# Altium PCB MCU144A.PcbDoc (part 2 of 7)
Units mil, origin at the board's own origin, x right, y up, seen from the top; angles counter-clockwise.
Board outline 2755.9 x 2276.49 mil, 10 copper layers (Top Layer, L02_GND1, L03_SIG1, L04_GND2, L05_SIG2, L06_PWR, L07_GND3, L08_SIG3, L09_GND4, Bottom Layer), stack 60.4 mil thick; 253 components, 312 nets, 1289 pads, 832 vias.

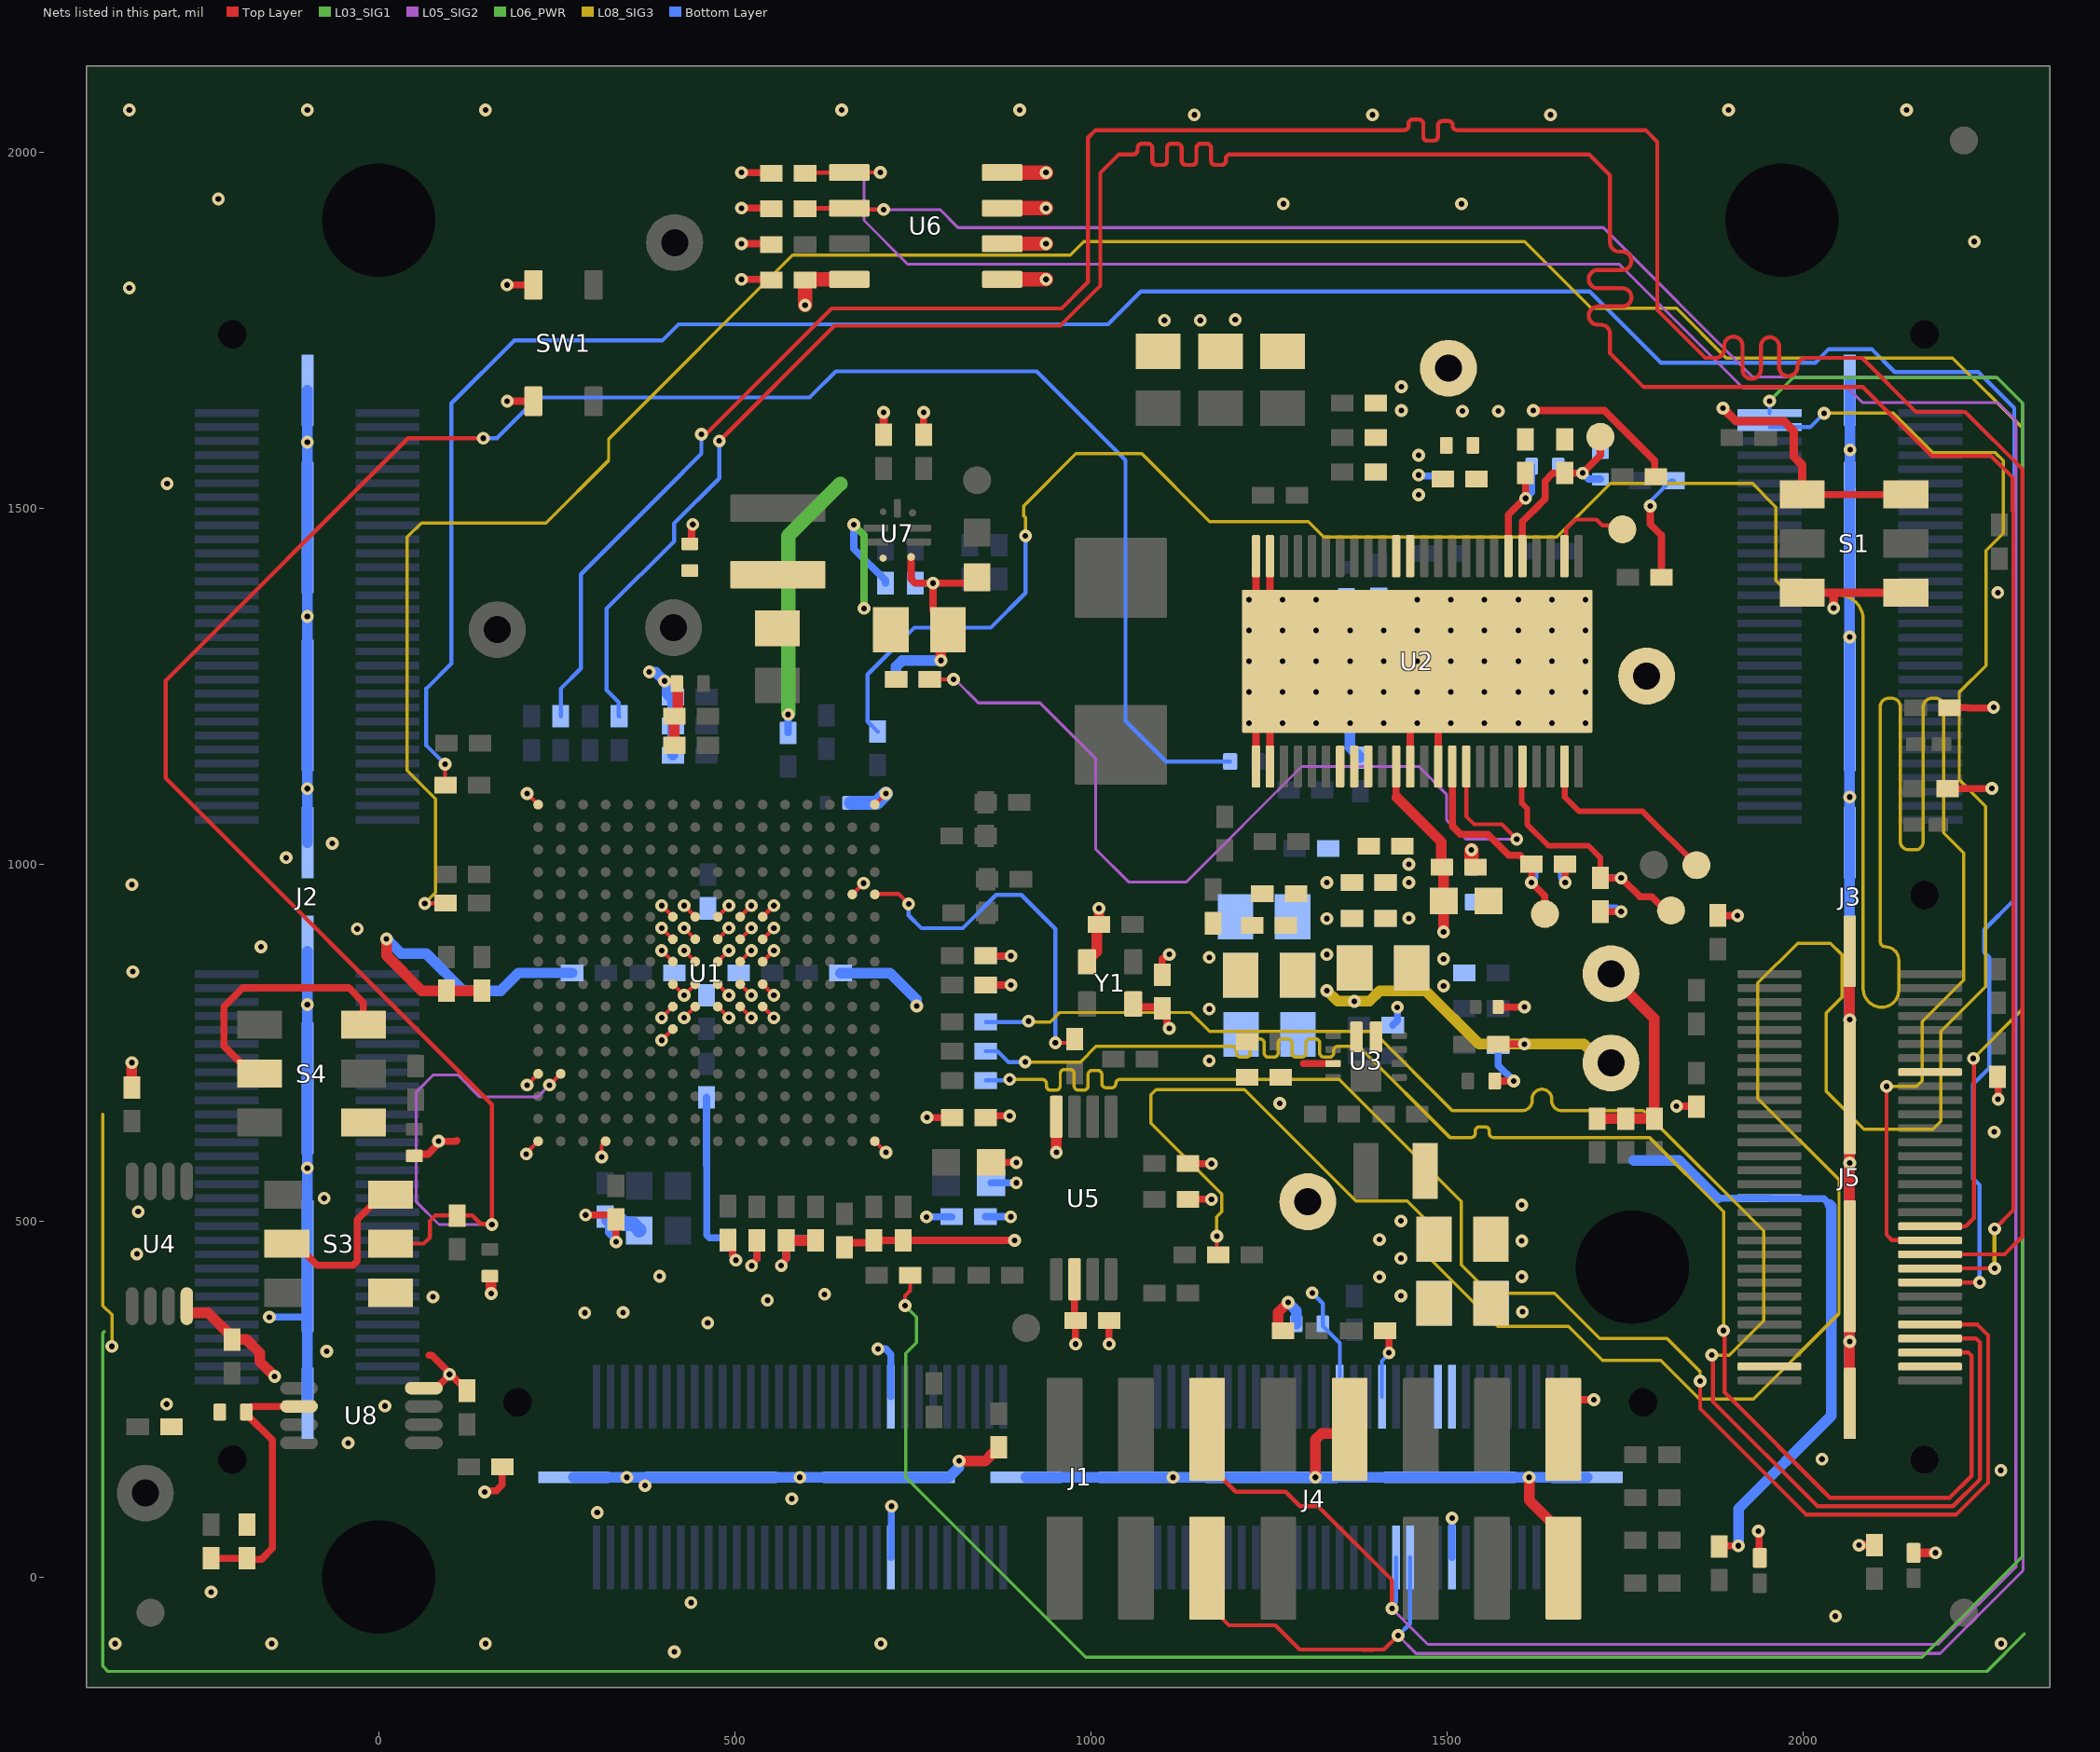
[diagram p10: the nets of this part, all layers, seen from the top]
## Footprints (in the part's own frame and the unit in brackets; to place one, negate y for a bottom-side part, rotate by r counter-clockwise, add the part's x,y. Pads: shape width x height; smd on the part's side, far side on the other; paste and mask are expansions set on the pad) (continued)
ZEX0256A-MFG [mm]
  round 0.35 smd paste+0 mask+0.05: A1(-6,6) A2(-5.2,6) A3(-4.4,6) A4(-3.6,6) A5(-2.8,6) A6(-2,6) A7(-1.2,6) A8(-0.4,6) A9(0.4,6) A10(1.2,6) A11(2,6) A12(2.8,6) A13(3.6,6) A14(4.4,6) A15(5.2,6) A16(6,6) B1(-6,5.2) B2(-5.2,5.2) B3(-4.4,5.2) B4(-3.6,5.2) B5(-2.8,5.2) B6(-2,5.2) B7(-1.2,5.2) B8(-0.4,5.2) B9(0.4,5.2) B10(1.2,5.2) B11(2,5.2) B12(2.8,5.2) B13(3.6,5.2) B14(4.4,5.2) B15(5.2,5.2) B16(6,5.2) C1(-6,4.4) C2(-5.2,4.4) C3(-4.4,4.4) C4(-3.6,4.4) C5(-2.8,4.4) C6(-2,4.4) C7(-1.2,4.4) C8(-0.4,4.4) C9(0.4,4.4) C10(1.2,4.4) C11(2,4.4) C12(2.8,4.4) C13(3.6,4.4) C14(4.4,4.4) C15(5.2,4.4) C16(6,4.4) D1(-6,3.6) D2(-5.2,3.6) D3(-4.4,3.6) D4(-3.6,3.6) D5(-2.8,3.6) D6(-2,3.6) D7(-1.2,3.6) D8(-0.4,3.6) D9(0.4,3.6) D10(1.2,3.6) D11(2,3.6) D12(2.8,3.6) D13(3.6,3.6) D14(4.4,3.6) D15(5.2,3.6) D16(6,3.6) E1(-6,2.8) E2(-5.2,2.8) E3(-4.4,2.8) E4(-3.6,2.8) E5(-2.8,2.8) E6(-2,2.8) E7(-1.2,2.8) E8(-0.4,2.8) E9(0.4,2.8) E10(1.2,2.8) E11(2,2.8) E12(2.8,2.8) E13(3.6,2.8) E14(4.4,2.8) E15(5.2,2.8) E16(6,2.8) F1(-6,2) F2(-5.2,2) F3(-4.4,2) F4(-3.6,2) F5(-2.8,2) F6(-2,2) F7(-1.2,2) F8(-0.4,2) F9(0.4,2) F10(1.2,2) F11(2,2) F12(2.8,2) F13(3.6,2) F14(4.4,2) F15(5.2,2) F16(6,2) G1(-6,1.2) G2(-5.2,1.2) G3(-4.4,1.2) G4(-3.6,1.2) G5(-2.8,1.2) G6(-2,1.2) G7(-1.2,1.2) G8(-0.4,1.2) G9(0.4,1.2) G10(1.2,1.2) G11(2,1.2) G12(2.8,1.2) G13(3.6,1.2) G14(4.4,1.2) G15(5.2,1.2) G16(6,1.2) H1(-6,0.4) H2(-5.2,0.4) H3(-4.4,0.4) H4(-3.6,0.4) H5(-2.8,0.4) H6(-2,0.4) H7(-1.2,0.4) H8(-0.4,0.4) H9(0.4,0.4) H10(1.2,0.4) H11(2,0.4) H12(2.8,0.4) H13(3.6,0.4) H14(4.4,0.4) H15(5.2,0.4) H16(6,0.4) J1(-6,-0.4) J2(-5.2,-0.4) J3(-4.4,-0.4) J4(-3.6,-0.4) J5(-2.8,-0.4) J6(-2,-0.4) J7(-1.2,-0.4) J8(-0.4,-0.4) J9(0.4,-0.4) J10(1.2,-0.4) J11(2,-0.4) J12(2.8,-0.4) J13(3.6,-0.4) J14(4.4,-0.4) J15(5.2,-0.4) J16(6,-0.4) K1(-6,-1.2) K2(-5.2,-1.2) K3(-4.4,-1.2) K4(-3.6,-1.2) K5(-2.8,-1.2) K6(-2,-1.2) K7(-1.2,-1.2) K8(-0.4,-1.2) K9(0.4,-1.2) K10(1.2,-1.2) K11(2,-1.2) K12(2.8,-1.2) K13(3.6,-1.2) K14(4.4,-1.2) K15(5.2,-1.2) K16(6,-1.2) L1(-6,-2) L2(-5.2,-2) L3(-4.4,-2) L4(-3.6,-2) L5(-2.8,-2) L6(-2,-2) L7(-1.2,-2) L8(-0.4,-2) L9(0.4,-2) L10(1.2,-2) L11(2,-2) L12(2.8,-2) L13(3.6,-2) L14(4.4,-2) L15(5.2,-2) L16(6,-2) M1(-6,-2.8) M2(-5.2,-2.8) M3(-4.4,-2.8) M4(-3.6,-2.8) M5(-2.8,-2.8) M6(-2,-2.8) M7(-1.2,-2.8) M8(-0.4,-2.8) M9(0.4,-2.8) M10(1.2,-2.8) M11(2,-2.8) M12(2.8,-2.8) M13(3.6,-2.8) M14(4.4,-2.8) M15(5.2,-2.8) M16(6,-2.8) N1(-6,-3.6) N2(-5.2,-3.6) N3(-4.4,-3.6) N4(-3.6,-3.6) N5(-2.8,-3.6) N6(-2,-3.6) N7(-1.2,-3.6) N8(-0.4,-3.6) N9(0.4,-3.6) N10(1.2,-3.6) N11(2,-3.6) N12(2.8,-3.6) N13(3.6,-3.6) N14(4.4,-3.6) N15(5.2,-3.6) N16(6,-3.6) P1(-6,-4.4) P2(-5.2,-4.4) P3(-4.4,-4.4) P4(-3.6,-4.4) P5(-2.8,-4.4) P6(-2,-4.4) P7(-1.2,-4.4) P8(-0.4,-4.4) P9(0.4,-4.4) P10(1.2,-4.4) P11(2,-4.4) P12(2.8,-4.4) P13(3.6,-4.4) P14(4.4,-4.4) P15(5.2,-4.4) P16(6,-4.4) R1(-6,-5.2) R2(-5.2,-5.2) R3(-4.4,-5.2) R4(-3.6,-5.2) R5(-2.8,-5.2) R6(-2,-5.2) R7(-1.2,-5.2) R8(-0.4,-5.2) R9(0.4,-5.2) R10(1.2,-5.2) R11(2,-5.2) R12(2.8,-5.2) R13(3.6,-5.2) R14(4.4,-5.2) R15(5.2,-5.2) R16(6,-5.2) T1(-6,-6) T2(-5.2,-6) T3(-4.4,-6) T4(-3.6,-6) T5(-2.8,-6) T6(-2,-6) T7(-1.2,-6) T8(-0.4,-6) T9(0.4,-6) T10(1.2,-6) T11(2,-6) T12(2.8,-6) T13(3.6,-6) T14(4.4,-6) T15(5.2,-6) T16(6,-6)
  silkscreen extent -7.17,-6.55 6.55,6.55, body extent -7.05,-7.05 7.05,7.05, height 0.25

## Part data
C1 C2 C46 C49 C52 C53 C61 C63 C65 C70 C72 C86: library part CMP-0120207-1, "10 µF ±20% 10V Ceramic Capacitor X5R 0402 (1005 Metric)", Manufacturer=Murata, Operating Temperature Range="-55°C to +85°C", TempCo=15%, Temperature Characteristic=X5R, Tolerance_%=20%, ValueDisplayed=10uF
C3 C4 C5 C13 C14 C31 C32 C41 C84 C92: library part CMP-0081010-1, "CAP, CERM, 2.2 µF, 25 V,+/- 20%, X5R, 0402", Cap_Case=0402, Manufacturer=MuRata, Supplier Part Number 1=490-10457-1-ND, TempCo=X5R, Tolerance_%=20%, Value2=25V, ValueDisplayed=2.2µF
C6 C7 C8 C9 C10 C11 C12 C15 C16 C17 C18 C19 C20 C21 C22 C23 C24 C25 C26 C27 C35 C36 C37 C38 C39 C40 C45 C58 C59 C60 C62 C64 C67 C69 C71 C73 C74 C75 C76 C77 C81 C83 C85 C88 C91 C93: library part CMP-0006659-2, "CAP, CERM, 0.1 uF, 25 V, +/- 10%, X7R, 0402", Cap_Case=0402, Manufacturer=MuRata, Supplier Part Number 1=490-10698-1-ND, TempCo=X7R, Tolerance_%=10%, Value1=Unknown, Value2=25V, ValueDisplayed=0.1uF
C28 C29 C30 C48 C54 C55 C56 C68 C89 C90: library part CMP-0008305-2, "CAP, CERM, 22 uF, 25 V, +/- 20%, X5R, 0805", Cap_Case=0805, Manufacturer=MuRata, Supplier Part Number 1=490-10749-1-ND, TempCo=X5R, Tolerance_%=20%, Value1=Unknown, Value2=25V, ValueDisplayed=22uF
C33 C34 C51 C57: library part CMP-0006412-2, "CAP, CERM, 1000 pF, 50 V, +/- 5%, C0G/NP0, 0402", Cap_Case=0402, Manufacturer=MuRata, Supplier Part Number 1=490-3244-1-ND, TempCo=C0G/NP0, Tolerance_%=5%, Value1=Unknown, Value2=50V, ValueDisplayed=1000pF
C42 C80 C82: library part CMP-0120206-1, "4.7 µF ±20% 25V Ceramic Capacitor X5S 0402 (1005 Metric)", Manufacturer=Murata, Operating Temperature Range="-55°C to +85°C", TempCo=22%, Temperature Characteristic=X5S, Tolerance_%=20%, ValueDisplayed=4.7uF
C43 C44 C50: library part CMP-0078699-1, "CAP, CERM, 47 µF, 10 V,+/- 20%, X5R, 0805", Cap_Case=0805, Manufacturer=MuRata, Supplier Part Number 1=490-9961-1-ND, TempCo=X5R, Tolerance_%=20%, Value2=10V, ValueDisplayed=47µF
C47: library part CMP-0120205-1, "Multi-Layer Ceramic Capacitor 47pF C0G  ±5% 0402 Paper T/R", Manufacturer=Murata, Operating Temperature Range="-55°C to +125°C", TempCo=30ppm/°C, Temperature Characteristic=C0G, Tolerance_%=5%, ValueDisplayed=47pF
C66: library part CMP-0007336-5, "CAP, CERM, 10 uF, 16 V, +/- 20%, X5R, 0603", Cap_Case=0603, Manufacturer=MuRata, Supplier Part Number 1=GRM188R61C106MAALD-ND, TempCo=X5R, Tolerance_%=20%, Value1=Unknown, Value2=16V, ValueDisplayed=10uF
C78 C79 C87: library part CMP-0086061-1, "CAP, CERM, 1 µF, 25 V,+/- 10%, X5R, 0402", Cap_Case=0402, Manufacturer=MuRata, TempCo=X5R, Tolerance_%=10%, Value2=25V, ValueDisplayed=1µF
C96: library part CMP-0006823-4, "CAP, CERM, 330 pF, 50 V, +/- 5%, C0G/NP0, 0603", Cap_Case=0603, Manufacturer="Wurth Elektronik", Supplier Part Number 1=710-885012006060, TempCo=C0G/NP0, Tolerance_%=5%, Value1=Unknown, Value2=50V, ValueDisplayed=330pF
C97: library part CMP-0123381-1, "Ceramic Capacitor for Automotive 200pF ±1% 50VDC C0G 0402 Paper T/R", Manufacturer=Murata, Operating Temperature Range="-55°C to +125°C", TempCo=30ppm/°C, Temperature Characteristic=C0G, Tolerance_%=0.01%, ValueDisplayed=200pF
C98: library part CMP-0080703-2, "CAP, CERM, 390 pF, 50 V,+/- 10%, X7R, AEC-Q200 Grade 1, 0402", Cap_Case=0402, Manufacturer=MuRata, Supplier Part Number 1=81-GCM155R71H391KA7D, TempCo=X7R, Tolerance_%=10%, Value2=50V, ValueDisplayed=390pF
FID1 FID2 FID3 FID4 FID5 FID6: library part CMP-0077181-1, "Fiducial mark.  There is nothing to buy or mount.", Manufacturer=N/A
J1 J2 J3: library part CMP-0055973-1, "Connector,  0.5mm, 60x2, SMT", Manufacturer=Samtec, Supplier Part Number 1=SAM8181-ND
J4: library part CMP-0121706-1, "Conn Unshrouded HDR 16 POS 2.54mm Solder ST SMT", Manufacturer=Samtec, Operating Temperature Range="-55°C to +125°C"
J5: library part CMP-0088387-1, "CONN RCPT HI-SPD .5MM 60POS DL", Current_A=25A, Digikey Part Number=SAM8180-ND, Manufacturer=Samtec, Mouser Part Number=200-QSH03001LDA, Operating Temperature Range="-55°C to +125°C", Voltage_V=175V
L1: library part CMP-0003363-1, "Ferrite Bead, 220 ohm @ 100 MHz, 2 A, 0805", Manufacturer=MuRata, Supplier Part Number 1=490-1054-1-ND, Value1="0.045 ohm", Value2=2A, ValueDisplayed="220 ohm"
L2 L3 L6: library part CMP-0003173-2, "Ferrite Bead, 60 ohm @ 100 MHz, 3 A, 0603", Manufacturer="Wurth Elektronik", PartNumber=742792602, Supplier Part Number 1=732-4660-1-ND, Value1="0.04 ohm", Value2=3A, ValueDisplayed="60 ohm"
L4: library part CMP-0096709-1, "Inductor Power Shielded Wirewound 2.2uH 20% 100KHz Metal 12A 0.00814Ohm DCR Automotive T/R", Digikey Part Number=445-181515-1-ND, Manufacturer=TDK, Mouser Part Number=810-SPM7054VT-2R2M-D, Operating Temperature Range="-55°C to +155°C", Test Frequency=100kHz, Tolerance_%=20%
L5: library part CMP-0082609-1, "Inductor, Shielded, Metal Composite, 1.5 µH, 2.6 A, 0.06 ohm, SMD", Manufacturer=MuRata, PartNumber=DFE252012P-1R5M{}P2, Value1="0.06 ohm", Value2=2.6A, ValueDisplayed=1.5µH
L7: library part CMP-0090842-1, "Power Inductor, shielded, composite, 1uH 20% tol, DCR 7.2mOhms, SRF 65MHz, Isat 4.8A, Irms 13A, AEC-Q200", Manufacturer=Coilcraft, Operating Temperature Range="to +165°C", Self Resonant Frequency=65MHz, Test Frequency=1MHz, Tolerance_%=20%
LED1 LED2: library part CMP-0067681-2, "LED, Red, SMD", Color=Red, Manufacturer=Kingbright, Power_TotalModule=75mW, Value1=0.075W, Value2=1.95V
LED3 LED4: library part CMP-0067682-2, "LED, Green, SMD", Color=Green, Manufacturer=Kingbright, Power_TotalModule=75mW, Value1=0.075W, Value2=2.1V
Logo1: library part CMP-0074844-1
Logo2: library part CMP-0074838-1, "Texas Instrument Corporate Signature"
Logo3: library part CMP-0074847-1, "FCC_disclaimer"
Logo4: library part CMP-0074769-3, Manufacturer="Texas Instruments"
MH1 MH2 MH3 MH4: library part CMP-0078424-2, "PCB Mounting Hole, No Pad", Manufacturer=Any, PartNumber=N/A
R1 R4 R10 R16 R49 R50: library part CMP-0026631-1, "RES, 4.70 k, 1%, 0.063 W, 0402", Manufacturer="TE Connectivity", Power_W=63mW, Supplier Part Number 1=A121542CT-ND, TempCo="100 ppm/C", Tolerance_%=1%, Value2=0.063W, Value_Code=4k70, ValueDisplayed=4.70k
R2 R3 R6 R11 R21 R23 R24 R30 R33 R39 R40 R44: library part CMP-0077731-1, "RES, 10.0 k, 1%, 0.063 W, AEC-Q200 Grade 0, 0402", Manufacturer="Yageo America", Power_W=63mW, Supplier Part Number 1=YAG3436CT-ND, TempCo="100 ppm/C", Tolerance_%=1%, Value2=0.063W, Value_Code=10k0, ValueDisplayed=10.0k
R5: library part CMP-0092615-1, "12 kOhms ±1% 0.063W, 1/16W Chip Resistor 0402 (1005 Metric) Moisture Resistant Thick Film", Digikey Part Number=311-12.0KLRCT-ND, Manufacturer=Yageo, Mouser Part Number=603-RC0402FR-0712KL, Operating Temperature Range="-55°C to +155°C", Power_W=63mW, TempCo=100ppm/°C, Tolerance_%=1%
R7 R15 R22 R25 R26 R27 R28 R29 R31 R32 R35 R36 R37 R45 R52 R54 R55 R60 R61 R62 R63 R64 R65 R66 R67 R68 R69 R71 R74 R79 R81 R82 R83 R84 R86 R87 R88 R89 R90 R91 R92 R93 R94 R95 R96 R97: library part CMP-0026822-3, "RES, 0, 5%, 0.063 W, AEC-Q200 Grade 0, 0402", Manufacturer=Vishay-Dale, Power_W=63mW, Supplier Part Number 1=541-0.0JCT-ND, TempCo="200 ppm/C", Tolerance_%=5%, Value2=0.063W, Value_Code=0000, ValueDisplayed=0
R8 R19: library part CMP-0026733-1, "RES, 3.00 k, 1%, 0.0625 W, 0402", Manufacturer="Yageo America", Power_W=62.5mW, Supplier Part Number 1=311-3KLRCT-ND, TempCo="100 ppm/C", Tolerance_%=1%, Value2=0.0625W, Value_Code=3k00, ValueDisplayed=3.00k
R9: library part CMP-0026920-5, "RES, 3.9 k, 5%, 0.063 W, AEC-Q200 Grade 0, 0402", Manufacturer=Vishay-Dale, Power_W=63mW, Supplier Part Number 1=541-3.9KJCT-ND, TempCo="200 ppm/C", Tolerance_%=5%, Value2=0.063W, Value_Code=3k90, ValueDisplayed=3.9k
R12: library part CMP-0026280-2, "RES, 301 k, 1%, 0.063 W, AEC-Q200 Grade 0, 0402", Manufacturer=Vishay-Dale, Power_W=63mW, Supplier Part Number 1=541-301KLCT-ND, TempCo="100 ppm/C", Tolerance_%=1%, Value2=0.063W, Value_Code=301k
R13: library part CMP-0026187-2, "RES, 23.7 k, 1%, 0.063 W, AEC-Q200 Grade 0, 0402", Manufacturer=Vishay-Dale, Power_W=63mW, Supplier Part Number 1=541-23.7KLCT-ND, TempCo="100 ppm/C", Tolerance_%=1%, Value2=0.063W, Value_Code=23k7, ValueDisplayed=23.7k
R14: library part CMP-0026102-2, "RES, 1.05 M, 1%, 0.063 W, AEC-Q200 Grade 0, 0402", Manufacturer=Vishay-Dale, Power_W=63mW, Supplier Part Number 1=541-1.05MLCT-ND, TempCo="100 ppm/C", Tolerance_%=1%, Value2=0.063W, Value_Code=1M05, ValueDisplayed=1.05M
R17: library part CMP-0026046-3, "RES, 174 k, 1%, 0.063 W, AEC-Q200 Grade 0, 0402", Manufacturer=Vishay-Dale, Power_W=63mW, Supplier Part Number 1=541-174KLCT-ND, TempCo="100 ppm/C", Tolerance_%=1%, Value2=0.063W, Value_Code=174k
R18: library part CMP-0025973-3, "RES, 118 k, 1%, 0.063 W, AEC-Q200 Grade 0, 0402", Manufacturer=Vishay-Dale, Power_W=63mW, Supplier Part Number 1=541-118KLCT-ND, TempCo="100 ppm/C", Tolerance_%=1%, Value2=0.063W, Value_Code=118k
R20 R47 R48: library part CMP-0026854-5, "RES, 1.2 k, 5%, 0.063 W, AEC-Q200 Grade 0, 0402", Manufacturer=Vishay-Dale, Power_W=63mW, Supplier Part Number 1=541-1.2KJCT-ND, TempCo="200 ppm/C", Tolerance_%=5%, Value2=0.063W, Value_Code=1k20, ValueDisplayed=1.2k
R34 R38 R80: library part CMP-0026544-2, "RES, 75.0, 1%, 0.063 W, AEC-Q200 Grade 0, 0402", Manufacturer=Vishay-Dale, Power_W=63mW, Supplier Part Number 1=541-75.0LCT-ND, TempCo="100 ppm/C", Tolerance_%=1%, Value2=0.063W, Value_Code=75R0, ValueDisplayed=75.0
R41: library part CMP-0026231-2, "RES, 2.20 k, 1%, 0.063 W, AEC-Q200 Grade 0, 0402", Manufacturer=Vishay-Dale, Power_W=63mW, Supplier Part Number 1=541-2.20KLCT-ND, TempCo="100 ppm/C", Tolerance_%=1%, Value2=0.063W, Value_Code=2k20, ValueDisplayed=2.20k
R42 R43: library part CMP-0026237-2, "RES, 2.49 k, 1%, 0.063 W, AEC-Q200 Grade 0, 0402", Manufacturer=Vishay-Dale, Power_W=63mW, Supplier Part Number 1=541-2.49KLCT-ND, TempCo="100 ppm/C", Tolerance_%=1%, Value2=0.063W, Value_Code=2k49, ValueDisplayed=2.49k
R46: library part CMP-0026918-5, "RES, 3.3 k, 5%, 0.063 W, AEC-Q200 Grade 0, 0402", Manufacturer=Vishay-Dale, Power_W=63mW, Supplier Part Number 1=541-3.3KJCT-ND, TempCo="200 ppm/C", Tolerance_%=5%, Value2=0.063W, Value_Code=3k30, ValueDisplayed=3.3k
R53: library part CMP-0026657-1, "RES, 1.00 k, 1%, 0.1 W, 0402", Manufacturer=Panasonic, Power_W=100mW, Supplier Part Number 1=P1.00KLCT-ND, TempCo="100 ppm/C", Tolerance_%=1%, Value2=0.1W, Value_Code=1k00, ValueDisplayed=1.00k
R56 R58: library part CMP-0078660-1, "RES, 0.1, 1%, 0.25 W, 0402", Manufacturer=Panasonic, Power_W=250mW, Supplier Part Number 1=P17368CT-ND, TempCo="300 ppm/C", Tolerance_%=1%, Value2=0.25W, Value_Code=R100, ValueDisplayed=0.1
R59 R85: library part CMP-0025951-3, "RES, 100, 1%, 0.063 W, AEC-Q200 Grade 0, 0402", Manufacturer=Vishay-Dale, Power_W=63mW, Supplier Part Number 1=541-100LCT-ND, TempCo="100 ppm/C", Tolerance_%=1%, Value2=0.063W, Value_Code=100R, ValueDisplayed=100
R70: library part CMP-0025874-4, "RES, 0, 5%, 0.1 W, AEC-Q200 Grade 0, 0603", Manufacturer=Panasonic, Power_W=100mW, Supplier Part Number 1=P0.0GCT-ND, TempCo="600 ppm/C", Tolerance_%=5%, Value2=0.1W, Value_Code=0000, ValueDisplayed=0
R72: library part CMP-0026040-3, "RES, 16.2 k, 1%, 0.063 W, AEC-Q200 Grade 0, 0402", Manufacturer=Vishay-Dale, Power_W=63mW, Supplier Part Number 1=541-16.2KLCT-ND, TempCo="100 ppm/C", Tolerance_%=1%, Value2=0.063W, Value_Code=16k2, ValueDisplayed=16.2k
R73: library part CMP-0026034-3, "RES, 162 k, 1%, 0.063 W, AEC-Q200 Grade 0, 0402", Manufacturer=Vishay-Dale, Power_W=63mW, Supplier Part Number 1=541-162KLCT-ND, TempCo="100 ppm/C", Tolerance_%=1%, Value2=0.063W, Value_Code=162k
R76: library part CMP-0026021-3, "RES, 150 k, 1%, 0.063 W, AEC-Q200 Grade 0, 0402", Manufacturer=Vishay-Dale, Power_W=63mW, Supplier Part Number 1=541-150KLCT-ND, TempCo="100 ppm/C", Tolerance_%=1%, Value2=0.063W, Value_Code=150k
R77: library part CMP-0026027-3, "RES, 15.0 k, 1%, 0.063 W, AEC-Q200 Grade 0, 0402", Manufacturer=Vishay-Dale, Power_W=63mW, Supplier Part Number 1=541-15.0KLCT-ND, TempCo="100 ppm/C", Tolerance_%=1%, Value2=0.063W, Value_Code=15k0, ValueDisplayed=15.0k
S1 S3 S4: library part CMP-0002233-1, "Switch, Dual SPDT,  2 Pos, 0.1A, 6VDC, SMD", CurrentRating_mA=100A, Manufacturer="Copal Electronics", Supplier Part Number 1=CASD20JCT-ND
SW1: library part CMP-0087265-1, "SWITCH TACTILE SPST-NO 0.05A 16V", CurrentRating_mA=50mA, Manufacturer="C&K Components"
TP1 TP2 TP3 TP5 TP8 TP14 TP15 TP16 TP17: "TEST POINT.  No entry in BOM.", Manufacturer=N/A
TP4 TP6 TP7 TP9 TP10 TP11 TP12 TP13: library part CMP-0003825-1, "1mm Test Point, SMT", Manufacturer=Any
U1: library part CMP-0121934-2, "Real-Time Microcontroller", Frequency_Fixed=200MHz, Manufacturer="Texas Instruments", Max Supply Voltage=3.63V, Min Supply Voltage=1.14V, Operating Temperature Range="-40°C to +105°C"
U2: library part CMP-0095884-2, "Power Management IC For Safety-Relevant Applications HTSSOP48 5 Outputs 4 LDO and 1 Synchronous Buck-Boost Regulator", Manufacturer="Texas Instruments", Max Supply Voltage=28V, Min Supply Voltage=2.3V, Operating Temperature Range="-40°C to +150°C"
U3: library part CMP-0074067-1, "12.6-V, 7-A Fully-Integrated Synchronous Boost Converters in 2.0-mm x 2.5-mm VQFN Package, RNR0011A (VQFN-HR-11)", Alternate Manufacturer="Texas Instruments", Alternate PartNumber=TPS61089RNRT
U4: library part CMP-0040680-2, "Precision, Zero-Crossover, 20MHz, 0.9pA Ib, RRIO, CMOS Operational Amplifier, DGK0008A (VSSOP-8)", Manufacturer="Texas Instruments", Total Supply Voltage(Max)(+5V is 5, +/-5V is 10)=5.5, Total Supply Voltage(Min)(+5V is 5, +/-5V is 10)=1.8
U5: library part CMP-0094559-1, "Clock Clock Buffer IC 1:3 250 MHz 8-TSSOP", Digikey Part Number=296-LMK1C1103PWRCT-ND, Manufacturer="Texas Instruments", Max Supply Voltage=3.465V, Min Supply Voltage=1.71V, Mouser Part Number=595-LMK1C1103PWR, Nominal Supply Current=8-33mA, Operating Temperature Range="-40°C to +125°C"
U6: library part CMP-0082059-1, "16 Kb I2C EEPROM Serial, SOIC-8", Manufacturer="ON Semiconductor", Supplier Part Number 1=CAT24C16WI-GT3CT-ND
U7: library part CMP-0121948-1, "3-V to 18-V, 2-A, Automotive Low IQ Buck Converter with +165°C TJ", Digikey Part Number=296-TPS62902QRYTRQ1CT-ND, Manufacturer="Texas Instruments", Max Supply Voltage=18V, Min Supply Voltage=3V, Mouser Part Number=595-TPS62902QRYTRQ1, Nominal Supply Current=8mA, Operating Temperature Range="-40°C to +165°C", Output Voltage=0.4-5.5V, Switching Frequency=1/2.5MHz
U8: library part CMP-0032596-2, "Low Noise, Very Low Drift, Precision Series Voltage Reference, DGK0008A (VSSOP-8)", Manufacturer="Texas Instruments", Rating=Catalog, Temp Coeff(Max)(ppm/ degree C)=3
Y1: library part CMP-0096024-2, "High-Performance BAW Oscillator", Frequency Stability=25ppm, Frequency_Fixed=25MHz, Load Capacitance=30pF, Manufacturer="Texas Instruments", Max Supply Current=50mA, Max Supply Voltage=3.465V, Min Supply Voltage=2.375V, Operating Temperature Range="-40°C to +105°C"
ZZ1: library part CMP-0003616-3
ZZ2: library part CMP-0077236-1
ZZ3: library part CMP-0077237-1
ZZ4: library part CMP-0077238-1

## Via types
v1: diameter 18, hole 8, Top Layer to Bottom Layer, tented both sides, 776 vias
v2: diameter 19.68, hole 7.87, Top Layer to Bottom Layer, tented top, 54 vias
v3: diameter 18/18/18/18/18/18/18/18/18/18 (per signal layer), hole 8, Top Layer to Bottom Layer, tented both sides, 2 vias

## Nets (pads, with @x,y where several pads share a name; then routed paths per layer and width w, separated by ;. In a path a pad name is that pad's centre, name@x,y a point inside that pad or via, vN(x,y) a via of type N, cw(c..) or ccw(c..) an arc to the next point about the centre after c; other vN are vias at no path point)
3V3_LDO4: C69.1 C70.2 U2.30 | length 176
  Top Layer w10: U2.30@1585.89,1433.38 1585.89,1491.62 1608.82,1514.55 v1(1610,1514.55) C69.1@1610,1550
  Bottom Layer w10: v1(1610,1514.55) 1618.47,1523.02 C70.2@1618.47,1559.71
3V3_OUT: C4.1 C5.1 C62.1 C63.2 C74.1 C75.1 C77.1 J1.28 J4.1 L2.1 L3.1 R1.2 R4.2 R10.2 R16.2 R20.2 R30.2 R39.2 R40.2 R41.2 R46.2 R47.2 R48.2 R49.2 R50.2 R59.1 R85.1 S1.3 S1.6 TP16.1 U2.37 U2.38 U5.6 U6.8 Y1.4 | length 2064.1
  Top Layer w10: v1(509.25,1922) R49.2@551.38,1922 ; v1(509.25,1972) R50.2@551.38,1972 ; R39.2@654.16,462.63 660.97,469.44 691.97,469.44 R40.2@695.16,472.63 R41.2@736.16,472.63 v1(892.85,472.63) ; C4.1@851.98,647.5 885.64,647.5 v1(885.88,647.25) ; L3.1@859.66,582.23 v1@894.91,582.23 ; U5.6@976.97,418.02 976.97,363.37 978.15,362.19 C74.1@978.15,360.19 978.15,327.26 v1(978.31,327.1) ; Y1.4@1067.48,800.47 C75.1@1099.77,800.47 ; C75.1@1099.77,798.57 1106.58,791.76 1106.58,775.59 1109.77,772.4 v1(1109.77,770.23) v1@1110,770 ; R30.2@1136.26,580.38 v1(1169.18,580.38) ; R1.2@1412.62,346 1418.27,340.35 v1(1418.27,314.81) ; J4.1@1663,207.44 1663,229 1683,249 v1(1706,249) ; v1(1785.18,1503.69) 1785,1503.51 1785,1478.58 1800.69,1462.88 R16.2@1800.69,1403.68 ; R59.1@1880.05,929.04 1880.31,928.78 v1(1907.66,928.78) ; S1.6@1998.33,1520 S1.3@2144,1520 ; R20.2@2097,47.75 R20.2@2099.84,44.91 ; R47.2@2202.46,1106.99 2228.94,1106.99 2229.15,1106.78 v1@2264.59,1106.78 ; R48.2@2204.87,1220.57 2231.35,1220.57 2231.56,1220.36 v1@2267,1220.36 ; R85.1@2272.72,702.22 2273.36,702.86 v1(2273.36,670.94)
  Top Layer w12: v1(1887.16,1641.05) 1905.28,1622.94 1972.56,1622.94 1986.43,1609.07 1986.43,1573.3 1998.33,1561.39 S1.6@1998.33,1520 ; v1(2078.19,44.6) 2078.34,44.75 2099.69,44.75 R20.2@2099.84,44.91
  Top Layer w20: v1(598.62,1785.69) C77.1@598.62,1821 598.62,1822 U6.8@660.72,1822
  L06_PWR w20: v1@575,1213 575,1461.7 648.22,1534.92
  Bottom Layer w5.66: J1.28@1408.33,253.19 1408.33,303.2 1418.27,313.14 v1(1418.27,314.81) ; v1(1785.18,1503.69) 1787.54,1506.05 1787.54,1512.86 1814.05,1539.37 R10.2@1817.99,1539.37
  Bottom Layer w10: R46.2@574.63,1185.33 574.82,1185.52 574.82,1212.82 v1@575,1213 ; C5.1@851.78,505.98 v1@887.04,505.98 ; L2.1@859.66,553.68 v1@894.91,553.68 ; v1(1460,1547.3) 1461.53,1545.77 1489.8,1545.77 R4.2@1493.76,1541.81
  other v1: 887.23,505.79 895.1,553.49 895.11,582.03 2264.59,1107.42 575,1211 2267,1221 1460,1519.59 1460,1575
5V0_IN: C43.1 C44.1 C45.1 C50.1 J1.18 J1.20 J3.27 L5.1 R19.2 TP5.1 U3.9 | length 904.2
  Top Layer w10: 1298.07,721.02 U3.9@1339.96,721.02 ; R19.2@1881.81,42.75 1882.88,43.82 v1(1908.75,43.82)
  Bottom Layer w10: 1878.98,531.67 J3.27@1952.59,531.67 1953,531.27 2028.73,531.27 2037,523
  Bottom Layer w15: 1762,585 1825.65,585 1878.98,531.67 ; v1(1908.75,43.82) 1908.75,95.75 2039.29,226.29 2039.29,520.71 2037,523
  other v1: 1435,395 1405,421.25 1435,447.5 1405,473.75 1435,500 1265,665
5V0_LDO2: C52.2 C64.1 C65.2 L6.1 U2.11 | length 258.1
  Top Layer w10: U2.11@1428.41,1138.1 1428.41,1096.54 1429.26,1095.7
  Top Layer w15: 1429.26,1094.74 1491.94,1032.06 C64.1@1491.94,997.56 ; C64.1@1492.5,997 1495.07,994.43 L6.1@1495.07,940.69 ; v1(1495,905.81) L6.1@1495,940.62
5V0_OUT_CAN: C53.2 J1.34 L6.2 R3.2 R23.2 R24.2 TP17.1 | length 470.3
  Top Layer w15: R24.2@1710.74,643.7 R23.2@1750.74,643.7 R3.2@1790.75,643.7 1790.75,784.25 1730,845 TP17.1@1730,847
  Bottom Layer w5.66: v1(1310.56,398.97) 1325.37,384.15 C53.2@1325.37,355.4 1325.37,352.45 1349.27,328.55 J1.34@1349.27,253.19
+1V25: C1.2 C68.1 L1.1 L7.2 R72.2 R73.2 U7.3 | length 223.8
  L06_PWR w10: v1(666.97,1477.44) 681.38,1463.03 v1(681.38,1360)
  Bottom Layer w10: v1(666.97,1477.44) 666.97,1443.96 711.5,1399.42 R73.2@711.5,1395.49
+12V0: C28.1 C29.1 C30.1 C31.1 C32.1 C33.1 C34.1 C35.1 C36.1 C37.1 C48.1 C89.1 C90.1 R6.2 R14.2 TP8.1 U2.7 U2.8 U2.9 U3.6 | length 524.2
  Top Layer w10: R14.2@1571.54,748.33 v1(1608.4,748.33)
  L08_SIG3 w15: v1(1331.11,823.5) 1346.26,808.35 v1(1369.81,808.35) 1390.67,808.35 1405.31,823 1469.87,823 1544.54,748.33 v1(1608.4,748.33) 1691.71,748.33 1717.04,723 1709,723 TP8.1@1737,695
  other v1: 1331.11,874 1331.11,924.5 1331.11,975
ADC_3V0_VREF: C79.1 C86.2 R53.2 U8.6 | length 378
  Top Layer w10: R53.2@-235,26.38 C79.1@-185,26.38 -183.62,25 -164.5,25 -149.12,40.38 -149.12,192.16 -185.62,228.66 C86.2@-185.62,231.61 -185.62,234.56 -181.76,238.42 -178.81,238.42 -177.61,239.61 U8.6@-111.81,239.61
CFG_VOUT1: C71.1 C72.2 TP6.1 U2.20 | length 384.9
  Top Layer w8: U2.20@1605.58,1138.1 1604.62,1137.15 1604.62,1086.66 1612.11,1079.17 1612.11,1056.89 1642.19,1026.81 1698.19,1026.81 1715,1010 C71.1@1715,981.5
  Top Layer w10: C71.1@1715,981.5 v1(1744.25,981.5) 1770.75,955 1787.08,955 1806.29,935.79 TP6.1@1814.24,935.79
  Bottom Layer w10: C72.2@1715,976.7 1718.86,980.56 1724.97,980.56 1725.91,981.5 v1(1744.25,981.5)
CFG_VOUT2: C61.2 C73.1 TP9.1 U2.29 | length 286.6
  Top Layer w10: U2.29@1605.58,1433.38 1605.58,1481.84 1635,1511.27 ; 1620.29,1496.56 1637.51,1513.78 1637.51,1538.91 1648.29,1549.69 1664.69,1549.69 C73.1@1665,1550 v1(1690,1550) 1715,1575 TP9.1@1715,1601
  Bottom Layer w10: v1(1690,1550) 1698.29,1541.71 1714.59,1541.71 C61.2@1715,1541.3
CFG_VOUT3: C49.2 C67.1 TP12.1 U2.15 | length 319.4
  Top Layer w10: U2.15@1507.52,1135 1507.52,1054.3 1518.83,1042.99 1557.01,1042.99 1586.57,1013.43 1602.01,1013.43 1614.44,1001 C67.1@1618.38,1001 v1(1618.38,975) 1637,956.37 TP12.1@1637,930.95
  Bottom Layer w10: v1(1618.38,975) 1618.38,977.16 1623.3,982.08 C49.2@1623.3,1001
COMP1_OUT: TP10.1 U2.23 | length 264.4
  Top Layer w8: U2.23@1665,1135 1665,1095.15 1685,1075.15 1774.41,1075.15 TP10.1@1850,999.56
COMP2_OUT: TP4.1 U2.26 | length 135.4
  Top Layer w5.66: U2.26@1664.63,1433.38 U2.26@1666.82,1435.57 ; U2.26@1665,1430.28 1666.82,1432.1 U2.26@1666.82,1435.57 ; TP4.1@1746,1471 1740.45,1476.55 1717.82,1476.55 1709.61,1484.77 1680.19,1484.77 1666.82,1471.4 U2.26@1666.82,1435.57
DLT_GPIO6: J5.44 R91.1 | length 4409.2
  Top Layer w5.66: v1(478.15,1595.1) 639.96,1756.91 956.88,1756.91 1013,1813.03 1013,1971.34 1039.19,1997.53 1056.29,1997.53 1059.12,1997.53 ccw(c1059.12,2003.72) 1065.32,2003.72 1065.32,2006.33 cw(c1071.52,2006.33) 1071.52,2012.53 1079.78,2012.53 cw(c1079.78,2006.33) 1085.98,2006.33 1085.98,1988.72 ccw(c1092.18,1988.72) 1092.18,1982.53 1100.44,1982.53 ccw(c1100.44,1988.72) 1106.64,1988.72 1106.64,2006.33 cw(c1112.84,2006.33) 1112.84,2012.53 1121.1,2012.53 cw(c1121.1,2006.33) 1127.3,2006.33 1127.3,1988.72 ccw(c1133.5,1988.72) 1133.5,1982.53 1141.76,1982.53 ccw(c1141.76,1988.72) 1147.96,1988.72 1147.96,2006.33 cw(c1154.16,2006.33) 1154.16,2012.53 1162.42,2012.53 cw(c1162.42,2006.33) 1168.62,2006.33 1168.62,1988.72 ccw(c1174.82,1988.72) 1174.82,1982.53 1183.08,1982.53 ccw(c1183.08,1988.72) 1189.28,1988.72 1189.28,1991.33 cw(c1195.48,1991.33) 1195.48,1997.53 1219.68,1997.53 1699.13,1997.53 1728.67,1967.99 1728.67,1876.53 1728.67,1873.7 ccw(c1741.5,1873.7) 1741.5,1860.87 1745.84,1860.87 cw(c1745.84,1848.04) 1745.84,1835.21 1711.5,1835.21 ccw(c1711.5,1822.38) 1711.5,1809.55 1745.84,1809.55 cw(c1745.84,1796.72) 1745.84,1783.89 1711.5,1783.89 ccw(c1711.5,1771.06) 1711.5,1758.23 1715.84,1758.23 cw(c1715.84,1745.4) 1728.67,1745.4 1728.67,1717.99 1735,1711.65 1751.65,1695 1775.91,1670.74 2083.64,1670.74 2180.39,1574 2263.42,1574 2293.94,1543.48 2293.94,1496.93 2294.64,1496.24 2294.64,515.07 v3(2268.39,488.83) ; J5.44@2177.8,433.35 v1(2268.39,433.35)
  L08_SIG3 w5.66: v1(2268.39,433.35) v3(2268.39,488.83)
  Bottom Layer w5.66: R91.1@337.63,1208.44 336.91,1209.16 336.91,1228.19 319.88,1245.22 319.88,1359.64 367.1,1406.85 367.72,1406.85 414.93,1454.07 414.93,1479.35 478.15,1542.57 v1(478.15,1595.1)
DLT_GPIO7: J5.46 R96.1 | length 4234.7
  Top Layer w5.66: v1(93.32,1141.27) 93.32,1112.4 R96.1@93.84,1111.89 ; J5.46@2177.8,413.66 v3(2247.44,413.66)
  Bottom Layer w5.66: v1(93.32,1141.27) 66.92,1167.67 66.92,1247.46 102.13,1282.68 102.13,1647.87 190.38,1736.13 398.16,1736.13 420.96,1758.93 1023.93,1758.93 1070,1805 1700,1805 1800,1705 2016.59,1705 2035.64,1724.05 2095.95,1724.05 2128.28,1691.72 2245.79,1691.72 2296.02,1641.49 2296.02,951.02 2253.83,908.83 2253.83,877.17 2260.91,870.1 2260.91,714.9 2237.99,691.99 2237.99,559.59 2247.44,550.15 v3@2247.44,414.41
DLT_GPIO8: J5.42 R83.1 | length 4420.8
  Top Layer w5.66: v1@452.76,1598.12 635.81,1781.17 958.68,1781.17 995.79,1818.28 995.79,2020.93 1006.44,2031.58 1436.71,2031.58 1439.54,2031.58 ccw(c1439.54,2037.78) 1445.73,2037.78 1445.73,2040.38 cw(c1451.93,2040.38) 1451.93,2046.58 1460.2,2046.58 cw(c1460.2,2040.38) 1466.39,2040.38 1466.39,2022.78 ccw(c1472.59,2022.78) 1472.59,2016.58 1480.86,2016.58 ccw(c1480.86,2022.78) 1487.05,2022.78 1487.05,2038.08 cw(c1493.25,2038.08) 1493.25,2044.28 1501.52,2044.28 cw(c1501.52,2038.08) 1507.71,2038.08 1507.71,2037.78 ccw(c1513.91,2037.78) 1513.91,2031.58 1564.83,2031.58 1778.42,2031.58 1795,2015 1795,1779 1862.31,1711.69 1873.31,1711.69 1876.14,1711.69 ccw(c1876.14,1724.52) 1888.97,1724.52 1888.97,1728.86 cw(c1901.8,1728.86) 1914.63,1728.86 1914.63,1695.23 ccw(c1927.46,1695.23) 1940.29,1695.23 1940.29,1727.92 cw(c1953.12,1727.92) 1965.95,1727.92 1965.95,1698.85 ccw(c1978.78,1698.85) 1991.61,1698.85 cw(c2004.44,1698.86) 2004.44,1711.69 2041.33,1711.69 2082.31,1711.69 2158,1636 2227,1636 2307.62,1555.38 2307.62,478.2 2282.44,453.03 J5.42@2177.8,453.03
  Bottom Layer w5.66: R83.1@255.63,1208.44 255.63,1247.37 283.94,1275.68 283.94,1407.86 427.97,1551.9 427.97,1552.29 453.05,1577.36 v1(453.05,1604.37)
DLT_GPIO16: J5.38 R84.1 | length 4336
  Top Layer w5.66: v1(64.81,945.82) 93.33,945.82 R84.1@93.75,946.24 ; J5.38@2177.8,492.4 2227.74,492.4 2239.31,503.97 2239.31,727.54 v1(2238.66,728.18) v1@2238.44,728.4
  L08_SIG3 w4.5: v1(64.81,945.82) 80,961.01 80,1092.5 40,1132.5 40,1460 60,1480 235,1480 322.9,1567.9 322.9,1597.9 581.22,1856.22 971.08,1856.22 989.86,1875 1608.49,1875 1702.1,1781.39 1822,1781.39 1891.7,1711.69 2209.22,1711.69 2307.12,1613.79 2307.12,796.64 v1(2238.66,728.18)
DLT_GPIO49: J5.54 R90.1 | length 2262.3
  Top Layer w5.66: v1(1871.48,311.61) 1872.89,310.2 1872.89,246.42 2019.76,99.55 2210.09,99.55 2247.8,137.26 2247.8,329.45 2242.18,335.07 2177.94,335.07 J5.54@2177.8,334.92
  L08_SIG3 w4.5: v1(912.24,780.48) 913.33,779.39 942.79,779.39 955.97,792.58 1139.79,792.58 1166.37,766 1396,766 1507,655 1548.24,655 1605.49,655 ccw(c1605.49,668.75) 1619.24,668.75 1619.24,671.25 cw(c1632.99,671.25) 1646.74,671.25 1646.74,668.75 ccw(c1660.49,668.75) 1660.49,655 1680,655 1775.22,655 1944.28,485.94 1944.28,360.01 1895.88,311.61 v1(1871.48,311.61)
  Bottom Layer w5.66: R90.1@852.26,779.3 911.05,779.3 v1(912.24,780.48)
DLT_GPIO50: J5.56 R95.1 | length 2214.1
  Top Layer w5.66: v1(1887.9,346.16) 1889.31,344.75 1889.31,259.29 2037.39,111.21 2205.26,111.21 2236.14,142.09 2236.14,310.76 2231.73,315.18 2177.86,315.18 J5.56@2177.8,315.24
  L08_SIG3 w4.5: v1(907.52,723.11) 985.11,723.11 1007,745 1176.51,745 1198.26,745 cw(c1198.26,739.15) 1204.11,739.15 1204.11,735.85 ccw(c1209.96,735.85) 1209.96,730 1217.76,730 ccw(c1217.76,735.85) 1223.61,735.85 1223.61,749.65 cw(c1229.46,749.65) 1229.46,755.5 1237.26,755.5 cw(c1237.26,749.65) 1243.11,749.65 1243.11,735.85 ccw(c1248.96,735.85) 1248.96,730 1256.76,730 ccw(c1256.76,735.85) 1262.61,735.85 1262.61,749.65 cw(c1268.46,749.65) 1268.46,755.5 1276.26,755.5 cw(c1276.26,749.65) 1282.11,749.65 1282.11,735.85 ccw(c1287.96,735.85) 1287.96,730 1295.76,730 ccw(c1295.76,735.85) 1301.61,735.85 1301.61,749.65 cw(c1307.46,749.65) 1307.46,755.5 1315.26,755.5 cw(c1315.26,749.65) 1321.11,749.65 1321.11,735.85 ccw(c1326.96,735.85) 1326.96,730 1334.76,730 ccw(c1334.76,735.85) 1340.61,735.85 1340.61,739.15 cw(c1346.46,739.15) 1346.46,745 1376,745 1377.17,743.83 1503.77,617.23 1531.45,617.23 1533.7,617.23 ccw(c1533.7,623.08) 1539.55,623.08 1539.55,626.38 cw(c1545.4,626.38) 1545.4,632.23 1553.2,632.23 cw(c1553.2,626.38) 1559.05,626.38 1559.05,623.08 ccw(c1564.9,623.08) 1564.9,617.23 1598,617.23 1783.77,617.23 1887.9,513.1 v1(1887.9,346.16)
  Bottom Layer w5.66: R95.1@852.26,738.3 868.7,738.3 883.89,723.11 v1(907.52,723.11)
DLT_GPIO51: J5.52 R82.1 | length 2162.3
  Top Layer w5.66: v1(1855.06,275.1) 1855.06,236.45 2003.61,87.89 2138.16,87.89 2157.48,87.89 2209.92,87.89 2212.39,87.89 2214.92,87.89 2259.47,132.43 2259.47,134.97 2259.47,137.44 2259.47,339.36 2244.39,354.44 2177.97,354.44 J5.52@2177.8,354.61
  L08_SIG3 w4.5: v1(885.86,698.68) 909.73,698.68 931.48,698.68 cw(c931.48,692.83) 937.33,692.83 937.33,689.53 ccw(c943.18,689.53) 943.18,683.68 950.98,683.68 ccw(c950.98,689.53) 956.83,689.53 956.83,706.76 cw(c962.68,706.76) 962.68,712.61 970.48,712.61 cw(c970.48,706.76) 976.33,706.76 976.33,689.53 ccw(c982.18,689.53) 982.18,683.68 989.98,683.68 ccw(c989.98,689.53) 995.83,689.53 995.83,705.31 cw(c1001.68,705.31) 1001.68,711.16 1009.48,711.16 cw(c1009.48,705.31) 1015.33,705.31 1015.33,692.83 ccw(c1021.18,692.83) 1021.18,686.98 1028.98,686.98 ccw(c1028.98,692.83) 1034.83,692.83 cw(c1040.68,692.83) 1040.68,698.68 1076.51,698.68 1348.6,698.68 1520,527.28 1520,438.37 1559.78,398.59 1650.41,398.59 1714,335 1808.59,335 1855.06,288.54 v1(1855.06,275.1)
  Bottom Layer w5.66: R82.1@852.26,697.3 v1@885.86,697.3
DLT_GPIO76: J5.40 R92.1 | length 4316.3
  Top Layer w5.66: v1(2116.7,688.87) 2116.7,480.71 2124.33,473.08 2177.44,473.08 J5.40@2177.8,472.72
  L08_SIG3 w4.5: v1@908,1464 908,1487.6 905.75,1489.85 905.75,1504.15 978.85,1577.25 1071.3,1577.25 1166.55,1482 1305,1482 1327,1460 1653.72,1460 1729,1535.28 1928.56,1535.28 1961.63,1502.21 1961.63,1399.37 1982.18,1378.82 2049.18,1378.82 cw(c2049.18,1344) 2084,1344 2084,826 ccw(c2110,826) 2110,800 ccw(c2110,824) 2134,824 2134,866 ccw(c2115,866) 2115,885 cw(c2115,892) 2108,892 2108,1222 cw(c2120,1222) 2120,1234 2124,1234 cw(c2124,1222) 2136,1222 2136,1033 ccw(c2148,1033) 2148,1021 2157,1021 ccw(c2157,1032) 2168,1032 2168,1221 cw(c2181,1221) 2181,1234 2185,1234 cw(c2185,1222) 2197,1222 2197,1044.77 2225.01,1016.76 2225.01,838.01 2167,780 2167,696.86 2159.01,688.87 v1(2116.7,688.87)
  Bottom Layer w5.66: R92.1@700.54,1186.98 686.22,1201.3 686.22,1267.22 752,1333 859.22,1333 908,1381.78 v1(908,1462) v1@908,1464
ECAT_PHY0_CLK: J3.117 R31.1 R32.1 | length 3900.8
  Top Layer w5.66: R32.1@1176.57,452.5 v1@1176.57,477.5
  L08_SIG3 w4.5: v1(1176.57,478.5) 1176.57,505.97 1183.43,512.83 1183.43,537.78 1084,637.22 1084,677 1091.31,684.31 1215.69,684.31 1372,528 1444,528 1470,502 1470,453 1571,352 1670,352 1718,304 1800,304 1854,250 1930,250 2050,370 2050,557.95 1936,671.95 1936,834 1992,890 2038,890 2054,874 2054,814 2032,792 2032,682 2085,629 2182,629 2193,640 2193,766 2256,829 2256,1082.16 2218.8,1119.36 2218.8,1242.35 2256.39,1279.94 2256.39,1441.39 2280.69,1465.69 2280.69,1524.31 2280.57,1524.43 2280.57,1567.43 2269,1579 2181,1579 2126,1634 v1(2029,1634)
  Bottom Layer w5.66: J3.117@1952.59,1614.47 2009.47,1614.47 v1(2029,1634)
ECAT_PHY1_CLK: J3.119 R35.1 R97.1 | length 4050.3
  Top Layer w5.66: v1(739,381) 739,395 746.28,402.28 R35.1@746.28,423.69
  L03_SIG1 w4.5: v1(739,381) 755,365 755,329 740,314 740,140 992.45,-112.45 2166.55,-112.45 2307.62,28.62 2307.62,1648.38 2272,1684 1985.44,1684 v1(1952.59,1651.15)
  Bottom Layer w5.66: J3.119@1952.59,1634.15 v1(1952.59,1651.15)
EEPROM_I2CSCL: J1.23 J4.12 R49.1 U6.6 | length 4867
  Top Layer w5.66: U6.6@660.72,1922 662.65,1920.06 v1(709.03,1920.06) ; J4.12@1163,12.56 1163,-37.17 1193.55,-67.71 1258.76,-67.71 1292.81,-101.77 1381.04,-101.77 1381.17,-101.89 1395.94,-101.89 1396.06,-101.77 1411.29,-101.77 v1(1431.05,-82.01)
  Top Layer w6.66: R49.1@598.62,1922 U6.6@660.72,1922
  L05_SIG2 w4: v1(709.03,1920.06) 787.94,1920.06 813.35,1894.65 1719.17,1894.65 1928.82,1685 2270.44,1685 2308.5,1646.94 2308.5,9.3 2191.96,-107.25 1456.28,-107.25 v1(1431.05,-82.01)
  Bottom Layer w5.66: v1(1431.05,-82.01) 1447.7,-65.36 J1.23@1447.7,27.59
EEPROM_I2CSDA: J1.25 J4.11 R50.1 U6.5 | length 4966.6
  Top Layer w5.66: R50.1@598.62,1972 U6.5@660.72,1972 660.8,1972.08 v1(704.23,1972.08) ; J4.11@1163,207.44 1163,160 1203.2,119.8 1273.25,119.8 1293.51,99.54 1318.74,99.54 1422.48,-4.19 v1(1422.48,-44.24)
  L05_SIG2 w4: v1(704.23,1972.08) 686.38,1972.08 681.34,1967.04 681.34,1904.66 742.85,1843.15 1741.84,1843.15 1916,1669 2063,1669 2083,1649 2272.9,1649 2298.3,1623.59 2298.3,14.3 2189.43,-94.57 1472.81,-94.57 v1(1422.48,-44.24)
  Bottom Layer w5.66: v1(1422.48,-44.24) 1422.48,-40.9 1428.01,-35.37 J1.25@1428.01,27.59
EXT_VMON1: R72.1 R77.2 U2.16 | length 1336.4
  Top Layer w5.66: R72.1@773.75,1260.41 808.91,1260.41 v1@808.95,1260.45 ; U2.16@1526.84,1138.1 1526.84,1067.84 1537.86,1056.82 1576.84,1056.82 v1(1597.66,1036)
  L05_SIG2 w4: v1@808.91,1260.41 841.96,1227.36 928.37,1227.36 1006.42,1149.31 1006.42,1022.34 1053.24,975.52 1133.35,975.52 1295.83,1138 1460.25,1138 1498.97,1099.28 1498.97,1063.23 1526.2,1036 v1(1597.66,1036)
  Bottom Layer w5.66: R77.2@773.75,1260.41 v1@808.91,1260.41
  other v1: 806.91,1260.41
EXT_VMON2: R5.2 R56.2 S3.2 U1.N2 | length 3758.8
  Top Layer w5.66: S3.2@16.83,468 63.22,468 72.13,476.91 72.13,500.27 79.46,507.6 R56.2@109.99,507.6 131.43,507.6 143.17,495.85 158.14,495.85 v1(159,495) 159,663.46 -299.08,1121.53 -299.08,1258.56 41.36,1599 v1(147,1599) ; v1(239.79,690.73) U1.N2@255.53,706.48
  L05_SIG2 w4: v1(159,495) 84.73,495 52.95,526.78 52.95,681.2 76.58,704.83 111.22,704.83 142.05,674 223.05,674 v1(239.79,690.73)
  Bottom Layer w5.66: v1(147,1599) 166.06,1599 223.18,1656.11 604.99,1656.11 641.71,1692.83 923.88,1692.83 1048.47,1568.24 1048.47,1201.85 1105.31,1145 R5.2@1195.32,1145
EXT_VREFHIAB: S3.3 S3.5 | length 233.7
  Top Layer w10: S3.5@-128.83,468 -117.02,468 -86.55,437.53 -35.86,437.53 -30,443.39 -30,501.88 5.02,536.9 S3.3@16.83,536.9
EXT_VREFHICDE: S4.3 S4.5 | length 367.9
  Top Layer w10: S4.5@-167,706.9 -178.81,706.9 -217.39,745.47 -217.39,800.54 -190.61,827.32 -42.12,827.32 -21.33,806.53 S4.3@-21.33,775.8
F29H85x_25MHZ_CLK: R34.2 U1.E16 | length 510.3
  Top Layer w5.66: U1.E16@696.48,958.45 697.29,959.26 729.74,959.26 v1(744,945) ; v1(950,750) 974.94,750 R34.2@976.97,752.04
  Bottom Layer w5.66: v1(744,945) 744,929 762,911 820,911 866.93,957.93 902.07,957.93 950,910 v1(950,750)
GND: C1.1 C2.1 C3.2 C4.2 C5.2 C6.2 C7.2 C8.2 C9.2 C10.2 C11.2 C12.2 C13.2 C14.2 C15.2 C16.2 C17.2 C18.2 C19.2 C20.2 C21.2 C22.2 C23.2 C24.2 C25.2 C26.2 C27.2 C28.2 C29.2 C30.2 C31.2 C32.2 C33.2 C34.2 C35.2 C36.2 C37.2 C41.1 C42.2 C43.2 C44.2 C45.2 C46.1 C47.1 C48.2 C49.1 C50.2 C51.2 C52.1 C53.1 C54.2 C55.2 C56.2 C57.2 C58.2 C59.2 C60.2 C61.1 C62.2 C63.1 C64.2 C65.1 C66.2 C67.2 C68.2 C69.2 C70.1 C71.2 C72.1 C73.2 C74.2 C75.2 C76.2 C77.2 C78.2 C79.2 C80.1 C81.2 C82.1 C83.2 C84.2 C85.2 C86.1 C87.2 C88.2 C89.2 C90.2 C91.2 C92.1 C93.1 C96.2 C97.1 C98.1 J1.17 J1.77 J1.78 J1.121 J1.122 J1.123 J1.124 J1.125 J1.126 J1.127 J1.128 J2.121 J2.122 J2.123 J2.124 J2.125 J2.126 J2.127 J2.128 J3.121 J3.122 J3.123 J3.124 J3.125 J3.126 J3.127 J3.128 J4.2 J4.7 J5.16 J5.57 J5.58 J5.P1 J5.P2 J5.P3 J5.P4 LED1.2 LED2.2 R2.1 R8.1 R9.1 R11.1 R17.1 R18.1 R28.1 R33.1 R37.1 R44.1 R68.1 R69.2 R76.1 R77.1 R87.1 S1.1 S1.4 SW1.1 SW1.2 TP3.1 U1.A1 U1.A16 U1.E15 U1.F7 U1.F8 U1.F9 U1.F10 U1.F11 U1.G7 U1.G8 U1.G9 U1.G10 U1.G11 U1.H7 U1.H8 U1.H9 U1.H10 U1.H11 U1.J7 U1.J8 U1.J9 U1.J10 U1.J11 U1.K7 U1.K8 U1.K9 U1.K10 U1.K11 U1.L7 U1.N1 U1.T1 U1.T4 U1.T16 U2.1 U2.2 U2.12 U2.14 U2.47 U2.48 U2.49 U3.5 U4.4 U5.4 U6.1 U6.2 U6.3 U6.4 U7.4 U8.4 Y1.2 | length 14272
  Top Layer w5.66: v1(207.31,593.91) 207.31,595.27 U1.T1@224.04,611.99 ; v1(208.29,690.73) U1.N1@224.04,706.48 ; v1(208.29,1100.18) U1.A1@224.04,1084.43 ; v1(313.05,589.94) 313.05,606.51 U1.T4@318.53,611.99 ; v1(397.27,753.72) U1.L7@413.01,769.47 ; v1(397.27,785.22) U1.K7@413.01,800.97 ; v1(397.27,879.71) U1.H7@413.01,863.96 ; v1(397.27,911.2) U1.G7@413.01,895.46 ; v1(397.27,942.7) U1.F7@413.01,926.95 ; U1.J7@413.01,832.46 v1(428.76,816.72) U1.J8@444.51,832.46 ; v1(428.76,785.22) U1.K8@444.51,800.97 ; v1(428.76,879.71) U1.H8@444.51,863.96 ; v1(428.76,911.2) U1.G8@444.51,895.46 ; v1(428.76,942.7) U1.F8@444.51,926.95 ; U1.K9@476.01,800.97 v1(491.75,785.22) ; U1.J9@476.01,832.46 v1(491.75,816.72) ; U1.H9@476.01,863.96 v1(491.75,879.71) ; U1.G9@476.01,895.46 v1(491.75,911.2) ; U1.F9@476.01,926.95 v1(491.75,942.7) ; U1.K10@507.5,800.97 v1(523.25,785.22) ; U1.J10@507.5,832.46 v1(523.25,816.72) ; U1.H10@507.5,863.96 v1(523.25,879.71) ; U1.G10@507.5,895.46 v1(523.25,911.2) ; U1.F10@507.5,926.95 v1(523.25,942.7) ; U1.K11@539,800.97 v1(554.75,785.22) ; U1.J11@539,832.46 v1(554.75,816.72) ; U1.H11@539,863.96 v1(554.75,879.71) ; U1.G11@539,895.46 v1(554.75,911.2) ; U1.F11@539,926.95 v1(554.75,942.7) ; U1.E15@664.98,958.45 v1(680.73,974.2) ; U1.T16@696.48,611.99 v1(712.23,596.24) ; U1.A16@696.48,1084.43 v1(712.23,1100.18)
  Top Layer w10: C82.1@50,591.3 52.42,593.72 69.25,593.72 82.52,607 82.52,610.42 v1(84.06,611.95) 108.86,611.95 109.75,612.84 ; U8.4@63.39,265.2 80.57,265.2 99.44,284.07 v1(99.44,284.6) ; 70.57,311.35 74.51,311.35 99.44,286.41 v1(99.44,284.6) ; C85.2@124.28,261.71 124.28,265.65 117.47,272.46 113.53,272.46 101.39,284.6 v1(99.44,284.6) ; v1(148.98,119.5) 150.51,121.03 165.17,121.03 173.62,129.47 C84.2@173.62,155 ; v1(180.23,1814.12) 216.96,1814.12 SW1.2@217.17,1814.33 ; v1(180.44,1650.94) SW1.1@217.17,1650.94 ; v1(290.53,508.37) 326.88,508.37 C3.2@333,502.25 ; v1@333.19,470.53 C3.2@333.19,502.06 ; C1.1@432.79,1452.06 C1.1@434.05,1453.32 ; C1.1@436.76,1450.62 439.38,1453.24 439.38,1476.38 v1(440.91,1477.91) ; C92.1@490.16,473.61 496.97,466.8 496.97,452.68 v1@500.04,449.61 ; v1(509.25,1822) C77.2@551.38,1822 ; v1(509.25,1872) R69.2@551.38,1872 ; v1(523.54,436.97) 523.54,439.13 531.16,446.74 C24.2@531.16,472.61 ; v1@564.54,436.97 564.54,439.13 572.16,446.74 C25.2@572.16,472.61 ; U7.4@747.4,1432.11 747.4,1401.34 753.26,1395.49 v1(778.23,1395.49) ; R28.1@765,1603.62 v1(765,1635.21) ; v1@769.76,645.05 C4.2@805.01,645.05 ; C68.2@802,1333 778.23,1356.77 v1(778.23,1395.49) ; C66.2@840,1403.5 831.98,1395.49 v1(778.23,1395.49) ; C18.2@852.26,831.3 v1@887.51,831.3 ; C16.2@852.26,872.3 v1@887.51,872.3 ; v1@1025.4,327.26 C74.2@1025.4,360.19 C74.2@1025.4,362.19 ; C75.2@1099.77,845.81 1099.77,868.29 1101.75,868.29 1107.6,874.15 v1(1109.77,874.15) ; R33.1@1136.26,530.38 v1(1169.18,530.38) ; U2.49@1226.2,1367.26 1231.56,1372.62 U2.48@1231.56,1433.38 ; U2.1@1231.56,1138.1 U2.49@1231.56,1198.86 ; U2.2@1251.25,1138.1 U2.49@1251.25,1198.86 ; U2.49@1251.25,1372.62 U2.47@1251.25,1433.38 ; U2.12@1448.1,1138.1 U2.49@1448.1,1198.86 ; U2.14@1487.47,1138.1 U2.49@1487.47,1198.86 ; C46.1@1566.62,696.52 v1(1593.48,696.52) ; C47.1@1571.54,800.36 1598.4,800.36 ; v1(1620.79,1637.88) 1720.57,1637.88 1791.23,1567.21 1791.23,1546.69 R11.1@1792.93,1545 ; v1(1665.62,975) C67.2@1665.62,1001 ; C71.2@1715,934.25 v1(1744.25,934.25) ; v1(1821.91,661.1) 1849.02,661.1 R87.1@1849.55,660.56 ; v1(1936.77,64.55) 1937.81,63.51 1937.81,27.91 LED1.2@1938.84,26.88
  Top Layer w12: C98.1@708.91,1603.62 v1(708.91,1635.21) ; 2029.83,1382.2 2043.28,1382.2 ; v1@2041.38,1361.5 v1(2042.5,1360.38) 2042.5,1381.42 2043.28,1382.2 ; LED2.2@2154.84,34 v1(2185.52,34) ; S1.1@2155.81,1382.2 S1.1@2144,1382.2 2043.28,1382.2
  Top Layer w15: v1(-346.54,722.21) -346.41,722.08 C83.2@-346.41,687.26 ; v1(-297.57,242.69) v1@-296.76,242.69 ; U4.4@-269.23,380.4 -269.23,370.68 -239.12,370.68 -206,337.56 C87.2@-206,333.62 -185.62,333.62 -167,315 -167,302.69 v1(-146.01,281.7) ; v1(11,896) 11,872.66 60.37,823.29 C19.2@95.1,823.29 C21.2@144.93,823.29 ; C80.1@153.43,422.44 C80.1@156.09,422.44 156.24,422.44 157.6,421.08 157.6,398.62 v1(158.17,398.04) ; C9.2@415.01,1167.8 C6.2@415.01,1208.8 415.62,1208.8 419.94,1213.11 C2.1@419.94,1254.3 ; C25.2@572.16,472.61 C76.2@613.14,472.62 ; v1(789.25,1286.87) 789.25,1320.25 C68.2@799,1330 ; v1(815,163) 851.41,163 862.39,173.98 866.33,173.98 870.64,178.29 R44.1@870.64,182.23 ; v1(951.38,596.38) U5.4@951.38,646.36 ; Y1.2@994.52,859.53 Y1.2@994.52,863.73 994.52,864.45 1007.95,877.88 1007.95,908.99 1011.15,912.19 R37.1@1011.15,916.39 v1(1011.15,938.85) ; R2.1@1262.38,346 1262.38,371.33 v1(1276.6,385.55) ; v1(1315,140) 1315,193 1323.79,201.79 1357.35,201.79 J4.7@1363,207.44 ; v1(1615,140) 1615,108 1663,60 J4.2@1663,12.56 ; J5.P4@2065,243.78 v1(2065,330.61) J5.P3@2065,436.3 v1(2065,581.43) J5.P2@2065,686.3 v1(2065,782.56) J5.P1@2065,878.82
  Top Layer w18: v1(936.95,1972) v1@937,1971.95
  Top Layer w20: U6.1@875.28,1822 v1(936.95,1822) ; U6.2@875.28,1872 v1(936.95,1872) ; U6.3@875.28,1922 v1(936.95,1922) ; U6.4@875.28,1972 v1(936.95,1972) ; v1(1534.05,1020.95) 1534.05,998.81 1535.86,997 C64.2@1539.75,997
  L03_SIG1 w4.5: -385,345 -387.5,342.5 -387.5,-125 -380,-132.5 2257.5,-132.5 2310,-80
  L08_SIG3 w4.5: -387.24,649.9 -387.24,381 -374.36,368.12 v1(-374.36,323.85)
  Bottom Layer w5.66: v2(1221.72,1199.13) 1221.72,1196.56 1222.83,1195.44 v2@1222.83,1197.8
  Bottom Layer w10: v1@-152.32,365 -102.97,365 J2.127@-100,367.97 ; C14.2@318,506.17 322.46,501.71 322.46,483.71 v1@333.19,472.97 ; C81.2@460.26,673.47 460.26,578.23 460.53,577.96 460.53,480.43 464.44,476.52 486.25,476.52 C22.2@490.16,472.61 496.97,465.8 496.97,451.68 501.57,447.07 v1(501.57,444.91) ; v1(523.54,436.97) 523.54,439.13 531.16,446.74 C23.2@531.16,472.61 ; v1@564.54,436.97 564.54,439.13 572.16,446.74 C20.2@572.16,472.61 ; v1@565.03,437.26 v1(565.13,437.16) ; v1@699.03,320.3 v1(700.81,320.3) 711.69,320.3 719.23,312.75 J1.78@719.23,253.19 ; J1.77@719.23,27.59 719.54,27.9 719.54,99.11 v1(719.85,99.42) ; R76.1@753.23,1395.49 v1(778.23,1395.49) ; v1@769.1,505.79 C5.2@804.35,505.79 ; C17.2@852.26,831.3 v1@887.51,831.3 ; C26.2@852.26,872.3 v1@887.51,872.3 ; R68.1@1423.62,775 1430,781.38 v1(1430,800) ; J1.17@1506.75,27.59 v1(1506.84,82.74) ; R18.1@1571.5,746.42 1571.5,718.5 v1(1593.48,696.52) ; C49.1@1660.7,1001 1660.7,982.08 1665.62,977.16 v1(1665.62,975) ; C72.1@1715,939.3 1737.04,939.3 1742.09,934.25 v1(1744.25,934.25)
  Bottom Layer w15: J2.127@-100.96,351.28 J2.127@-100,352.24 ; J2.128@-100,243.78 J2.127@-100,352.24 ; J2.125@-100,878.82 v1(-100,803.86) J2.126@-100,686.3 v1(-100,574.3) J2.127@-100,436.3 -100,367.97 J2.127@-100,352.24 ; J2.124@-100,1031.18 v1(-100,1106.95) J2.123@-100,1223.7 v1(-100,1348.7) J2.122@-100,1473.7 v1(-100,1593.37) J2.121@-100,1666.22 ; v1(11,896) 31.6,875.4 66.62,875.4 118.72,823.29 C93.1@144.93,823.29 171.29,823.29 196.21,848.21 C13.2@271.51,848.21 ; J1.128@273.78,140 v1(348.37,140) J1.127@466.3,140 v1(591.3,140) J1.126@716.3,140 800.35,140 814.43,154.07 814.43,162.43 v1(815,163) ; v1(380.05,1270.88) 380.63,1270.31 389.08,1270.31 v1(401.27,1258.13) 401.27,1257.32 404.83,1253.75 404.83,1240.11 409.15,1235.8 C7.2@413.01,1235.8 C8.2@413.01,1194.8 C15.2@413.01,1153.8 ; C20.2@572.16,472.61 C27.2@613.12,472.62 ; C88.2@648.45,848.14 717.86,848.14 754.79,811.21 754.79,802.3 v1(755.36,801.72) ; R77.1@726.51,1260.41 726.51,1278.51 734.89,1286.89 v1(789.25,1286.87) ; J1.125@908.82,140 J1.124@1061.18,140 v1(1115,140) J1.123@1253.7,140 v1(1315,140) J1.122@1503.7,140 v1(1615,140) J1.121@1696.22,140 ; v1(1276.6,385.55) 1287.97,374.18 C53.1@1287.97,355.4 ; v2(1316.21,1372.35) 1316.68,1372.83 1349.53,1372.83 C42.2@1350,1373.3 ; v2(1363.45,1199.13) 1363.45,1165.21 R8.1@1377.92,1150.74 ; C41.1@1400,1367.76 1403.7,1371.46 1457.04,1371.46 v2(1457.94,1372.35) ; J3.121@2065,243.78 v1(2065,330.61) J3.122@2065,436.3 v1(2065,581.43) J3.123@2065,686.3 v1(2065,782.56) J3.124@2065,878.82 J3.125@2065,1031.18 v1(2065,1095.23) J3.126@2065,1223.7 v1(2065,1319.96) J3.127@2065,1473.7 v1(2065.48,1582.68) J3.128@2065.48,1678.94
  Bottom Layer w20: C14.2@322.46,501.71 339.81,501.71 345.52,496 357.07,496 365.77,487.3 C96.2@365.77,486.31 ; C97.1@663.48,1087.04 699.09,1087.04 v1(712.23,1100.18)
  other v1: 415,-105 -370,-93.51 -150,-93.51 150,-93.51 705,-93.51 2277.52,-93.51 2045,-55 438.49,-35.97 -235,-21 306.91,90.56 580,110 373.81,128.36 2277.3,149.86 2026.19,165.48 -42.67,188.31 8.92,240.11 -73,317 1025.56,327.1 461.93,356.95 -153.32,365 289.3,370.95 343.24,371.53 1605.59,372.4 545.73,388.65 76.09,393.34 626,397 394.37,422.47 1604.69,421.52 -339.37,453.54 333.39,470.53 1604.69,471.94 768.9,505.6 -337.61,513.04 1604.69,522.36 -76.47,531.83 2268.02,624.93 769.57,645.25 1166,725 1166,797.5 1608.4,800.36 1495,830 887.7,831.1 -345,850 1495,867.91 1166,870 887.7,872.1 -165,885 -30,910 1446.33,925 -346.47,972.15 1446.33,975 1446.33,1000.79 -130,1010 -65,1030 2272.93,1382.3 -297,1535 1521.26,1636.97 1571.68,1636.97 1435.68,1637.82 1435.59,1671.08 1103.01,1764.5 1153.43,1764.5 1202.54,1765.4 -350,1810 2240,1875 1270,1928 1520,1928 -225,1935 1145,2053 1395,2053 1645,2053 -350,2060 -100,2060 150,2060 650,2060 900,2060 1895,2060 2145,2060
  other v2: 1268.96,1199.13 1316.21,1199.13 1410.7,1199.13 1457.94,1199.13 1505.18,1199.13 1552.43,1199.13 1599.67,1199.13 1646.92,1199.13 1694.16,1199.13 1221.72,1242.43 1268.96,1242.43 1316.21,1242.43 1363.45,1242.43 1410.7,1242.43 1457.94,1242.43 1505.18,1242.43 1552.43,1242.43 1599.67,1242.43 1646.92,1242.43 1694.16,1242.43 1221.72,1285.74 1268.96,1285.74 1316.21,1285.74 1363.45,1285.74 1410.7,1285.74 1457.94,1285.74 1505.18,1285.74 1552.43,1285.74 1599.67,1285.74 1646.92,1285.74 1694.16,1285.74 1221.72,1329.05 1268.96,1329.05 1316.21,1329.05 1363.45,1329.05 1410.7,1329.05 1457.94,1329.05 1505.18,1329.05 1552.43,1329.05 1599.67,1329.05 1646.92,1329.05 1694.16,1329.05 1221.72,1372.35 1268.96,1372.35 1505.18,1372.35 1552.43,1372.35 1599.67,1372.35 1646.92,1372.35 1694.16,1372.35
INT_VREFHIAB: S3.1
INT_VREFHICDE: S4.1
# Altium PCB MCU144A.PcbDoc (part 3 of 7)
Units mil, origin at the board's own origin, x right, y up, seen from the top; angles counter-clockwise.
Board outline 2755.9 x 2276.49 mil, 10 copper layers (Top Layer, L02_GND1, L03_SIG1, L04_GND2, L05_SIG2, L06_PWR, L07_GND3, L08_SIG3, L09_GND4, Bottom Layer), stack 60.4 mil thick; 253 components, 312 nets, 1289 pads, 832 vias.

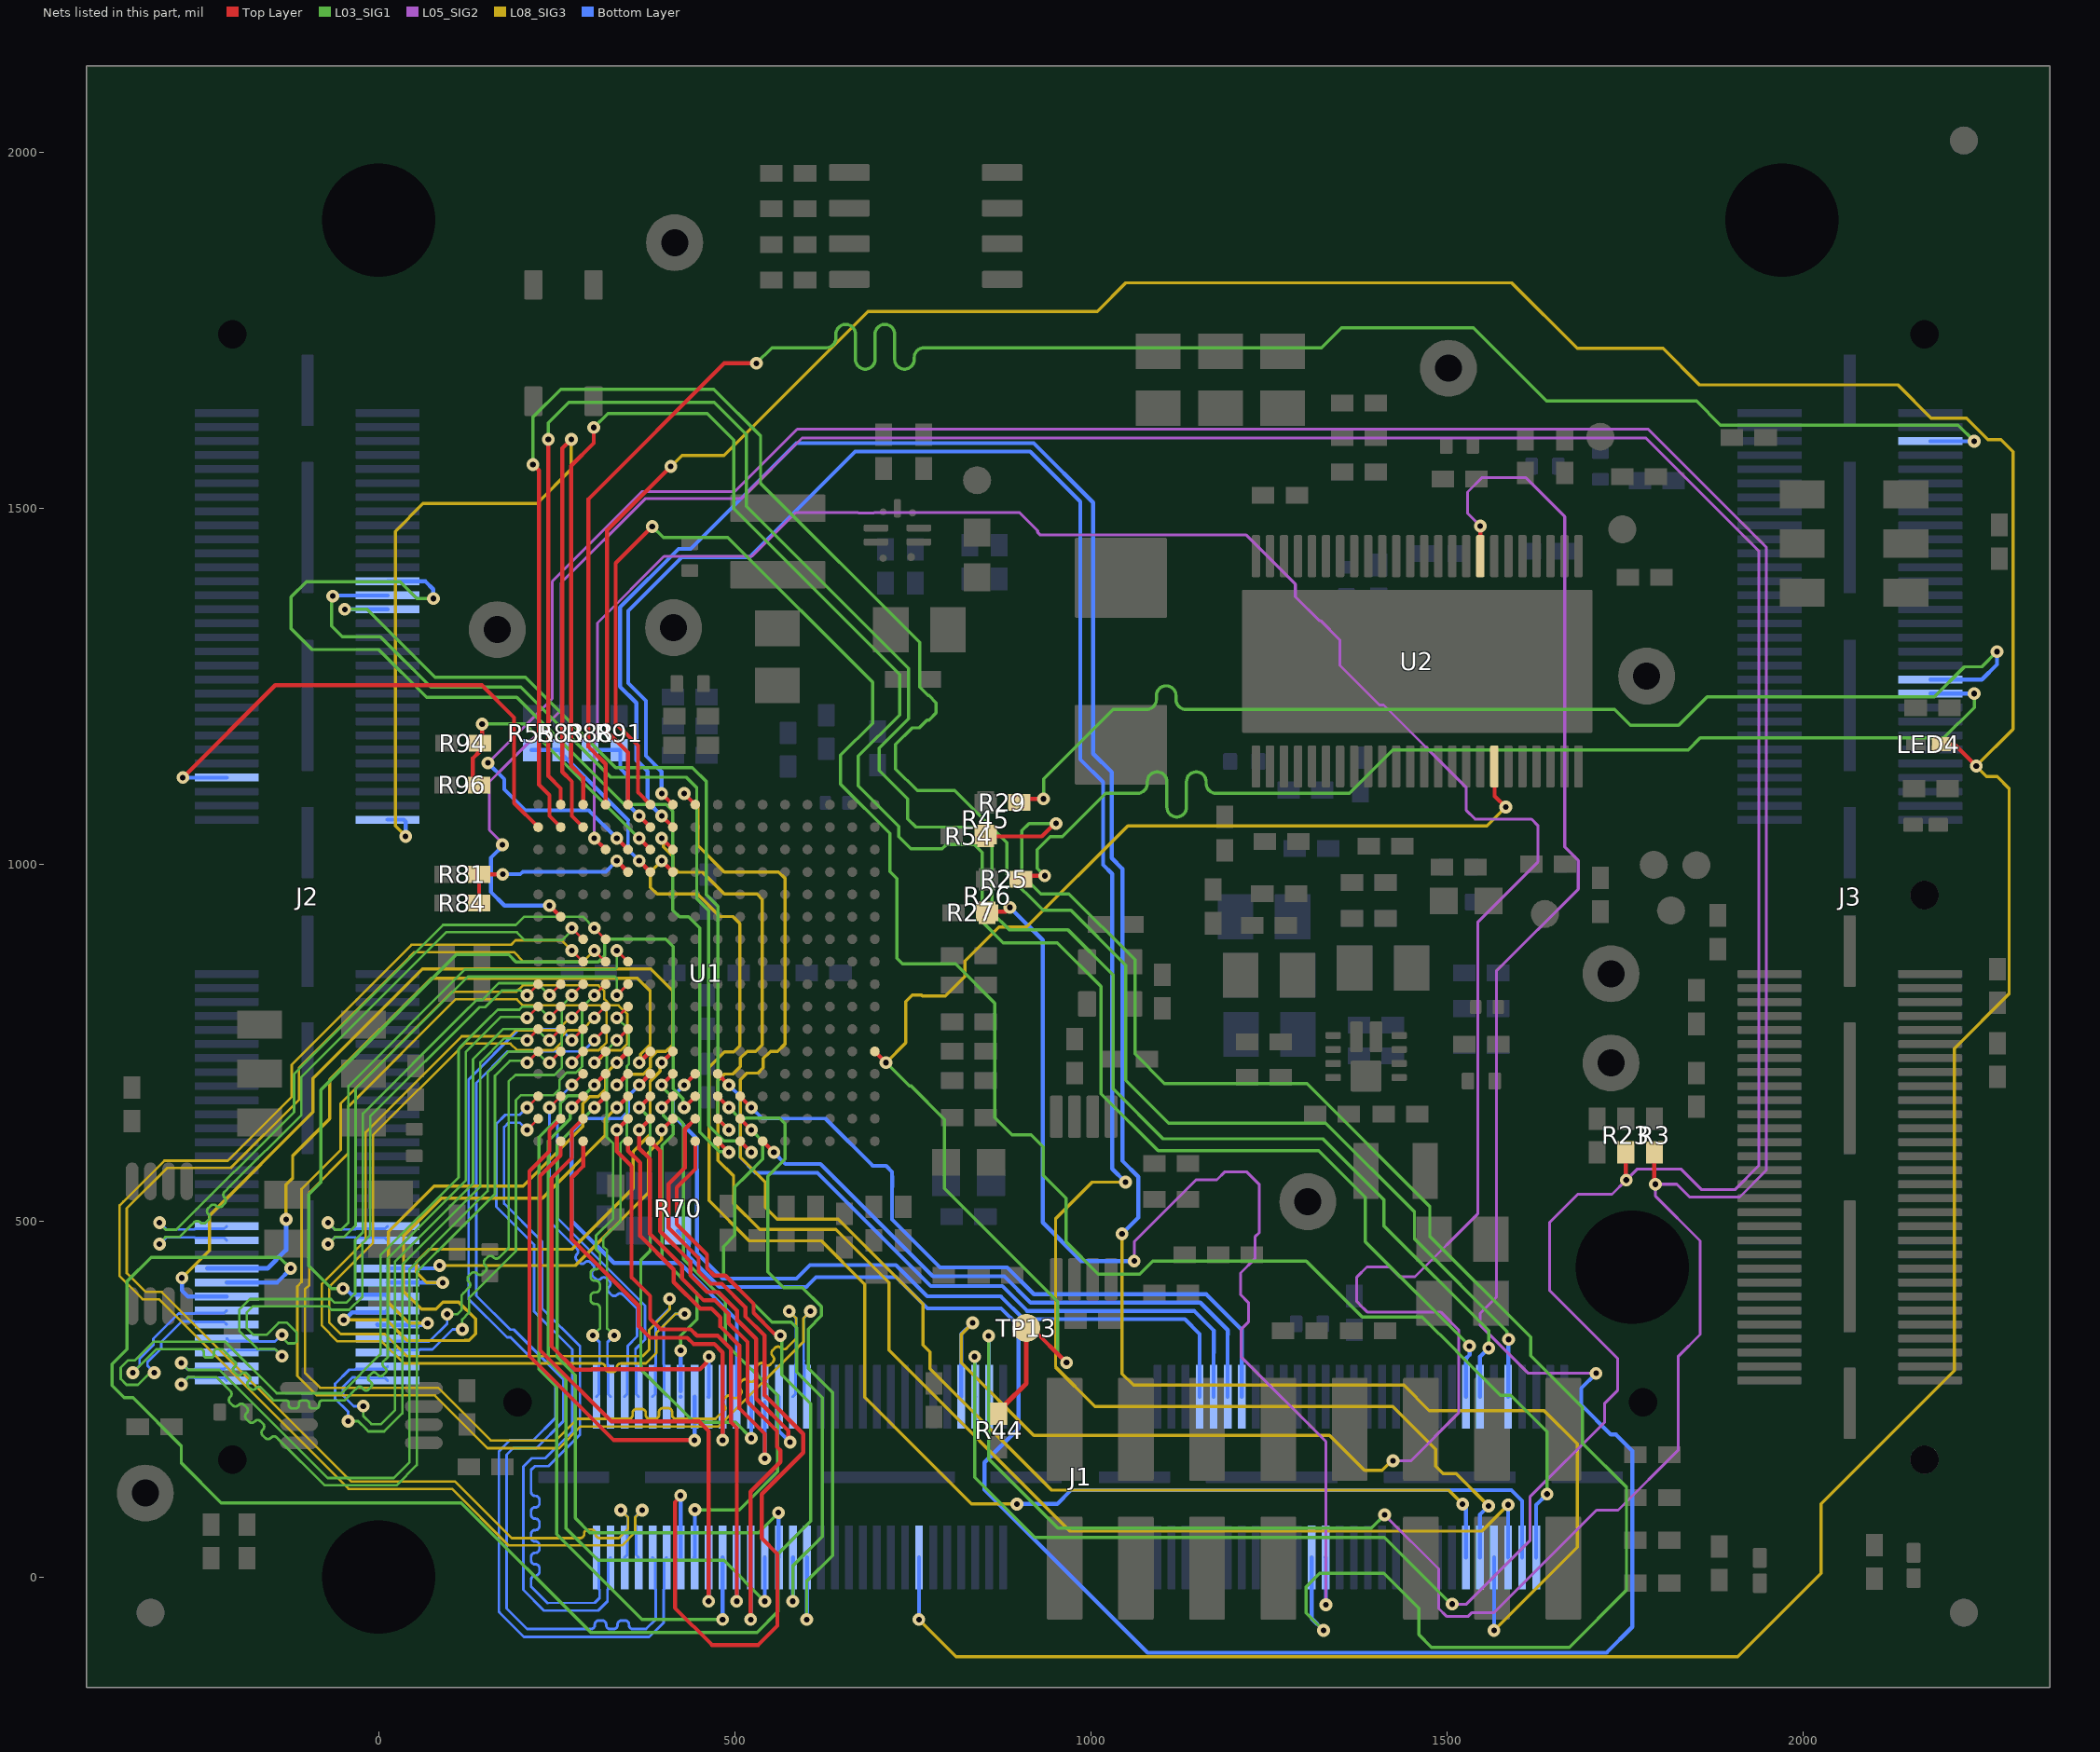
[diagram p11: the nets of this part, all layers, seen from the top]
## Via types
v1: diameter 18, hole 8, Top Layer to Bottom Layer, tented both sides, 776 vias
v2: diameter 19.68, hole 7.87, Top Layer to Bottom Layer, tented top, 54 vias
v3: diameter 18/18/18/18/18/18/18/18/18/18 (per signal layer), hole 8, Top Layer to Bottom Layer, tented both sides, 2 vias

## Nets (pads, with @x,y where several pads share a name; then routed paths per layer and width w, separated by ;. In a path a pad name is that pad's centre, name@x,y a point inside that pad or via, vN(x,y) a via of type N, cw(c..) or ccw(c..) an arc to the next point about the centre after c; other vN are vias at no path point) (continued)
MCU_ADCIN_A0A1_N: J1.117 U1.P1 | length 1011.9
  Top Layer w3.7: v1(208.29,659.24) U1.P1@224.04,674.98
  Bottom Layer w3.7: v1(208.29,659.24) 198.04,648.99 177.93,648.99 165.12,636.18 165.12,519.86 218.39,466.59 218.39,372.84 271.66,319.57 271.66,204.56 233.9,166.79 214.79,166.79 203.02,155.03 203.02,-18.02 232,-47 308.24,-47 321.19,-34.05 321.19,-17.75 322.03,-16.91 322.03,24.09 J1.117@325.53,27.59
MCU_ADCIN_A0A1_P: J1.119 U1.R1 | length 1013
  Top Layer w3.7: v1(208.29,627.74) U1.R1@224.04,643.49
  Bottom Layer w3.7: v1(208.29,627.74) 198.04,637.99 182.49,637.99 176.12,631.62 176.12,524.42 226.17,474.37 229.39,471.15 229.39,377.4 282.66,324.13 282.66,200 238.45,155.79 219.34,155.79 214.02,150.47 214.02,121.95 214.02,119.55 ccw(c219.62,119.55) 219.62,113.95 220.17,113.95 cw(c220.17,108.35) 225.77,108.35 225.77,103.55 cw(c220.17,103.55) 220.17,97.95 219.62,97.95 ccw(c219.62,92.35) 214.02,92.35 214.02,87.55 ccw(c219.62,87.55) 219.62,81.95 220.17,81.95 cw(c220.17,76.35) 225.77,76.35 225.77,71.55 cw(c220.17,71.55) 220.17,65.95 219.62,65.95 ccw(c219.62,60.35) 214.02,60.35 214.02,55.55 ccw(c219.62,55.55) 219.62,49.95 220.17,49.95 cw(c220.17,44.35) 225.77,44.35 225.77,39.55 cw(c220.17,39.55) 220.17,33.95 219.62,33.95 ccw(c219.62,28.35) 214.02,28.35 214.02,23.55 ccw(c219.62,23.55) 219.62,17.95 220.17,17.95 cw(c220.17,12.35) 225.77,12.35 225.77,7.55 cw(c220.17,7.55) 220.17,1.95 219.62,1.95 ccw(c219.62,-3.65) 214.02,-3.65 214.02,-13.46 237.14,-36.59 303.68,-36 310.19,-29.49 310.19,-17.75 309.35,-16.91 309.35,24.09 J1.119@305.85,27.59
MCU_ADCIN_A2A3_N: J2.118 U1.M2 | length 1186.4
  Top Layer w3.7: v1(239.79,722.23) U1.M2@255.53,737.98
  L03_SIG1 w3.5: v1(-277.07,300.69) -267.17,290.79 -223.39,290.79 -71.6,139 21,139 43.42,161.42 43.42,432.42 105.99,494.99 153,542 153,708.05 159.9,714.95 182.99,738.03 221.11,738.03 236.92,722.23 v1(239.79,722.23)
  Bottom Layer w3.7: v1(-277.07,300.69) -267.57,291.19 -258.53,291.19 -257.69,292.03 -216.69,292.03 J2.118@-213.19,295.53
MCU_ADCIN_A2A3_P: J2.120 U1.M1 | length 1191
  Top Layer w3.7: v1(208.29,722.23) U1.M1@224.04,737.98
  L03_SIG1 w3.5: v1(-277.07,270.69) -267.17,280.59 -227.61,280.59 -221.3,274.28 -215.58,268.55 -208.13,261.11 cw(c-212.14,257.1) -208.13,253.09 -208.6,252.62 ccw(c-204.59,248.61) -208.6,244.6 -205.16,241.17 ccw(c-201.15,245.18) -197.14,241.17 -196.68,241.63 cw(c-192.67,237.62) -188.66,241.63 -185.22,238.2 cw(c-189.23,234.19) -185.22,230.18 -185.69,229.71 ccw(c-181.68,225.7) -185.69,221.69 -182.25,218.26 ccw(c-178.24,222.27) -174.23,218.26 -173.77,218.72 cw(c-169.76,214.71) -165.75,218.72 -162.31,215.29 cw(c-166.32,211.28) -162.31,207.27 -162.78,206.8 ccw(c-158.77,202.79) -162.78,198.78 -159.34,195.35 ccw(c-155.33,199.35) -151.32,195.35 -150.86,195.81 cw(c-146.85,191.8) -142.84,195.81 -140.01,192.99 -75.82,128.8 25.22,128.8 53.62,157.19 53.62,428.19 110.21,484.79 163.2,537.77 163.2,703.82 184.24,724.87 205.65,724.87 v1(208.29,722.23)
  Bottom Layer w3.7: v1(-277.07,270.69) -267.57,280.19 -258.53,280.19 -257.69,279.35 -216.69,279.35 J2.120@-213.19,275.85
MCU_ADCIN_A4A5_N: J2.117 U1.L1 | length 873.2
  Top Layer w3.7: v1(208.29,753.72) U1.L1@224.04,769.47
  L03_SIG1 w3.5: v1(-42.78,218.79) -28.78,218.79 -17.5,207.5 -14.51,204.52 7.69,204.52 33.22,230.04 33.22,438.79 105.92,511.5 142.8,548.38 142.8,722.8 176.36,756.36 v1@205.65,756.36
  Bottom Layer w3.7: v1(-42.78,218.79) -42.78,232.22 -61,250.44 -61,271.41 -41.22,291.19 -32.93,291.19 -32.09,292.03 8.91,292.03 J2.117@12.41,295.53
MCU_ADCIN_A4A5_P: J2.119 U1.L2 | length 876.4
  Top Layer w3.7: v1(239.79,753.72) U1.L2@255.53,769.47
  L03_SIG1 w3.5: v1(-21.57,240) -21.57,226 -10.28,214.72 3.46,214.72 23.02,234.27 23.02,443.02 101.7,521.7 132.6,552.6 132.6,727.02 159.9,754.33 174.99,769.42 221.22,769.42 v1@236.92,753.72
  Bottom Layer w3.7: v1(-21.57,240) -35,240 -50,255 -50,266.86 -36.67,280.19 -32.93,280.19 -32.09,279.35 8.91,279.35 J2.119@12.41,275.85
MCU_ADCIN_A6A7_N: J1.118 U1.K5 | length 588.4
  Top Layer w3.7: v1(334.27,785.22) U1.K5@350.02,800.97
  L03_SIG1 w3.5: v1(330.69,339.18) 320.79,349.08 320.79,458.69 315.32,464.16 315.32,475.32 339.37,499.37 339.37,608.59 348.37,617.59 348.37,717.37 351.37,720.37 351.37,768.12 v1(334.27,785.22)
  Bottom Layer w3.7: J1.118@325.53,253.19 322.03,256.69 322.03,297.69 321.19,298.53 321.19,305.19 321.19,329.68 v1(330.69,339.18)
MCU_ADCIN_A6A7_P: J1.120 U1.L5 | length 587
  Top Layer w3.7: v1(334.27,753.72) U1.L5@350.02,769.47
  L03_SIG1 w3.5: v1(300.69,339.18) 310.59,349.08 310.59,375.45 310.59,377.88 ccw(c304.92,377.88) 304.92,383.55 303.26,383.55 cw(c303.26,389.22) 297.59,389.22 297.59,394.08 cw(c303.26,394.08) 303.26,399.75 304.92,399.75 ccw(c304.92,405.42) 310.59,405.42 310.59,410.28 ccw(c304.92,410.28) 304.92,415.95 303.26,415.95 cw(c303.26,421.62) 297.59,421.62 297.59,426.48 cw(c303.26,426.48) 303.26,432.15 304.92,432.15 ccw(c304.92,437.82) 310.59,437.82 310.59,446.2 310.59,454.46 305.12,459.93 305.12,479.54 329.17,503.6 329.17,608.59 320.17,617.59 320.17,739.62 v1(334.27,753.72)
  Bottom Layer w3.7: v1(300.69,339.18) 310.19,329.68 310.19,309.75 310.19,298.53 309.35,297.69 309.35,256.69 J1.120@305.85,253.19
MCU_ADCIN_A8A9_N: J1.113 U1.H3 | length 1938.1
  Top Layer w3.7: v1(271.28,879.71) U1.H3@287.03,863.96
  L08_SIG3 w3.5: v1(271.28,879.71) 256.89,894.1 192.3,894.1 185.82,887.63 46.2,887.63 -122,719.42 -122,674.43 -211.81,584.61 -300.81,584.61 -358.22,527.2 -363.67,521.76 -363.67,422.44 -331.22,390 -308.59,390 -42.36,123.77 103.23,123.77 182.55,44.45 341.58,44.45 360.16,63.03 360.16,83.96 v1(370.06,93.86)
  Bottom Layer w3.7: J1.113@364.9,27.59 361.4,31.09 361.4,72.09 360.56,72.93 360.56,84.36 v1(370.06,93.86)
MCU_ADCIN_A8A9_P: J1.115 U1.H4 | length 1936.6
  Top Layer w3.7: v1(302.78,879.71) U1.H4@318.53,863.96
  L08_SIG3 w3.5: v1(302.78,879.71) 287.08,864.01 203.46,864.01 190.04,877.43 50.43,877.43 34.96,861.96 -111.8,715.2 -111.8,670.2 -207.59,574.41 -296.59,574.41 -353.47,517.53 -353.47,426.67 -327,400.2 -304.36,400.2 -38.13,133.97 107.45,133.97 119.4,122.03 186.77,54.65 262.06,54.65 272.21,54.65 282.74,54.65 ccw(c282.74,60.32) 288.41,60.32 288.41,60.98 cw(c294.08,60.98) 294.08,66.65 298.94,66.65 cw(c298.94,60.98) 304.61,60.98 304.61,60.32 ccw(c310.28,60.32) 310.28,54.65 320.81,54.65 328.91,54.65 337.35,54.65 349.96,67.26 349.96,83.96 v1(340.06,93.86)
  Bottom Layer w3.7: v1(340.06,93.86) 349.56,84.36 349.56,72.93 348.72,72.09 348.72,31.09 J1.115@345.22,27.59
MCU_ADCIN_A10A11_N: J2.98 U1.G4 | length 957.8
  Top Layer w3.7: v1(302.78,911.2) U1.G4@318.53,895.46
  L03_SIG1 w3.5: v1(-307.61,497.54) -307.61,495.9 -299.35,487.64 -283.93,487.64 -118.66,652.9 -118.66,706.34 90.52,915.53 159.9,915.53 192.63,915.53 204.18,927.08 286.9,927.08 v1(302.78,911.2)
  Bottom Layer w3.7: v1(-307.61,497.54) -298.11,488.04 -265.19,488.04 -258.53,488.04 -257.69,488.88 -216.69,488.88 J2.98@-213.19,492.38
MCU_ADCIN_A10A11_P: J2.100 U1.G3 | length 960.5
  Top Layer w3.7: v1(271.28,911.2) U1.G3@287.03,895.46
  L03_SIG1 w3.5: v1(-307.61,467.54) -307.61,469.18 -299.35,477.44 -279.7,477.44 -271.97,485.17 -266.24,490.9 -258.8,498.35 cw(c-254.79,494.34) -250.78,498.35 -250.45,498.02 ccw(c-246.44,502.03) -242.43,498.02 -239,501.46 ccw(c-243.01,505.47) -239,509.48 -239.32,509.8 cw(c-235.31,513.81) -239.32,517.82 -235.89,521.26 cw(c-231.88,517.25) -227.87,521.26 -227.54,520.93 ccw(c-223.53,524.94) -219.52,520.93 -216.09,524.37 ccw(c-220.1,528.38) -216.09,532.39 -216.41,532.71 cw(c-212.4,536.72) -216.41,540.73 -208.07,549.07 -108.46,648.68 -108.46,702.12 94.74,905.33 159.9,905.33 193.9,905.33 204.94,894.29 257.51,894.29 274.42,911.2 v1(271.28,911.2)
  Bottom Layer w3.7: v1(-307.61,467.54) -298.11,477.04 -269.75,477.04 -258.53,477.04 -257.69,476.2 -216.69,476.2 J2.100@-213.19,472.7
MCU_ADCIN_A12A13_N: J2.110 U1.K1 | length 1321.3
  Top Layer w3.7: v1(208.29,785.22) U1.K1@224.04,800.97
  L03_SIG1 w3.5: v1(-345,287) -312,320 -278.92,320 -266.81,320 -259.71,320 -249.77,320 cw(c-249.77,315.74) -245.51,315.74 -245.51,312.26 ccw(c-241.25,312.26) -241.25,308 -235.57,308 ccw(c-235.57,312.26) -231.31,312.26 -231.31,315.74 cw(c-227.05,315.74) -227.05,320 -219.42,320 -213.57,314.15 -208.55,309.13 -201.52,302.1 cw(c-204.54,299.09) -201.52,296.07 -203.28,294.32 ccw(c-200.27,291.31) -203.28,288.3 -199.26,284.28 ccw(c-196.25,287.29) -193.24,284.28 -191.48,286.03 cw(c-188.47,283.02) -185.46,286.03 -181.44,282.02 cw(c-184.45,279.01) -181.44,275.99 -183.2,274.24 ccw(c-180.18,271.23) -183.2,268.21 -179.18,264.2 ccw(c-176.17,267.21) -173.16,264.2 -171.4,265.95 cw(c-168.39,262.94) -165.38,265.95 -165.13,265.7 -150.35,250.93 -147.36,247.94 -140.26,247.94 -130.32,247.94 cw(c-130.32,243.68) -126.06,243.68 -126.06,241.2 ccw(c-121.8,241.2) -121.8,236.94 -116.12,236.94 ccw(c-116.12,241.2) -111.86,241.2 -111.86,243.68 cw(c-107.6,243.68) -107.6,247.94 -101.92,247.94 cw(c-101.92,243.68) -97.66,243.68 -97.66,241.2 ccw(c-93.4,241.2) -93.4,236.94 -87.72,236.94 ccw(c-87.72,241.2) -83.46,241.2 -83.46,243.68 cw(c-79.2,243.68) -79.2,247.94 -69.26,247.94 -65,247.94 -48.61,247.94 -47.89,247.94 -41.67,254.16 -36.65,259.18 -29.62,266.21 cw(c-26.61,263.19) -23.6,266.21 -20.43,263.04 ccw(c-17.42,266.05) -14.4,263.04 -10.39,267.05 ccw(c-13.4,270.07) -10.39,273.08 -13.55,276.25 cw(c-10.54,279.26) -13.55,282.27 -9.54,286.29 cw(c-6.53,283.28) -3.51,286.29 -0.35,283.12 ccw(c2.67,286.13) 5.68,283.12 9.7,287.14 ccw(c6.68,290.15) 9.7,293.16 6.53,296.33 cw(c9.54,299.34) 6.53,302.35 10.04,305.87 12.82,308.64 12.82,447.24 122.4,556.82 122.4,737.4 171.36,786.36 198.5,786.36 199.65,785.22 v1(208.29,785.22)
  Bottom Layer w3.7: v1(-345,287) -335.5,296.5 -335.5,306.34 -316.2,325.63 -316.2,334.58 -280.86,369.93 -258.53,369.93 -257.69,370.77 -216.69,370.77 J2.110@-213.19,374.27
MCU_ADCIN_A12A13_P: J2.112 U1.K2 | length 1321.6
  Top Layer w3.7: v1(239.79,785.22) U1.K2@255.53,800.97
  L03_SIG1 w3.5: v1(-315,287) -320.82,287 -337.92,269.9 -353.9,269.9 -362.1,278.1 -362.1,294.08 -352.08,304.1 -342.32,304.1 -316.22,330.2 -215.2,330.2 -143.14,258.14 -52.11,258.14 2.62,312.87 2.62,451.47 112.2,561.05 112.2,741.62 115.09,744.51 151.16,780.58 167.14,796.56 197.57,796.56 201.98,800.97 224.04,800.97 v1(239.79,785.22)
  Bottom Layer w3.7: v1(-315,287) -324.5,296.5 -324.5,301.78 -305.2,321.08 -305.2,330.03 -276.3,358.93 -258.53,358.93 -257.69,358.09 -216.69,358.09 J2.112@-213.19,354.59
MCU_ADCIN_A14A15_N: J1.90 U1.M4 | length 2014.5
  Top Layer w3.7: v1(302.78,722.23) U1.M4@318.53,737.98
  L08_SIG3 w3.5: v1@298.55,722.23 v1(302.78,722.23) 304.94,722.23 311.53,728.81 ; 311.99,728.36 323.25,739.62 340.11,739.62 349.09,748.6 349.09,790.34 336.82,802.62 325.78,802.62 316.88,811.52 316.88,822.56 308.62,830.82 202.45,830.82 193.48,821.85 103.42,821.85 -53.29,665.13 -53.29,599.71 -108.2,544.8 -108.2,414.22 -114.2,408.22 -114.2,282.37 -86.83,255 79,255 153,181 253.42,181 283.83,211.4 477.4,211.4 596.38,330.38 596.38,363.33 v1(606.28,373.23)
  Bottom Layer w3.7: J1.90@597.62,252.13 597.47,252.28 597.47,297.81 596.78,298.51 596.78,303.51 cw(c596.9,303.51) 596.9,303.63 ccw(c596.9,303.76) 596.9,303.88 cw(c596.9,304.01) 596.78,304.01 596.78,363.73 v1(606.28,373.23)
MCU_ADCIN_A14A15_P: J1.92 U1.M3 | length 2050.7
  Top Layer w3.7: v1(271.28,722.23) U1.M3@287.03,737.98
  L08_SIG3 w3.5: v1(271.28,722.23) 288.68,739.62 308.83,739.62 320,750.79 320,793.97 311.35,802.62 202.38,802.62 193.95,811.05 107.89,811.05 -42.49,660.66 -42.49,595.23 -97.4,540.33 -97.4,409.75 -103.4,403.75 -103.4,286.85 -82.35,265.8 83.47,265.8 157.47,191.8 248.95,191.8 279.35,222.2 300.02,222.2 350.95,222.2 ccw(c350.95,227.75) 356.5,227.75 356.5,230.34 cw(c362.05,230.34) 362.05,235.89 369.45,235.89 cw(c369.45,230.34) 375,230.34 375,227.75 ccw(c380.55,227.75) 380.55,222.2 387.95,222.2 ccw(c387.95,227.75) 393.5,227.75 393.5,231.65 cw(c399.05,231.65) 399.05,237.2 406.45,237.2 cw(c406.45,231.65) 412,231.65 412,227.75 ccw(c417.55,227.75) 417.55,222.2 437.8,222.2 472.93,222.2 486.17,235.45 ccw(c480.79,237.24) 484.8,241.25 484.33,241.71 cw(c488.34,245.72) 484.33,249.73 487.77,253.17 cw(c491.78,249.16) 495.79,253.17 496.26,252.7 ccw(c500.27,256.71) 504.28,252.7 507.71,256.14 ccw(c503.7,260.15) 507.71,264.16 507.25,264.62 cw(c511.25,268.63) 507.25,272.64 510.68,276.08 cw(c514.69,272.07) 518.7,276.08 519.17,275.61 ccw(c523.18,279.62) 527.19,275.61 530.62,279.05 ccw(c526.61,283.06) 530.62,287.07 530.16,287.53 cw(c534.16,291.54) 530.16,295.55 533.59,298.99 cw(c537.6,294.98) 541.61,298.99 542.08,298.52 ccw(c546.09,302.53) 550.1,298.52 553.53,301.96 ccw(c549.52,305.97) 553.53,309.98 553.07,310.44 cw(c557.08,314.45) 553.07,318.46 556.5,321.9 cw(c560.51,317.89) 564.52,321.9 564.99,321.43 ccw(c569,325.44) 573.01,321.43 586.18,334.6 586.18,363.33 v1(576.28,373.23)
  Bottom Layer w3.7: v1(576.28,373.23) 585.78,363.73 585.78,298.53 584.94,297.69 J1.92@584.94,256.69 ; J1.92@581.44,253.19 J1.92@584.94,256.69 ; 585.78,298.51 585.09,297.81 585.09,256.84 J1.92@584.94,256.69
MCU_ADCIN_B0B1_N: J1.114 U1.N3 | length 526.7
  Top Layer w3.7: v1(271.28,690.73) U1.N3@287.03,706.48
  Bottom Layer w3.7: v1(271.28,690.73) 255.53,674.98 255.53,643.41 250.74,638.61 250.74,504.26 373.89,381.11 373.89,333.34 360.56,320.01 360.56,298.53 361.4,297.69 361.4,256.69 J1.114@364.9,253.19
MCU_ADCIN_B0B1_P: J1.116 U1.P2 | length 527.2
  Top Layer w3.7: v1(239.79,659.24) U1.P2@255.53,674.98
  Bottom Layer w3.7: 239.74,627.36 239.74,499.71 271.38,468.07 278.42,461.02 cw(c274.46,457.06) 278.42,453.1 278.16,452.84 ccw(c282.12,448.88) 278.16,444.92 281.55,441.53 ccw(c285.51,445.49) 289.47,441.53 289.73,441.79 cw(c293.69,437.83) 297.65,441.79 301.05,438.4 cw(c297.09,434.44) 301.05,430.48 300.79,430.22 ccw(c304.75,426.26) 300.79,422.3 304.18,418.9 ccw(c308.14,422.86) 312.1,418.9 312.36,419.16 cw(c316.32,415.2) 320.28,419.16 323.67,415.77 cw(c319.71,411.81) 323.67,407.85 323.41,407.59 ccw(c327.37,403.63) 323.41,399.67 326.81,396.28 ccw(c330.77,400.24) 334.73,396.28 334.99,396.54 cw(c338.95,392.58) 342.91,396.54 344.6,394.84 362.89,376.55 362.89,337.9 349.56,324.57 349.56,298.53 348.72,297.69 348.72,256.69 J1.116@345.22,253.19 ; 239.79,627.36 v1(239.79,659.24)
MCU_ADCIN_B2B3_N: J1.109 U1.L3 | length 1403.2
  Top Layer w3.7: v1(271.28,753.72) U1.L3@287.03,769.47
  Bottom Layer w3.7: v1(271.28,753.72) 255.69,769.32 197.02,769.32 126.21,698.5 126.21,390.41 180.15,336.47 185.15,336.47 248.04,273.58 248.04,223.16 216.99,192.12 184.36,192.12 168.74,176.5 168.74,-48.74 171.96,-51.96 204,-84 380,-84 399.93,-64.07 399.93,-17.75 400.77,-16.91 400.77,24.09 J1.109@404.27,27.59
MCU_ADCIN_B2B3_P: J1.111 U1.L4 | length 1400.5
  Top Layer w3.7: v1(302.78,753.72) U1.L4@318.53,769.47
  Bottom Layer w3.7: v1(302.78,753.72) 287.03,737.98 181.24,737.98 137.21,693.95 137.21,394.96 184.71,347.47 189.71,347.47 259.04,278.14 259.04,218.61 221.55,181.12 188.92,181.12 179.74,171.94 179.74,-44.18 208.56,-73 280.84,-73 287.44,-73 297.84,-73 ccw(c297.84,-67.4) 303.44,-67.4 303.44,-66.6 cw(c309.04,-66.6) 309.04,-61 313.84,-61 cw(c313.84,-66.6) 319.44,-66.6 319.44,-67.4 ccw(c325.04,-67.4) 325.04,-73 329.84,-73 ccw(c329.84,-67.4) 335.44,-67.4 335.44,-66.6 cw(c341.04,-66.6) 341.04,-61 345.84,-61 cw(c345.84,-66.6) 351.44,-66.6 351.44,-67.4 ccw(c357.04,-67.4) 357.04,-73 367.44,-73 375.44,-73 388.93,-59.51 388.93,-17.75 388.09,-16.91 388.09,24.09 J1.111@384.59,27.59
MCU_ADCIN_B4B5_N: J1.110 U1.K3 | length 1405.5
  Top Layer w3.7: v1(271.28,785.22) U1.K3@287.03,800.97
  L08_SIG3 w3.5: v1(271.28,785.22) 268.41,785.22 251.02,767.82 192.93,767.82 184.31,759.2 116.53,759.2 -18.2,624.47 -18.2,473.23 -76.71,414.71 -79.7,411.72 -79.7,353.09 -57.61,331 4.58,331 35.65,299.93 312.56,299.93 cw(c312.56,294.26) 318.23,294.26 318.23,293.6 ccw(c323.9,293.6) 323.9,287.93 328.76,287.93 ccw(c328.76,293.6) 334.43,293.6 334.43,294.26 cw(c340.1,294.26) 340.1,299.93 374.93,299.93 390.04,315.04 390.04,342.96 416.58,369.5 v1(429.58,369.5) v1@430.58,369.5
  Bottom Layer w3.7: J1.110@404.27,253.19 400.62,256.84 400.62,297.81 399.93,298.51 399.93,353.79 415.64,369.5 v1(429.58,369.5)
MCU_ADCIN_B4B5_P: J1.112 U1.K4 | length 1405
  Top Layer w3.7: v1(302.78,785.22) U1.K4@318.53,800.97
  L08_SIG3 w3.5: v1(302.78,785.22) 285.38,767.82 265.44,767.82 257.18,759.56 257.18,751.18 245.63,739.62 194.38,739.62 185,749 120.75,749 -8,620.25 -8,469 -69.5,407.5 -69.5,357.32 -53.38,341.2 8.8,341.2 39.87,310.13 370.7,310.13 379.84,319.26 379.84,347.19 382.83,350.17 408.5,375.85 v1@408.5,389.85
  Bottom Layer w3.7: J1.112@384.59,253.19 388.24,256.84 388.24,297.81 388.93,298.51 388.93,358.35 408.37,377.79 v1(408.37,390.72)
MCU_ADCIN_B6B7_N: J2.97 U1.H5 | length 809.9
  Top Layer w3.7: v1(334.27,879.71) U1.H5@350.02,863.96
  L03_SIG1 w3.5: v1(-71.17,497.54) -61.27,487.64 -52.72,487.64 -42.46,497.9 -42.46,689.52 121.21,853.2 159.9,853.2 331.81,853.2 334.27,855.66 v1(334.27,879.71)
  Bottom Layer w3.7: v1(-71.17,497.54) -61.67,488.04 -39.59,488.04 -32.93,488.04 -32.09,488.88 8.91,488.88 J2.97@12.41,492.38
MCU_ADCIN_B6B7_P: J2.99 U1.J5 | length 809.6
  Top Layer w3.7: v1(334.27,816.72) U1.J5@350.02,832.46
  L03_SIG1 w3.5: v1(-71.17,467.54) -61.27,477.44 -48.5,477.44 -32.26,493.67 -32.26,685.3 125.44,843 159.9,843 331.81,843 334.27,840.54 v1(334.27,816.72)
  Bottom Layer w3.7: v1(-71.17,467.54) -61.67,477.04 -44.15,477.04 -32.93,477.04 -32.09,476.2 8.91,476.2 J2.99@12.41,472.7
MCU_ADCIN_B12B13_N: J2.114 U1.J1 | length 985.1
  Top Layer w3.7: v1(208.29,816.72) U1.J1@224.04,832.46
  L03_SIG1 w3.5: v1(-135.86,340.06) -135.86,336.86 -127,328 -118,328 -115,331 -115,343.38 -128.78,357.16 -140.22,357.16 -157.38,340 -175.58,340 -185.2,349.62 -185.2,371.46 -176.71,379.96 -70.96,379.96 -66.11,375.11 -41.28,375.11 -22.7,393.69 -22.7,469.07 -11.86,479.91 -11.86,646.61 141.68,800.15 149.55,800.15 173.01,823.62 193.55,823.62 193.67,823.73 198.93,823.73 205.94,816.72 v1(208.29,816.72)
  Bottom Layer w3.7: J2.114@-213.19,334.9 -209.69,331.4 -168.69,331.4 -167.85,330.56 -145.36,330.56 v1(-135.86,340.06)
MCU_ADCIN_B12B13_P: J2.116 U1.J2 | length 989.6
  Top Layer w3.7: v1(239.79,816.72) U1.J2@255.53,832.46
  L03_SIG1 w3.5: v1(-135.86,310.06) -145.76,319.96 -169.96,319.96 -195.4,345.4 -195.4,375.69 -180.93,390.16 -66.73,390.16 -61.89,385.31 -45.5,385.31 -32.9,397.92 -32.9,473.29 -22.06,484.13 -22.06,650.83 116.79,789.68 137.46,810.35 145.32,810.35 168.79,833.82 189.33,833.82 189.44,833.93 222.57,833.93 236.65,819.85 236.65,816.72 v1(239.79,816.72)
  Bottom Layer w3.7: J2.116@-213.19,315.22 -209.69,318.72 -168.69,318.72 -167.85,319.56 -145.36,319.56 v1(-135.86,310.06)
MCU_ADCIN_B16B17_N: J2.113 U1.J3 | length 720.7
  Top Layer w3.7: v1(271.28,816.72) U1.J3@287.03,832.46
  L03_SIG1 w3.5: v1(96.12,368.95) 110.13,368.95 116.6,375.42 116.6,396.03 119.48,398.9 126.92,406.35 ccw(c122.91,410.36) 126.92,414.37 126.46,414.83 cw(c130.47,418.84) 126.46,422.85 129.89,426.29 cw(c133.9,422.28) 137.91,426.29 138.38,425.82 ccw(c142.39,429.83) 146.4,425.82 149.83,429.26 ccw(c145.82,433.27) 149.83,437.28 149.37,437.74 cw(c153.38,441.75) 149.37,445.76 152.8,449.2 cw(c156.81,445.19) 160.82,449.2 161.29,448.73 ccw(c165.3,452.74) 169.31,448.73 176.75,456.18 182.48,461.9 182.48,695.48 192,705 246.74,705 257.18,715.44 257.18,802.62 v1(271.28,816.72)
  Bottom Layer w3.7: J2.113@12.41,334.9 15.91,331.4 56.91,331.4 57.75,330.56 71.17,330.56 96.12,355.51 v1(96.12,368.95)
MCU_ADCIN_B16B17_P: J2.115 U1.J4 | length 720.9
  Top Layer w3.7: v1(302.78,816.72) U1.J4@318.53,832.46
  L03_SIG1 w3.5: v1(117.34,347.73) 117.34,361.73 126.8,371.2 126.8,391.8 192.68,457.68 192.68,669.68 199.63,676.63 245.63,676.63 253.89,684.89 253.89,697.72 264.29,708.13 277.12,708.13 285.68,716.68 285.68,799.62 v1(302.78,816.72)
  Bottom Layer w3.7: J2.115@12.41,315.22 15.91,318.72 56.91,318.72 57.75,319.56 75.73,319.56 103.9,347.73 v1(117.34,347.73)
MCU_ADCIN_C0: J1.106 U1.R2 | length 693.3
  Top Layer w5.66: U1.R2@255.53,643.49 239.79,627.74 239.79,597.85 211.67,569.74 211.67,310.55 330.05,192.17 v1(443.51,192.17)
  Bottom Layer w5.66: v1(443.51,192.17) 443.57,192.23 443.57,253.12 J1.106@443.64,253.19 J1.106@443.83,253.38
MCU_ADCIN_C1: J1.103 U1.T2 | length 889.7
  Top Layer w5.66: U1.T2@255.53,611.99 255.53,592.19 226.76,563.42 226.76,318.43 326.76,218.43 449.77,218.43 463.24,204.96 v1(463.24,-34.06)
  Bottom Layer w5.66: v1(463.24,-34.06) 463.33,-33.97 J1.103@463.33,27.59
MCU_ADCIN_C2: J1.101 U1.N4 | length 1078.2
  Top Layer w5.66: v1(302.78,690.73) U1.N4@318.53,706.48
  L03_SIG1 w4.5: v1(302.78,690.73) 287.98,675.93 265.35,675.93 255,665.58 255,647.17 225.27,617.44 225.27,560.65 225.27,291.7 250.14,266.82 250.14,59.97 369.78,-59.66 v1(482.82,-59.66)
  Bottom Layer w5.66: v1(482.82,-59.66) 482.95,-59.54 J1.101@482.95,27.53
MCU_ADCIN_C3: J2.111 U1.M5 | length 712.6
  Top Layer w5.66: v1(334.27,722.23) U1.M5@350.02,737.98
  L08_SIG3 w4.5: v1@69.67,356.46 42.54,356.46 14,385 14,485 77.91,548.91 202.91,548.91 286.59,632.59 286.59,664.71 296.43,674.55 308.25,674.55 318.52,684.82 318.52,706.48 v1(334.27,722.23)
  Bottom Layer w5.66: J2.111@-2,354.59 -1.55,354.14 65.23,354.14 67.55,356.46 v1@69.67,356.46
  other v1: 68.67,356.46
MCU_ADCIN_C4: J2.109 U1.P5 | length 901.5
  Top Layer w5.66: v1(334.27,659.24) U1.P5@350.02,674.98
  L08_SIG3 w4.5: v1(-49,361) 11,361 40,332 120.88,332 121.3,332.42 126.75,332.42 136,341.67 136,362.28 112.28,386 90.41,386 80.41,376 60,376 35,401 35,479 88,532 230,532 318.09,620.09 318.09,643.05 v1(334.27,659.24)
  Bottom Layer w5.66: v1(-49,361) -47.82,361 -37.21,371.6 9.74,371.6 J2.109@12.41,374.27
MCU_ADCIN_C5: J2.108 U1.N5 | length 1228.5
  Top Layer w5.66: v1(334.27,690.73) U1.N5@350.02,706.48
  L08_SIG3 w4.5: v1(-276.21,420.04) -237.66,458.59 -237.66,507.34 -92,653 -92,700 61.54,853.54 382.1,853.54 412.58,823.06 412.58,747.38 403.14,737.94 390.76,737.94 381.48,728.67 381.48,715.72 371.81,706.04 349.59,706.04 v1(334.27,690.73)
  Bottom Layer w5.66: v1(-276.21,420.04) -276.21,402.47 -267.69,393.96 J2.108@-213.19,393.96
MCU_ADCIN_C11: J2.107 U1.P8 | length 1243.1
  Top Layer w5.66: v1(428.76,659.24) U1.P8@444.51,674.98
  L03_SIG1 w4.5: v1(-50,405) -66.18,405 -98,436.82 -98,537 -81,554 -81,684 109,874 182.43,874 192.71,863.72 308.45,863.72 317.47,872.74 317.47,881.81 317.28,881.99 317.28,891.28 321.71,895.71 344.17,895.71 344.41,895.47 403.16,895.47 413.45,885.18 413.45,685.54 427.36,671.63 427.36,660.64 v1(428.76,659.24)
  Bottom Layer w5.66: v1(-50,405) -46.66,405 -38.29,396.63 9.74,396.63 J2.107@12.41,393.96
MCU_ADCIN_C12: J1.107 U1.R8 | length 1273.1
  Top Layer w5.66: v1(423.87,114.55) 423.87,112.99 415.94,105.06 415.94,-43.37 467.93,-95.36 532.85,-95.36 559.81,-68.41 559.81,32.53 537.88,54.45 537.88,116.5 596.14,174.77 596.14,200.86 541.66,255.34 541.66,339.17 514.74,366.09 514.74,378.82 481.81,411.76 466.18,411.76 449.18,428.76 449.18,448.02 406.84,490.36 406.84,551.66 429.79,574.61 429.79,628.77 U1.R8@444.51,643.49
  Bottom Layer w5.66: v1(423.87,114.55) v1(423.87,114.55) 423.91,27.63 J1.107@423.96,27.59
MCU_ADCIN_C13: J2.106 U1.T8 | length 2384.8
  Top Layer w5.66: U1.T8@444.51,611.99 444.51,572.84 418.5,546.83 418.5,495.19 460.84,452.85 460.84,433.59 471.01,423.42 486.64,423.42 526.4,383.65 526.4,370.92 555.96,341.36 561.64,341.36 v1(564,339)
  L03_SIG1 w4.5: v1(-123.46,433.49) -139.05,449.07 -319.3,449.07 -353.24,415.13 -353.24,320.04 -374.02,299.26 -374.02,268.8 -357.22,252 -345,252 -277,184 -277,160.11 -220.89,104 116,104 297.98,-77.98 531.02,-77.98 561,-48 561,33 606.61,78.61 606.61,243.39 566,284 v1@566,336
  Bottom Layer w5.66: J2.106@-213.19,413.64 -142.31,413.64 v1@-122.96,432.99
MCU_ADCIN_C16: J1.105 U1.N7 | length 837.8
  Top Layer w5.66: v1(397.27,690.73) U1.N7@413.01,706.48
  L03_SIG1 w4.5: v1(397.27,690.73) 397.27,689.03 405.26,681.03 ; 405.26,681 413.02,673.24 413.02,665.76 413.01,650.99 425,639 428.15,635.85 428.15,540.12 428.06,540.03 428.06,446.08 487,387.14 487,328 560,255 560,148 506.48,94.48 v1(444.08,94.48)
  Bottom Layer w5.66: J1.105@443.52,27.46 J1.105@443.64,27.59 443.86,27.81 443.86,94.26 v1(444.08,94.48)
MCU_ADCIN_C17: J1.108 U1.P7 | length 463.9
  Top Layer w5.66: v1(397.27,659.24) U1.P7@413.01,674.98
  L03_SIG1 w4.5: v1(397.27,659.24) 399.44,657.06 399.44,648.24 413.57,634.11 413.57,621.71 397.53,605.66 397.53,560.65 397.53,447.47 446.89,398.1 446.89,361.9 423.94,338.94 v1@423.94,320.07
  Bottom Layer w5.66: J1.108@423.9,253.14 J1.108@423.96,253.19 ; J1.108@423.94,261.01 v1@423.94,320.07
  other v1: 423.94,318.07
MCU_ADCIN_D0: J1.104 U1.R3 | length 642.1
  Top Layer w5.66: U1.R3@287.03,643.49 271.28,627.74 271.28,588.33 242.55,559.6 242.55,324.12 275.36,291.32 299.07,291.32 299.36,291.61 450.9,291.61 459.87,300.58 459.87,302.26 463.72,306.11 v1(463.72,309.45)
  Bottom Layer w5.66: J1.104@463.33,253.19 463.52,253.38 463.52,311.94 v1@463.72,312.14
MCU_ADCIN_D1: J1.102 U1.T3 | length 622.7
  Top Layer w5.66: U1.T3@287.03,611.99 287.03,576.68 271,560.65 271,474.68 364.97,380.71 364.97,352.14 381.12,336 433.22,336 441.94,327.28 471.1,327.28 482.9,315.48 v1(482.9,192.27)
  Bottom Layer w5.66: v1@482.97,192.34 J1.102@483.01,253.19 J1.102@483.01,253.19
MCU_ADCIN_D2: J1.99 U1.R5 | length 857.5
  Top Layer w5.66: U1.R5@350.02,643.49 v1(334.27,627.74) 334.27,597.59 354.91,576.95 354.91,420.86 381.09,394.68 381.09,362.56 395.98,347.66 438.05,347.66 446.77,338.94 475.93,338.94 494.57,320.31 494.57,217.44 502.91,209.09 502.91,-33.76 v1(502.61,-34.06)
  Bottom Layer w5.66: v1(502.61,-34.06) 502.7,-33.97 J1.99@502.7,27.59
MCU_ADCIN_D3: J1.97 U1.R6 | length 905.5
  Top Layer w5.66: U1.R6@381.52,643.49 v1(365.77,627.74) 365.77,602 380.77,587 380.77,481.78 425.86,436.68 425.86,419.1 456.52,388.44 472.15,388.44 491.42,369.16 491.42,356.43 517.88,329.97 517.88,246.14 559,205.02 559,182.78 564,177.78 564,161.48 522.19,119.68 v1(522.19,-59.66)
  Bottom Layer w5.66: v1(522.19,-59.66) 522.32,-59.54 J1.97@522.32,27.53
MCU_ADCIN_D10: J1.100 U1.N6 | length 679.5
  Top Layer w5.66: v1(365.77,690.73) U1.N6@381.52,706.48
  Bottom Layer w5: 289.3,643.67 340.63,643.67 350.27,653.31 350.27,675.23 v1(365.77,690.73)
  Bottom Layer w5.66: 289.3,643.67 271,625.37 271,500.29 330.29,441 422.87,441 502.91,360.96 502.91,253.4 J1.100@502.7,253.19
MCU_ADCIN_D11: J1.98 U1.P6 | length 655
  Top Layer w5.66: v1(365.77,659.24) U1.P6@381.52,674.98
  L03_SIG1 w4.5: v1(365.77,659.24) 381.08,643.92 381.08,457.83 368,444.75 368,292 443,217 501.06,217 v1(523.07,194.99)
  Bottom Layer w5.66: J1.98@522.38,253.19 523.07,252.53 v1(523.07,194.99)
MCU_ADCIN_D12: J2.105 U1.M7 | length 697.2
  Top Layer w5.66: v1(397.27,722.23) U1.M7@413.01,737.98
  L08_SIG3 w4.5: v1(90.04,413.35) 67.65,413.35 53,428 53,442 71.27,460.27 271.27,460.27 357,546 357,560.65 357,597.31 381.08,621.4 381.08,696.2 395.09,710.21 395.09,720.05 v1(397.27,722.23)
  Bottom Layer w5.66: J2.105@12.41,413.64 12.76,413.3 89.99,413.3 v1(90.04,413.35)
MCU_ADCIN_D13: J2.104 U1.M6 | length 1030.9
  Top Layer w5.66: v1(365.77,722.23) U1.M6@381.52,737.98
  L08_SIG3 w4.5: v1(-130,502) -130,551 -120.7,560.3 -120.7,591.3 -68.59,643.41 -68.59,698.41 73.92,840.92 363.23,840.92 381.08,823.06 381.08,747.38 367.95,734.24 367.95,724.4 v1(365.77,722.23)
  Bottom Layer w6.63: J2.104@-240.12,433.54 -155.72,433.54 -130,459.27 v1(-130,502)
MCU_ADCIN_D16: J2.103 U1.R7 | length 528.4
  Top Layer w5.66: v1(397.27,627.74) U1.R7@413.01,643.49
  L08_SIG3 w4.5: v1(85.64,437.35) 276.35,437.35 378.63,539.63 378.63,560.65 378.63,595.84 397.27,614.48 v1(397.27,627.74)
  Bottom Layer w5.66: J2.103@12.41,433.33 81.61,433.33 v1(85.64,437.35)
MCU_ADCIN_D17: R70.1 U2.32 | length 3882.1
  Top Layer w5.66: U2.32@1546.52,1433.38 v1(1546.52,1475.73) v1@1546.52,1476.73
  L05_SIG2 w4: v1(1546.52,1475.73) 1528.69,1493.56 1528.69,1523.44 1549.15,1543.9 1610,1543.9 1665,1488.9 1665,1025 1683.98,1006.02 1683.98,965.85 1569,850.87 1569,393 1546,370 1546,353.89 1613.89,286 v1(1709,286)
  Bottom Layer w5.66: R70.1@420.17,486.31 435.04,471.44 435.04,450.47 478.18,407.33 600.46,407.33 614.13,421 726.58,421 770.44,377.15 873.85,377.15 898.45,352.55 898.45,208.82 850.55,160.93 850.55,122.68 908.63,64.6 1079.52,-106.29 1723.71,-106.29 1760,-70 1760,177 1737,200 1729.78,200 1688.17,241.61 1688.17,265.17 v1(1709,286)
MCU_ADCIN_E0: J1.95 U1.P3 | length 1020.3
  Top Layer w5.66: v1(271.28,659.24) U1.P3@287.03,674.98
  L03_SIG1 w4.5: v1(271.28,659.24) 269.11,657.06 269.11,643.42 237.89,612.21 237.89,560.65 237.89,303.45 263.27,278.08 263.27,68.33 308.3,23.3 484.61,23.3 v1(541.98,-34.06)
  Bottom Layer w5.66: v1(541.98,-34.06) 542.07,-33.97 J1.95@542.07,27.59
MCU_ADCIN_E1: J1.93 U1.P4 | length 999.3
  Top Layer w5.66: v1(302.78,659.24) U1.P4@318.53,674.98
  L03_SIG1 w4.5: v1(302.78,659.24) 250.52,606.98 250.52,560.65 250.52,308.68 275.89,283.31 275.89,82.75 296.2,62.44 533.3,62.44 v1(561.25,90.39)
  Bottom Layer w5.66: v1(561.25,90.39) 561.5,90.14 561.5,27.84 J1.93@561.75,27.59
MCU_ADCIN_E2: J1.96 U1.T5 | length 613.6
  Top Layer w5.66: U1.T5@350.02,611.99 350.02,598.75 366.97,581.8 366.97,479.09 414.2,431.86 414.2,414.27 451.69,376.78 467.32,376.78 479.76,364.33 479.76,351.6 506.22,325.14 506.22,237.05 542.08,201.19 v1(542.08,166.31)
  Bottom Layer w5.66: J1.96@542.07,253.19 J1.96@542.2,253.32 ; v1(542.08,166.31) J1.96@542.08,245.37
MCU_ADCIN_E3: J1.94 U1.T6 | length 583.3
  Top Layer w5.66: U1.T6@381.52,611.99 395.18,598.33 395.18,485.53 437.52,443.19 437.52,423.93 461.35,400.1 476.98,400.1 503.08,373.99 503.08,361.26 530,334.34 530,250.51 575.27,205.24 575.27,191.73 v1(577.58,189.41)
  Bottom Layer w5.66: J1.94@561.75,253.19 561.75,205.24 v1(577.58,189.41)
MCU_ADCIN_E10: J1.91 U1.R10 | length 865.5
  Top Layer w5.66: U1.R10@507.5,643.49 v1(523.25,627.74)
  L03_SIG1 w4.5: v1(523.25,627.74) 539,611.99 539,586.6 517.2,564.8 500.05,547.65 500.05,480.06 484,464.01 484,426 552.08,357.92 578.75,357.92 586.88,349.8 586.88,288.12 623,252 623,57.13 581.35,15.47 v1(581.35,-34.06)
  Bottom Layer w5.66: v1(581.35,-34.06) 581.44,-33.97 J1.91@581.44,27.59
MCU_ADCIN_E12: J1.89 U1.P9 | length 987.2
  Top Layer w5.66: U1.P9@476.01,674.98 v1(491.75,659.24)
  L03_SIG1 w4.5: v1(491.75,659.24) 506.47,644.52 562.48,644.52 570.53,636.47 570.53,586.99 546.42,562.88 546.42,428.42 568.37,406.48 594.86,406.48 621.59,379.75 621.59,366.89 603,348.3 603,293 637,259 637,30.2 600.93,-5.87 v1(600.93,-59.66)
  Bottom Layer w5.66: v1(600.93,-59.66) 601.06,-59.54 J1.89@601.06,27.53
MCU_AIO186: J1.54 U1.N8 | length 1135
  Top Layer w5.66: v1(428.76,690.73) U1.N8@444.51,706.48
  Bottom Layer w5: 418.01,643.99 413.26,648.74 413.26,675.23 v1(428.76,690.73)
  Bottom Layer w5.66: 418.01,643.99 446.43,615.57 446.43,572.5 446.7,572.24 446.7,455.3 483.01,418.99 586.46,418.99 605.54,438.08 726.08,438.08 769.95,394.21 873.28,394.21 905.42,362.07 1131.78,362.07 1152.55,341.3 1152.55,340.38 1152.42,340.25 J1.54@1152.42,253.19
MCU_AIO206: J2.27 U1.T10 | length 1307.5
  Top Layer w5.66: U1.T10@507.5,611.99 v1(523.25,596.24)
  L03_SIG1 w4.5: v1(-64.39,1377.23) -65.89,1375.73 -65.89,1335.29 -50.87,1320.27 2.27,1320.27 73.21,1249.33 199.67,1249.33 326,1123 431.78,1123 446.51,1108.27 446.51,952.81 463.41,935.9 463.41,633.86 485.03,612.24 507.25,612.24 v1(523.25,596.24)
  Bottom Layer w5.66: v1@-66.39,1377.23 -65.5,1378.13 J2.27@12.61,1378.13
MCU_AIO207: J2.25 U1.T9 | length 1536
  Top Layer w5.66: U1.T9@476.01,611.99 v1(491.75,596.24)
  L03_SIG1 w4.5: v1(77.06,1373.92) 53.89,1373.92 30.32,1397.49 -101.53,1397.49 -122.82,1376.2 -122.82,1331.64 -93.41,1302.23 -0.01,1302.23 67.21,1235 194,1235 344.53,1084.47 403.7,1084.47 411.99,1076.18 411.99,1075.62 412.98,1074.63 412.98,936.26 422.32,926.92 435.27,926.92 450.79,911.4 450.79,624.54 478.07,597.26 490.73,597.26 v1(491.75,596.24)
  Bottom Layer w5.66: J2.25@12.41,1398.01 12.5,1397.92 65.74,1397.92 76.69,1386.97 76.69,1374.29 v1(77.06,1373.92)
MCU_AIO209: J2.29 U1.R9 | length 1192.7
  Top Layer w5.66: U1.R9@476.01,643.49 v1(491.75,627.74)
  L03_SIG1 w4.5: v1(-47.57,1358.7) -16.39,1358.7 79.17,1263.14 205.86,1263.14 332.69,1136.31 440.53,1136.31 460.23,1116.61 460.23,957.58 476.04,941.77 476.04,674.04 476,674 476,643.49 v1(491.75,627.74)
  Bottom Layer w5.66: v1(-47.57,1358.7) -47.43,1358.84 -47.25,1358.67 12.38,1358.67 J2.29@12.61,1358.44
MCU_AIO211: J1.52 U1.N9 | length 988.8
  Top Layer w5.66: U1.N9@476.01,706.48 v1(491.75,690.73)
  Bottom Layer w5: v1(491.75,690.73) 507.75,674.74 507.75,588.91 529.07,567.59
  Bottom Layer w5.66: 529.07,567.59 615.95,567.59 775.08,408.47 875.51,408.47 910.25,373.73 1144.72,373.73 1172.2,346.25 1172.2,314.84 1172.11,314.75 J1.52@1172.11,253.19
MCU_AIO212: J1.48 U1.P10 | length 973.3
  Top Layer w5.66: U1.P10@507.5,674.98 v1(523.25,659.24)
  Bottom Layer w5: v1(523.25,659.24) 538.75,643.74 627.22,643.74 627.75,643.2
  Bottom Layer w5.66: 627.75,643.2 693.67,577.28 712.4,577.28 720.76,568.91 720.76,562.56 721.05,562.28 721.05,547.51 720.76,547.22 720.76,502.12 788.07,434.81 882.14,434.81 919.91,397.05 1161.74,397.05 1211.57,347.22 1211.57,314.84 1211.48,314.75 J1.48@1211.48,253.19
MCU_AIO213: J1.50 U1.T11 | length 856.4
  Top Layer w5.66: U1.T11@539,611.99 v1(554.75,596.24)
  Bottom Layer w5.66: v1(554.75,596.24) 571.03,579.96 579.43,579.96 579.48,579.91 620.13,579.91 639.39,560.65 777.78,422.26 878.21,422.26 915.08,385.39 1153.35,385.39 1191.92,346.82 1191.92,340.38 1191.79,340.25 J1.50@1191.79,253.19
MCU_CANRX: J1.37 R45.1 R54.1 | length 2452.1
  Top Layer w5.66: R45.1@851.9,1040.34 852.34,1039.9 930.9,1039.9 v1@950,1059
  L03_SIG1 w4.5: v1(951,1058) 913,1058 903,1048 903,986.02 929.66,959.35 968.99,959.35 1061.56,866.78 1061.56,734.53 1103.09,693 1303,693 1475.63,520.37 1475.63,478.2 1617,336.82 1617,311 1690,238 1690,188 1751.69,126.31 1751.69,-18.31 1671.33,-98.67 1477.88,-98.67 1460,-80.79 1460,-44.03 1410.97,5 1321,5 1302.2,-13.8 1302.2,-50.61 v1(1326.56,-74.97)
  Bottom Layer w5.66: J1.37@1309.9,27.59 1309.9,-58.31 v1(1326.56,-74.97)
MCU_CANTX: J1.35 R26.1 R27.1 | length 1622.5
  Top Layer w5.66: R26.1@857.42,931.32 857.42,934.24 880.44,934.24 v1(886.3,940.1)
  L05_SIG2 w4: v1(1060.6,443.71) 1060.6,470.79 1147.49,557.68 1176.54,557.68 1187.92,569.06 1218.39,569.06 1236.4,551.05 1236.4,483.83 1230.1,477.53 1230.1,446.96 1210,426.86 1210,396.41 1221,385.41 1221,358 1211,348 1211,309 1329.76,190.23 v1(1329.76,-38.78)
  Bottom Layer w5.66: v1(886.3,940.1) 932.17,894.23 932.17,497.83 986.29,443.71 v1(1060.6,443.71) ; J1.35@1329.59,27.59 1329.76,27.41 v1(1329.76,-38.78)
MCU_ERRORSTS: R44.2 TP13.1 U1.M16 U2.18 | length 1894.1
  Top Layer w5.66: U1.M16@696.48,737.98 v1(712.23,722.23) ; TP13.1@909.23,349.63 917.01,349.63 v1(965.59,301.05) ; U2.18@1566.21,1138.1 1566.57,1137.73 1566.57,1096.14 1566.94,1096.14 v1(1582.13,1080.96) ; v1@1581.95,1080.77 v1@1582.13,1080.59
  Top Layer w6.66: R44.2@870.64,229.47 870.64,233.41 879.12,241.89 909.23,272 TP13.1@909.23,349.63
  L03_SIG1 w4.5: v1(712.23,722.23) 744.97,689.48 747.52,689.48 794.3,642.7 794.3,545.44 953.21,386.54 953.21,312.64 964.79,301.05 v1(965.59,301.05)
  L08_SIG3 w4.5: v1(712.23,722.23) 740.05,750.05 740.05,808.07 749.02,817.04 761.98,817.04 763.22,815.79 795.68,815.79 823,843.11 823,865 870.67,912.67 909.67,912.67 1051.69,1054.69 1555.86,1054.69 1581.87,1080.69 1581.87,1081.22 v1(1582.13,1080.96)
MCU_ESC_RX1_DATA1: J3.80 R25.1 | length 1695.1
  Top Layer w5.66: R25.1@899.57,984.45 v1@934.82,984.45
  L03_SIG1 w4.5: v1(935.02,984.65) 924.39,995.27 924.39,1021.39 942.69,1039.69 959.69,1039.69 1020.52,1100.52 1063.07,1100.52 1065.32,1100.52 ccw(c1065.32,1114.27) 1079.07,1114.27 1079.07,1116.77 cw(c1092.82,1116.77) 1106.57,1116.77 1106.57,1080.93 ccw(c1120.32,1080.93) 1134.07,1080.93 1134.07,1116.77 cw(c1147.82,1116.77) 1161.57,1116.77 1161.57,1114.27 ccw(c1175.32,1114.27) 1175.32,1100.52 1200,1100.52 1362.72,1100.52 1423.55,1161.35 1838.41,1161.35 1855.07,1178 2197,1178 2239.84,1220.84 v1(2239.84,1240.36)
  Bottom Layer w5.66: J3.80@2178.19,1240.45 2239.75,1240.45 v1(2239.84,1240.36)
MCU_ESC_RX1_DATA2: J3.82 R29.1 | length 1658.1
  Top Layer w5.66: R29.1@899.15,1087.58 904.12,1092.55 v1(933.35,1092.55)
  L03_SIG1 w4.5: v1(933.35,1092.55) 933.35,1120.64 1031,1218.28 1075.76,1218.28 1078.01,1218.28 ccw(c1078.01,1232.03) 1091.76,1232.03 1091.76,1237.54 cw(c1105.51,1237.54) 1119.26,1237.54 1119.26,1232.03 ccw(c1133.01,1232.03) 1133.01,1218.28 1169.58,1218.28 1215,1218.28 1702.09,1218.28 1734.89,1218.28 1757.44,1195.72 1824.96,1195.72 1864.92,1235.68 2183.68,1235.68 2226,1278 2250.36,1278 v1(2271.71,1299.34)
  Bottom Layer w5.66: J3.82@2178.19,1260.14 2250.49,1260.14 2271.71,1281.35 v1(2271.71,1299.34)
MCU_GPIO0: J1.15 U1.A8 | length 2037.8
  Top Layer w5.66: v1(428.76,1100.18) U1.A8@444.51,1084.43
  L08_SIG3 w4.5: v1(428.76,1100.18) 448,1080.94 448,1027.11 485.17,989.94 561.4,989.94 570.23,981.12 570.23,748.1 560.1,737.98 550.34,737.98 549.09,736.73 548.74,736.73 540,727.99 540,715 532.56,707.56 516.83,707.56 507.5,698.24 507.5,589.77 507.54,589.73 542.93,554.35 542.93,519.07 559.6,502.4 645.16,502.4 763.92,383.64 763.92,326.07 774.2,315.8 774.2,292.63 944.79,122.05 1501.94,122.05 v1(1521.6,102.39)
  Bottom Layer w5.66: v1(1521.6,102.39) 1526.44,97.55 J1.15@1526.44,27.59
MCU_GPIO1: J1.13 U1.A7 | length 3143.6
  Top Layer w5.66: v1(397.27,1100.18) U1.A7@413.01,1084.43
  L08_SIG3 w4.5: v1(1048.57,554.51) 1001.8,554.51 950.28,502.99 950.28,294.71 1005.51,239.48 1423.52,239.48 1483.84,179.16 1483.84,155.77 1494.13,145.48 1512.39,145.48 v1(1558.07,99.8)
  Bottom Layer w5.66: v1(397.27,1100.18) 397.27,1130.91 375.19,1152.99 375.19,1230.38 350.38,1255.19 350.38,1356.54 425.76,1431.92 520.63,1431.92 669.02,1580.3 914.74,1580.3 985,1510.04 985,1148 1017,1116 1017,1000 1029.87,987.13 1029.87,573.21 v1(1048.57,554.51) ; J1.13@1546.12,27.59 1546.12,87.86 v1(1558.07,99.8)
MCU_GPIO2: J1.11 U1.B7 | length 3486.3
  Top Layer w5.66: v1(397.27,1068.68) U1.B7@413.01,1052.94
  L08_SIG3 w4.5: v1(1043.57,481.86) 1043.57,285.43 1059.65,269.35 1439.21,269.35 1474.84,233.72 1635.95,233.72 1682.55,187.13 1682.55,41.83 v1(1565.72,-75)
  Bottom Layer w5.66: v1(397.27,1068.68) 377.39,1088.56 377.39,1131.32 361.8,1146.91 361.8,1227.28 338.72,1250.36 338.72,1361.36 420.93,1443.58 438.02,1443.58 586.44,1592 644.7,1592 ; 644.74,1591.96 919.57,1591.96 1003,1508.53 1003,1156 1029,1130 1029,1009.51 1044,994.51 1044,584.51 1066.4,562.11 1066.4,504.69 1044.12,482.42 1043.01,482.42 v1(1043.57,481.86) ; v1@1565.81,-75 J1.11@1565.81,27.59
MCU_GPIO3: J1.9 U1.C7 | length 2111.7
  Top Layer w5.66: v1(397.27,1037.19) U1.C7@413.01,1021.44
  L08_SIG3 w4.5: v1(397.27,1037.19) 399.94,1034.51 399.75,1034.32 399.75,1027.95 399.94,1027.76 399.94,1024.93 412.77,1012.11 412.77,997.23 420.49,989.51 454.49,989.51 485.12,958.88 531,958.88 538.56,951.32 538.56,747.38 529.16,737.98 517.34,737.98 507.94,728.57 507.94,716.75 497.46,706.28 485.65,706.28 476.44,697.07 476.44,585.07 498.24,563.27 498.24,524.76 535,488 641.71,488 716.13,413.58 716.13,318.51 970.21,64.43 1548.59,64.43 1585.49,101.33 v1(1585.49,101.47)
  Bottom Layer w5.66: J1.9@1585.49,27.59 v1(1585.49,101.47)
MCU_GPIO4: J1.7 U1.D7 | length 2131.8
  Top Layer w5.66: v1(397.27,1005.69) U1.D7@413.01,989.94
  L08_SIG3 w4.5: v1(397.27,1005.69) 381.48,989.91 381.48,968.32 390.92,958.88 447.3,958.88 478.8,927.39 497.23,927.39 507.07,917.55 507.07,746.07 498.54,737.54 485.41,737.54 463.81,715.94 463.81,528.47 520.29,472 621.26,472 682.39,410.88 682.39,252.48 832.32,102.55 v1(895.89,102.55)
  Bottom Layer w5.66: v1(895.89,102.55) 952.45,102.55 971.94,122.05 1590.13,122.05 1605.18,107 J1.7@1605.18,27.59
MCU_GPIO5: J1.5 U1.A6 | length 2809.9
  Top Layer w5.66: U1.A6@381.52,1084.43 364.04,1101.91 364.04,1167.41 332.79,1198.65 332.79,1423.67 v1(384.12,1475)
  L03_SIG1 w4.5: v1(384.12,1475) 399.53,1459.59 490.08,1459.59 693.25,1256.42 693.25,1198.73 648.55,1154.03 648.55,1113.15 717.69,1044 717.69,990.39 727.54,980.54 727.54,868.76 735.51,860.79 810.09,860.79 865.17,805.71 865.17,644.83 889.36,620.64 916.03,620.64 933,603.67 933,564.04 965,532.04 965,470.71 1010.31,425.4 1068.19,425.4 1086.5,443.71 1302.29,443.71 1380.76,365.23 1464.93,365.23 1513.05,317.11 1513.05,316.79 1574.83,255 1589,255 1640.1,203.9 v1(1640.1,116.53)
  Bottom Layer w5.66: J1.5@1624.86,27.59 1624.86,101.29 v1(1640.1,116.53)
MCU_GPIO6: R88.2 R91.2 U1.B6 | length 167.4
  Top Layer w5.66: v1(365.77,1068.68) U1.B6@381.52,1052.94
  Bottom Layer w5.66: R88.2@296.63,1161.2 R91.2@337.63,1161.2 339.17,1159.66 339.17,1135.77 339.17,1135.47 350.02,1124.62 350.02,1084.43 v1(365.77,1068.68)
MCU_GPIO7: R94.2 R96.2 U1.C6 | length 415.1
  Top Layer w5.66: R96.2@141.08,1111.89 132.34,1120.63 132.34,1149.72 141.32,1158.7 141.32,1170.51 R94.2@142.26,1170.51 145.25,1173.5 v1(145.25,1197.65) v1@145.25,1202.65 ; v1(365.77,1037.19) U1.C6@381.52,1021.44
  L03_SIG1 w4.5: v1@143.25,1202.65 145.25,1202.65 v1@147.75,1200.15 ; v1(145.25,1197.65) 205.31,1197.65 v1(365.77,1037.19)
MCU_GPIO8: R55.2 R83.2 U1.D6 | length 260.5
  Top Layer w5.66: v1(365.77,1005.69) U1.D6@381.52,989.94
  Bottom Layer w5: 350.04,1062.85 350.04,1021.42 v1(365.77,1005.69)
  Bottom Layer w5.66: R55.2@214.63,1161.2 R83.2@255.63,1161.2 ; R83.2@255.63,1157.26 350.04,1062.85
MCU_GPIO9: J1.73 LED4.2 U1.A5 | length 5831.9
  Top Layer w5.66: U1.A5@350.02,1084.43 350.02,1157.57 320.71,1186.88 320.71,1469.85 v1(410.14,1559.28) ; LED4.2@2193.68,1169.19 2212.25,1169.19 v1(2242.64,1138.8)
  L08_SIG3 w4.5: v1(410.14,1559.28) 425.86,1575 485,1575 687.03,1777.03 1008.71,1777.03 1048.82,1817.14 1590.71,1817.14 1682.78,1725.08 1802.86,1725.08 1854.13,1673.81 2132.67,1673.81 2179.48,1627 2229.19,1627 2259.07,1597.12 2277.24,1597.12 2294.22,1580.14 2294.22,1190.39 v1(2242.64,1138.8) 2242.64,1138.39 2257.33,1123.71 2271.97,1123.71 2288.8,1106.87 2288.8,818.85 2211.73,741.78 2211.73,289.73 2024.8,102.8 2024.8,5.08 1907.75,-111.97 810.72,-111.97 v1(758.41,-59.66)
  Bottom Layer w5.66: v1(758.41,-59.66) 758.54,-59.54 J1.73@758.54,27.53
MCU_GPIO10: J1.64 R3.1 U1.C5 | length 5382.1
  Top Layer w5.66: v1(334.27,1037.19) U1.C5@350.02,1021.44 ; R3.1@1790.75,596.45 1790.75,553.22 v1(1792.41,551.56)
  L03_SIG1 w4.5: v1(856.32,338.46) 856.32,165.88 953.53,68.67 1393.67,68.67 v1(1412.21,87.21)
  L05_SIG2 w4: v1(153.43,1143.06) 243.64,1233.28 243.64,1397.92 369.93,1524.2 500.2,1524.2 587.67,1611.67 1782.33,1611.67 1947.8,1446.2 1947.8,570.8 1910.63,533.63 1840.29,533.63 1822.36,551.56 v1(1792.41,551.56) 1792.41,534.59 1855,472 1855,340.5 1824.6,310.1 1824.6,178.6 1740,94 1709.65,94 1565.79,-49.86 1535,-49.86 1529.76,-55.1 1498.97,-55.1 1487.99,-44.13 1487.99,11.42 v1(1412.21,87.21)
  Bottom Layer w5.66: v1(153.43,1143.06) 176.24,1120.25 176.24,1105.96 205.63,1076.57 294.89,1076.57 v1(334.27,1037.19) ; v1(856.32,338.46) 856.68,338.11 856.68,253.54 J1.64@857.03,253.19
MCU_GPIO11: J3.116 U1.A4 | length 2803.6
  Top Layer w5.66: U1.A4@318.53,1084.43 318.53,1141.63 294.6,1165.56 294.6,1513.6 485.18,1704.18 v1(530.18,1704.18)
  L03_SIG1 w4.5: v1(530.18,1704.18) 552,1726 625.86,1726 628.11,1726 ccw(c628.11,1739.75) 641.86,1739.75 641.86,1745 cw(c655.61,1745) 669.36,1745 669.36,1709.75 ccw(c683.11,1709.75) 696.86,1709.75 696.86,1745 cw(c710.61,1745) 724.36,1745 724.36,1709.75 ccw(c738.11,1709.75) 751.86,1709.75 751.86,1712.25 cw(c765.61,1712.25) 765.61,1726 785,1726 1323.48,1726 1351.48,1754 1536.58,1754 1639.58,1651 1850.03,1651 1883.69,1617.34 2217.19,1617.34 v1(2239.84,1594.69)
  Bottom Layer w5.66: J3.116@2178.19,1594.78 2239.75,1594.78 v1(2239.84,1594.69)
MCU_GPIO12: J1.16 U1.A3 | length 2828.1
  Top Layer w5.66: U1.A3@287.03,1084.43 287.03,1122.28 270.19,1139.12 270.19,1560.27 302,1592.08 v1(302,1614)
  L03_SIG1 w4.5: v1(302,1614) 321.64,1633.64 461.26,1633.64 498.61,1596.29 498.61,1499.89 731.37,1267.13 731.37,1210.48 673.45,1152.55 673.45,1110.97 730.32,1054.1 730.32,1039.42 747.41,1022.32 791.07,1022.32 797.22,1028.47 836.21,1028.47 847.08,1017.6 847.08,920.18 876.85,890.42 952.8,890.42 1014,829.22 1014,678.58 1094.2,598.38 1319.62,598.38 1385,533 1385,470.73 v1(1531.36,324.37)
  Bottom Layer w5.66: J1.16@1526.44,253.19 1526.44,306.95 1531.36,311.87 v1(1531.36,324.37)
MCU_GPIO13: J1.14 U1.A2 | length 2902.8
  Top Layer w5.66: v1(238.12,1597.36) 238.12,1124.8 255.53,1107.4 U1.A2@255.53,1084.43
  L03_SIG1 w4.5: v1(238.12,1597.36) 238.12,1620.62 266.84,1649.34 471.2,1649.34 516.3,1604.24 516.3,1503.43 744,1275.73 744,1205.25 702.68,1163.92 702.68,1132.47 742.76,1092.39 742.76,1064.5 754.31,1052.95 838.1,1052.95 861.23,1029.81 861.23,932.87 885.65,908.45 967.93,908.45 1031.15,845.23 1031.15,685.48 1101.3,615.32 1325.68,615.32 1410.91,530.09 1410.91,493.25 1558.24,345.91 v1(1558.24,321.57)
  Bottom Layer w5.66: J1.14@1546.12,253.19 1546.12,309.45 v1(1558.24,321.57)
MCU_GPIO14: J2.59 U1.B3 | length 1368.4
  Top Layer w5.66: v1(270.42,1597.36) 257.82,1584.77 257.82,1130.41 271.28,1116.95 271.28,1068.68 U1.B3@287.03,1052.94
  L08_SIG3 w4.5: v1(37.89,1040) 23.32,1054.57 23.32,1468.16 62.35,1507.19 222.19,1507.19 270.42,1555.42 v1(270.42,1597.36)
  Bottom Layer w5.66: J2.59@12.41,1063.37 35.22,1063.37 37.89,1060.7 v1(37.89,1040)
MCU_GPIO15: J1.68 U1.C4 | length 4023
  Top Layer w5.66: v1(302.78,1037.19) U1.C4@318.53,1021.44
  L08_SIG3 w4.5: v1(833.94,357.05) 833.94,356.9 817.62,340.59 817.62,300.88 919.5,199 1335,199 1384,150 1408.74,150 1421.83,163.09 v1(1423.87,163.09)
  L05_SIG2 w4: v1(302.78,1037.19) 302.78,1182.03 307.08,1186.33 307.08,1339.5 400.55,1432.97 401.7,1432.97 ; 401.71,1432.99 523.96,1432.99 585.52,1494.55 673.07,1494.55 673.68,1493.93 693.56,1493.93 695.39,1493.93 696,1494.55 899.64,1494.55 925.1,1469.08 925.1,1466.84 928.94,1463 1218,1463 1286.91,1394.09 1286.91,1376.28 1320.1,1343.08 1322.02,1343.08 1349.41,1315.69 1349.41,1279.93 1405.03,1224.31 1410.89,1224.31 1526.84,1108.36 1526.84,1076.4 1539.24,1064 1539.3,1064 1539.44,1063.86 1553.61,1063.86 1553.75,1064 1618.5,1064 1627.15,1055.35 1627.15,1003.71 1542.8,919.36 1542.8,509.8 1454.66,421.66 1432.6,421.66 1418.83,435.43 1387.43,435.43 1373.2,421.2 1373.2,386.9 1376.9,383.2 1376.9,382.92 1386.92,372.9 1387.2,372.9 1388.02,372.08 1490.92,372.08 1516,347 1516,230.28 1448.72,163 v1@1421.96,163
  Bottom Layer w5.66: 817.62,337.51 817.62,340.73 v1(833.94,357.05) ; J1.68@817.64,253.21 817.64,337.49
MCU_GPIO16: R81.2 R84.2 U1.D5 | length 266
  Top Layer w5.66: R81.2@138.91,986.52 139.11,986.72 v1(174.14,986.72) ; R84.2@141,946.24 R81.2@141,986.62 ; v1(334.27,1005.69) U1.D5@350.02,989.94
  Bottom Layer w5: v1(174.14,986.72) 198.89,986.72 202.37,990.19 318.77,990.19 v1(334.27,1005.69)
MCU_GPIO17: J1.10 U1.B2 | length 2977.5
  Top Layer w5.66: v1(216.58,1562.09) 225,1553.66 225,1112.58 239.79,1097.8 239.79,1068.68 U1.B2@255.53,1052.94
  L03_SIG1 w4.5: v1(216.58,1562.09) 216.58,1628.75 255.6,1667.77 470.62,1667.77 536.18,1602.21 536.18,1535.37 759.37,1312.18 759.37,1249.48 771.15,1237.71 772.46,1237.71 782.56,1227.6 782.56,1213.31 772.46,1203.21 769.72,1203.21 758.81,1192.3 748.91,1192.3 725.72,1169.11 725.72,1134.63 756.08,1104.27 808.7,1104.27 882,1030.97 882,986.76 932.76,936 971.82,936 1048.57,859.25 1048.57,697.53 1108.76,637.34 1329.66,637.34 1454,513 1454,475.07 1584.04,345.03 1584.04,335.8 v1(1586.21,333.62)
  Bottom Layer w5.66: J1.10@1585.49,253.19 1585.85,253.55 1585.85,333.26 v1(1586.21,333.62)
MCU_GPIO18: J1.66 R23.1 U1.F2 | length 5341.4
  Top Layer w5.66: v1(239.79,942.7) U1.F2@255.53,926.95 ; v1@1750.74,558.04 R23.1@1750.74,596.45
  L03_SIG1 w4.5: v1(836.69,309.45) 836.69,140.1 921.42,55.37 1411.82,55.37 1505.2,-38 v1(1507,-38)
  L05_SIG2 w4: v1@175.89,1028.26 159.9,1044.25 155.33,1048.82 155.33,1116.33 159.9,1120.9 174.77,1135.77 256.08,1217.08 256.08,1395.93 374.15,1514 509,1514 594.3,1599.3 1778.88,1599.3 1937.6,1440.58 1937.6,577.6 1903.83,543.83 1857.17,543.83 1828,573 1767.1,573 v1(1751.44,557.34) 1731.55,537.45 1683.27,537.45 1644,498.18 1644,402 1739.44,306.56 1739.44,262.5 1721.11,244.17 1721.11,217.47 1616,112.36 1616,51 1527,-38 v1(1507,-38)
  Bottom Layer w5.66: v1@175.89,1028.26 157.51,1009.88 157.51,961.99 176.79,942.7 v1(239.79,942.7) ; v1@837.02,309.45 837.02,253.52 J1.66@837.34,253.19
  other v1: 173.89,1028.26
MCU_GPIO19: J2.54 U1.B1 | length 767
  Top Layer w5.66: v1(-274.84,1122.51) -145.26,1252.1 144.9,1252.1 190.16,1206.84 190.16,1135.77 190.16,1086.81 U1.B1@224.04,1052.94
  Bottom Layer w5.66: v1(-274.84,1122.51) -274.75,1122.42 J2.54@-213.19,1122.42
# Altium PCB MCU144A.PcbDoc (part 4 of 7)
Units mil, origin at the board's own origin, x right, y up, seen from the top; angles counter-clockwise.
Board outline 2755.9 x 2276.49 mil, 10 copper layers (Top Layer, L02_GND1, L03_SIG1, L04_GND2, L05_SIG2, L06_PWR, L07_GND3, L08_SIG3, L09_GND4, Bottom Layer), stack 60.4 mil thick; 253 components, 312 nets, 1289 pads, 832 vias.

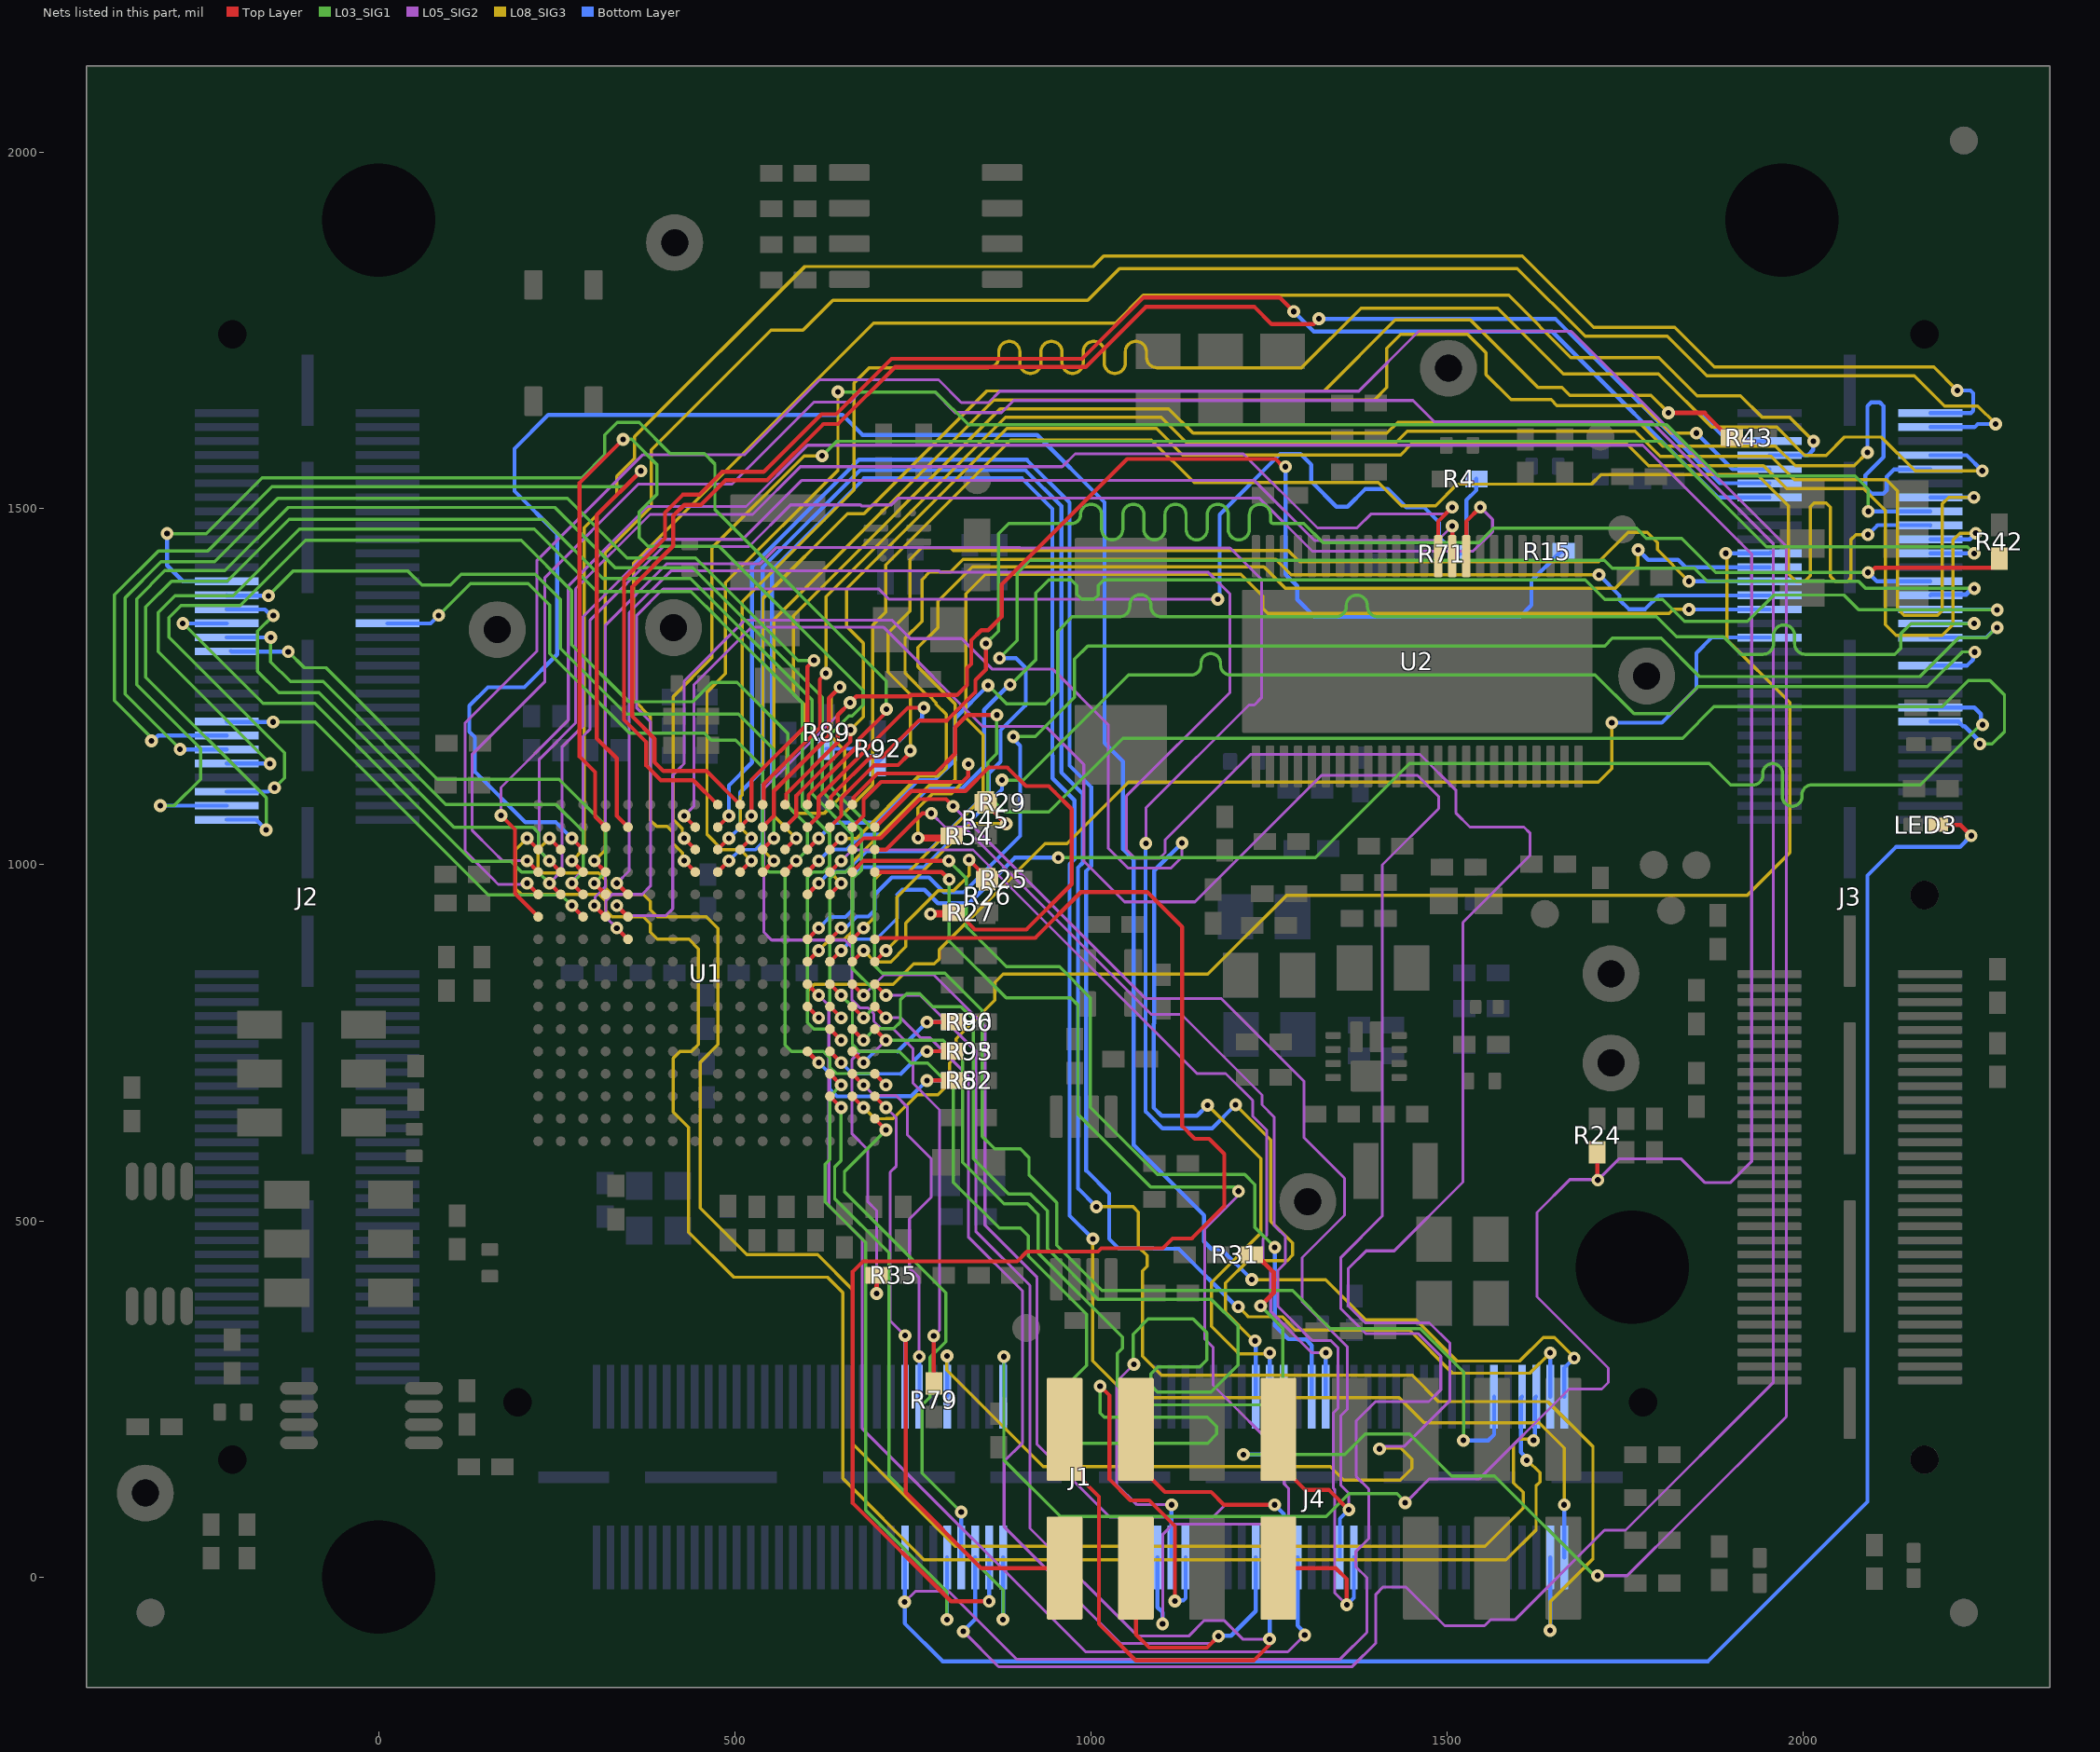
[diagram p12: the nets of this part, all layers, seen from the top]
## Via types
v1: diameter 18, hole 8, Top Layer to Bottom Layer, tented both sides, 776 vias
v2: diameter 19.68, hole 7.87, Top Layer to Bottom Layer, tented top, 54 vias
v3: diameter 18/18/18/18/18/18/18/18/18/18 (per signal layer), hole 8, Top Layer to Bottom Layer, tented both sides, 2 vias

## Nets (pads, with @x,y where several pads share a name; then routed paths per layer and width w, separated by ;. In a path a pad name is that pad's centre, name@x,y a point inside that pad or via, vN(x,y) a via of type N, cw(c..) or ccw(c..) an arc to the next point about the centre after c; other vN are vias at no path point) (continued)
MCU_GPIO20: J1.8 U1.C1 | length 2588.7
  Top Layer w5.66: v1(208.29,1037.19) U1.C1@224.04,1021.44
  L08_SIG3 w4.5: v1(208.29,1037.19) 192.58,1021.48 192.58,966.42 200.52,958.48 309.22,958.48 318.53,949.17 318.53,936.23 327.78,926.97 371.66,926.97 381.29,917.34 381.29,905.52 391.35,895.47 435.53,895.47 449,882 449,748 439.06,738.06 422.94,738.06 413.33,728.45 413.33,653.02 435,631.34 435,484.35 498.35,421 630.07,421 651.69,399.38 651.69,138.39 765.68,24.4 1582.86,24.4 1624.79,66.32 1624.79,128.13 1630.31,133.66 1630.31,146.34 1612.86,163.8 v1(1611.47,163.8)
  Bottom Layer w5.66: J1.8@1605.18,253.19 1603.41,251.42 1603.41,175.2 1611.47,167.13 v1(1611.47,163.8)
MCU_GPIO21: J1.6 U1.C2 | length 2464.4
  Top Layer w5.66: v1(239.79,1037.19) U1.C2@255.53,1021.44
  L08_SIG3 w4.5: 229.68,988.81 224,994.49 224,1021.4 v1(239.79,1037.19) ; 231.19,988.81 231.3,988.7 308.78,988.7 309.48,988 309.57,988 318.53,979.04 318.53,967.72 327.77,958.48 371.64,958.48 381.28,948.84 381.28,937.03 391.32,926.99 460.01,926.99 476.44,910.56 476.44,747.9 451.19,722.65 451.19,517.95 516.64,452.5 616.43,452.5 665.55,403.37 665.55,187.03 809.48,43.1 1553.03,43.1 1606.55,96.63 1606.55,119.02 1593.16,132.41 1593.16,185.97 1600.66,193.47 1619.6,193.47 v1(1621.24,191.83)
  Bottom Layer w5.66: v1(1621.24,191.83) 1623.05,193.65 1623.05,251.38 J1.6@1624.86,253.19
MCU_GPIO22: J1.62 R24.1 U1.F1 | length 5033
  Top Layer w5.66: v1(171.68,1069.32) 191.3,1049.7 191.3,959.69 U1.F1@224.04,926.95 ; R24.1@1710.74,596.45 1710.74,558.04 v1(1711.44,557.34)
  L03_SIG1 w4.5: v1(877.66,309.45) 877.66,164.49 957.14,85 1330.13,85 1362.13,117 1429.32,117 v1@1441.11,105.21
  L05_SIG2 w4: v1(171.68,1069.32) 171.68,1108.63 266.28,1203.23 266.28,1391.7 377.58,1503 516,1503 602.1,1589.1 1774.65,1589.1 1927.4,1436.35 1927.4,583.41 1898.02,554.03 1861.39,554.03 1828.04,587.38 1741.48,587.38 v1(1711.44,557.34) ; v1(1441.11,104.21) 1474.9,138 1545.19,138 1671.19,264 1717,264 1726.1,273.1 1726.1,293.5 1626,393.6 1626,512 1672.04,558.04 v1@1710.74,558.04
  Bottom Layer w5.66: J1.62@877.98,253.52 v1@877.98,309.45
MCU_GPIO23: J1.75 LED3.2 U1.B8 | length 6432.1
  Top Layer w5.66: v1(428.76,1068.68) U1.B8@444.51,1052.94 ; LED3.2@2189.55,1055.99 2220.56,1055.99 v1(2235.62,1040.92)
  L05_SIG2 w4: v1(428.76,1068.68) 442.86,1082.78 442.86,1253.16 523.1,1333.39 709.05,1333.39 848.34,1194.1 936.7,1194.1 989.86,1140.94 989.86,1005.14 1047,948 1145.99,948 1323.52,1125.54 1458.28,1125.54 1488,1095.82 1488,1079 1409,1000 1409,507 1350.8,448.8 1350.8,376.55 1385.26,342.09 1458.91,342.09 1491,310 1491,263 1474.34,246.34 1399.41,246.34 1372.01,218.94 1372.01,141.46 1390,123.48 1390,53.92 1371.34,35.26 1371.34,14.84 1387.22,-1.04 1387.22,-77.78 1349.7,-115.3 895.3,-115.3 799.96,-19.96 753.5,-19.96 v1(738.44,-35.02)
  Bottom Layer w5.66: J1.75@738.92,27.59 738.68,27.35 738.68,-34.78 v1(738.44,-35.02) 738.44,-64.91 791.76,-118.22 1866.09,-118.22 2090,105.69 2090,985 2130,1025 2219.7,1025 v1(2235.62,1040.92)
MCU_GPIO24: J3.100 U1.C8 | length 2419.9
  Top Layer w5.66: v1(428.76,1037.19) U1.C8@444.51,1021.44
  L03_SIG1 w4.5: v1(622.51,1574.17) 643.03,1594.69 1800.37,1594.69 1948.36,1446.7 2230.27,1446.7 v1(2239.84,1437.21) v1(2239.84,1437.21)
  L08_SIG3 w4.5: v1(428.76,1037.19) 426.27,1039.68 426.27,1050.67 415.97,1060.97 413.26,1063.68 413.26,1135.77 413.26,1236.18 468,1290.92 468,1444.87 597.3,1574.17 v1(622.51,1574.17)
  Bottom Layer w5.66: J3.100@2178.19,1437.3 2239.75,1437.3 v1(2239.84,1437.21)
MCU_GPIO25: J3.113 U1.D8 | length 2452
  Top Layer w5.66: v1(428.76,1005.69) U1.D8@444.51,989.94
  L08_SIG3 w4.5: v1(428.76,1005.69) 426.6,1007.85 426.6,1016.86 412.92,1030.54 412.92,1046.08 405,1054 390.29,1054 381.55,1062.74 381.55,1207.81 357.67,1231.7 357.67,1423.67 694.6,1760.6 1034.22,1760.6 1073.32,1799.71 1586.29,1799.71 1673.74,1712.26 1797.14,1712.26 1850.95,1658.45 1911.93,1658.45 1941.73,1628.65 1980.28,1628.65 v1(2014.24,1594.69)
  Bottom Layer w5.66: J3.113@1952.59,1575.1 2006.1,1575.1 2013.6,1582.6 2013.6,1594.05 v1(2014.24,1594.69)
MCU_GPIO26: J1.4 U1.B9 | length 2752
  Top Layer w5.66: U1.B9@476.01,1052.94 v1(491.75,1068.68)
  L08_SIG3 w4.5: v1(1206.9,379.5) 1216.78,369.61 1221.03,365.37 1268.63,365.37 1287.12,346.88 1446.97,346.88 1507.6,286.24 1616.04,286.24 v1(1644.64,314.84)
  Bottom Layer w5.66: v1(491.75,1068.68) 491.75,1111.4 524,1143.65 524,1418.8 673.85,1568.64 909.91,1568.64 970,1508.55 970,1139.41 1000.19,1109.21 1000.19,998.21 993.32,991.34 993.32,570.68 1025.43,538.57 1025.43,474.78 1038.7,461.51 1053.19,461.51 ; 1053.22,461.54 1087.84,461.54 1088.38,461 1123,461 1204.5,379.5 v1(1206.9,379.5) ; J1.4@1644.55,253.19 1644.55,314.75 v1(1644.64,314.84)
MCU_GPIO27: J1.3 U1.C9 | length 3271.5
  Top Layer w5.66: U1.C9@476.01,1021.44 v1(491.75,1037.19)
  L08_SIG3 w4.5: v1(1007.6,519.85) 1059.36,519.85 1066.67,512.54 1066.67,463.54 1078.92,451.3 1078.92,436.12 1072.45,429.66 1072.45,309.95 1099.1,283.3 1450.86,283.3 1487.81,246.34 1641.18,246.34 1704.6,182.92 1704.6,25.4 1644.46,-34.75 v1(1644.46,-75)
  Bottom Layer w5: v1(491.75,1037.19) 507.75,1053.18 507.75,1092.38
  Bottom Layer w5.66: 507.75,1092.38 507.75,1101.75 538.96,1132.96 538.96,1417.27 675.85,1554.15 907.91,1554.15 958.34,1503.72 958.34,1129.66 988.53,1099.47 988.53,1003.04 981.66,996.17 981.66,545.79 v1(1007.6,519.85) ; v1(1644.46,-75) J1.3@1644.55,27.59
MCU_GPIO28: J1.1 U1.D9 | length 3024.2
  Top Layer w5.66: U1.D9@476.01,989.94 v1(491.75,1005.69)
  L08_SIG3 w4.5: v1(1002.47,474.88) 1002.47,303.53 1053.9,252.1 1428.75,252.1 1428.9,251.95 1432.41,251.95 1467.76,216.6 1629.04,216.6 1664.23,181.41 v1(1664.23,101.47)
  Bottom Layer w5: v1(491.75,1005.69) 507.25,1021.19 529.17,1021.19 538.96,1030.98 538.96,1086.96
  Bottom Layer w5.66: 538.96,1086.96 538.96,1111.95 552.09,1125.08 552.09,1413.35 681.24,1542.49 903.08,1542.49 945.69,1499.88 945.69,1153.31 946,1153 946,1121.37 976.87,1090.49 976.87,1007.87 970,1001 970,507.36 v1(1002.47,474.88) ; J1.1@1664.23,27.59 v1(1664.23,101.47)
MCU_GPIO29: J3.107 U1.A9 | length 2307.2
  Top Layer w5.66: U1.A9@476.01,1084.43 441.72,1118.71 396.26,1118.71 375.7,1139.28 375.7,1172.24 344.45,1203.48 344.45,1401.24 401.95,1458.74 401.95,1494.67 426.88,1519.61 450.22,1519.61 482.29,1551.68 540.53,1551.68 621.45,1632.6 642.05,1632.6 719.96,1710.5 987.66,1710.5 1073.84,1796.69 1264.73,1796.69 v1(1284.53,1776.89)
  Bottom Layer w5.66: v1(1284.53,1776.89) 1312.62,1748.75 1647.23,1748.75 1879.94,1516.04 J3.107@1952.59,1516.04
MCU_GPIO30: J3.109 U1.A10 | length 2296.6
  Top Layer w5.66: U1.A10@507.5,1084.43 460.09,1131.85 399.62,1131.85 387.36,1144.11 387.36,1177.07 356.11,1208.31 356.11,1390.35 413.61,1447.84 413.61,1489.84 429.13,1505.36 452.47,1505.36 487.12,1540.02 545.36,1540.02 624.34,1619 644.94,1619 724.79,1698.84 992.49,1698.84 1076.88,1783.23 1229.47,1783.23 1253.64,1759.06 1312.49,1759.06 v1(1320.01,1766.58)
  Bottom Layer w5.66: v1(1320.01,1766.58) 1651.79,1766.58 1715.71,1702.66 1773.34,1645.03 1882.64,1535.73 J3.109@1952.59,1535.73
MCU_GPIO31: J2.50 U1.B10 | length 1706.2
  Top Layer w5.66: U1.B10@507.5,1052.94 v1(523.25,1068.68) 523.25,1118.93 601.99,1197.68 601.99,1277.99 v1(611,1287)
  L03_SIG1 w4.5: v1(-278.75,1162.41) -356,1239.66 -356,1374.86 -305.23,1425.63 -230.37,1425.63 -141.57,1514.43 252.42,1514.43 252.48,1514.37 265.22,1514.37 348.59,1431 444.78,1431 588.78,1287 v1(611,1287)
  Bottom Layer w5.66: v1(-278.75,1162.41) -278.13,1161.79 J2.50@-213.19,1161.79
MCU_GPIO32: J1.63 U1.G16 | length 2102.1
  Top Layer w5.66: U1.G16@696.48,895.46 698.03,897.01 703.52,897.01 703.85,897.34 747.82,897.34 921.66,897.34 985.98,961.66 1078.99,961.66 1128.1,912.55 1128.1,632.79 1145.57,615.32 1165.87,615.32 1187.01,594.18 1187.01,520.93 1141.48,475.39 1114.61,475.39 1100.76,461.54 1014.34,461.54 1009.86,457.05 910.18,457.05 896.45,443.33 680.04,443.33 665.55,428.83 665.55,103.8 803.41,-34.06 v1(856.94,-34.06)
  Bottom Layer w5.66: v1(856.94,-34.06) 857.03,-33.97 J1.63@857.03,27.59
MCU_GPIO33: J1.61 U1.P14 | length 930.1
  Top Layer w5.66: U1.P14@633.49,674.98 v1(649.23,659.24)
  L03_SIG1 w4.5: v1(649.23,659.24) 649.23,584.56 640.15,575.48 640.15,531.16 716.13,455.19 716.13,142.16 876.52,-18.23 v1(876.52,-59.66)
  Bottom Layer w5.66: v1(876.52,-59.66) 876.65,-59.54 J1.61@876.65,27.53
MCU_GPIO34: J1.65 U1.D1 | length 5145.3
  Top Layer w5.66: v1(208.29,1005.69) U1.D1@224.04,989.94
  L05_SIG2 w4: v1(208.29,1005.69) 173.88,1005.69 159.9,1019.67 131.4,1048.18 131.4,1155.4 233.44,1257.44 233.44,1403.44 364.4,1534.4 495.98,1534.4 611.39,1649.82 662.18,1649.82 676.28,1663.92 780.08,1663.92 809.07,1634.93 874.4,1634.93 891.38,1651.92 1452.08,1651.92 1482.13,1621.87 1786.71,1621.87 1958,1450.58 1958,273.5 1750.29,65.79 1720.79,65.79 1594.94,-60.06 1560.71,-60.06 1552.33,-68.45 1496.45,-68.45 1442,-14 1410,-14 1400,-24 1400,-92.54 1366.8,-125.75 1284.44,-125.75 1284.31,-125.88 870.31,-125.88 v1(820.88,-76.45)
  Bottom Layer w5.66: v1(820.88,-76.45) 820.88,-75.94 837.28,-59.54 J1.65@837.28,27.53
MCU_GPIO35: J1.42 U1.E1 | length 4915.3
  Top Layer w5.66: v1(208.29,974.2) U1.E1@224.04,958.45
  L03_SIG1 w4.5: v1(1214,172) 1356,172 1385.04,201.04 1447.06,201.04 1505.85,142.25 1566.37,142.25 1706.62,2 v1(1711,2)
  L05_SIG2 w4: v1(208.29,974.2) 206.71,972.62 167.83,972.62 159.9,980.54 121.2,1019.25 121.2,1198.93 222,1299.73 222,1426.85 371.15,1576 514,1576 619,1681 786,1681 818,1649 856,1649 872,1665 1376,1665 1460,1749 1674,1749 1976,1447 1976,1417.12 1976,298.64 1976,225.22 1835.53,84.76 1835.44,84.76 1752.68,2 v1(1711,2)
  Bottom Layer w5.66: v1(1214,172) 1250.92,172 1271.34,192.43 1271.34,252.38 J1.42@1270.53,253.19
MCU_GPIO36: J1.69 U1.N14 | length 940.2
  Top Layer w5.66: U1.N14@633.49,706.48 v1(649.23,690.73)
  L03_SIG1 w4.5: v1(649.23,690.73) 633.24,674.74 633.24,640.24 633.24,586.42 626.65,579.83 626.65,526.81 683.72,469.74 683.72,93.88 797.78,-20.18 v1(797.78,-59.66)
  Bottom Layer w5.66: v1(797.78,-59.66) 797.91,-59.54 J1.69@797.91,27.53
MCU_GPIO37: J1.67 U1.R16 | length 1004.7
  Top Layer w5.66: U1.R16@696.48,643.49 v1(712.23,627.74)
  L03_SIG1 w4.5: 761.41,433.52 738.18,456.74 653.92,541 ; v1(817.77,91.2) 763.05,145.92 763.05,241.31 774.2,252.46 774.2,308.47 796,330.27 796,398.93 653.92,541 ; 653.92,541 653.92,569.44 ; 653.92,541 653.92,569.44 ; 653.92,569.44 v1(712.23,627.74) 653.92,569.44
  Bottom Layer w5.66: J1.67@817.66,27.59 J1.67@817.66,27.59 817.71,91.15 v1(817.77,91.2)
MCU_GPIO38: J3.104 U1.E14 | length 2491.1
  Top Layer w5.66: U1.E14@633.49,958.45 v1(649.23,974.2)
  L08_SIG3 w4.5: v1(649.23,974.2) 633.23,990.2 633.23,1052.55 633.52,1052.84 693.25,1112.57 693.25,1336.25 711.81,1354.81 711.81,1421.24 887.13,1596.55 1084.93,1596.55 1144.8,1536.69 1253.79,1536.69 1254.05,1536.95 1403.43,1536.95 1436.1,1504.28 1483.53,1504.28 1513.73,1534.48 1702.66,1534.48 1716.09,1547.91 1935.28,1547.91 1979,1504.19 1979,1408.33 1989.33,1398 2002,1398 2010,1406 2010,1502.7 2015.3,1508 2032,1508 2038,1502 2038,1405 2045,1398 2062,1398 2067,1403 2067,1456.73 2073.71,1463.45 v1(2090.69,1463.45)
  Bottom Layer w5.66: v1(2090.69,1463.45) 2104.16,1476.91 2177.95,1476.91 J3.104@2178.19,1476.67
MCU_GPIO39: J3.99 U1.P15 | length 2050.3
  Top Layer w5.66: U1.P15@664.98,674.98 v1(680.73,659.24)
  L08_SIG3 w4.5: v1(680.73,659.24) 696.51,643.45 712.31,643.45 712.38,643.52 722.35,643.52 756.08,677.25 784.84,677.25 801.36,693.77 801.36,721.39 810.37,730.4 810.37,755.51 865,810.14 865,834.97 876.45,846.42 1164.07,846.42 1274.52,956.87 1920.85,956.87 1980.98,1016.99 1980.98,1228.02 1892.42,1316.58 1892.42,1435.92 v1(1890.94,1437.39)
  Bottom Layer w5.66: v1(1890.94,1437.39) 1891.03,1437.3 J3.99@1952.59,1437.3 J3.99@1953.81,1438.52
MCU_GPIO40: J1.76 J4.16 U1.P16 | length 943
  Top Layer w5.66: U1.P16@696.48,674.98 v1(712.23,659.24) ; v1@739.89,343.27 739.89,118.47 845.8,12.56 J4.16@963,12.56
  L05_SIG2 w4: v1(712.23,659.24) 726.73,644.74 726.73,577.15 718.06,568.49 718.06,560.65 718.06,359.94 v1(739,339)
  Bottom Layer w5.66: J1.76@738.92,253.19 738.92,338.93 739.89,339.9 v1@739.89,343.27
MCU_GPIO41: J1.74 U1.N15 | length 534.9
  Top Layer w5.66: U1.N15@664.98,706.48 v1(680.73,690.73)
  L05_SIG2 w4: v1(680.73,690.73) 695.16,676.3 725.94,676.3 741.98,660.25 741.98,621.21 775.32,587.87 775.32,532.92 745.16,502.77 745.16,433.63 758.89,419.91 v1(758.89,309.45)
  Bottom Layer w5.66: J1.74@759.22,253.52 v1@759.22,309.45
MCU_GPIO42: J1.31 J4.10 U1.C16 | length 1732.2
  Top Layer w5.66: U1.C16@696.48,1021.44 712.34,1021.44 763.26,1072.36 v1(775.83,1072.36) ; J4.10@1263,12.56 1343.44,12.56 1359,-3 v1(1359,-39)
  L05_SIG2 w4: v1(775.83,1072.36) 795.19,1053 821.59,1053 1084.59,790 1126.82,790 1240,676.82 1240,663 1257.21,645.79 1257.21,493.79 1273,478 1273,441.31 1262.5,430.81 1262.5,379.71 1287.09,355.12 1287.09,355.06 1308.55,333.6 1308.98,333.6 1310.63,331.94 1336.76,331.94 1346.78,321.92 1346.78,236.99 1340.46,230.67 1340.46,124.63 1342,123.1 1342,-22 v1(1359,-39)
  Bottom Layer w5.66: v1(1359,-39) 1368.96,-29.04 J1.31@1368.96,27.59
MCU_GPIO43: J1.33 J4.9 U1.C15 | length 1757.6
  Top Layer w5.66: U1.C15@664.98,1021.44 680.73,1037.19 704.52,1037.19 759.47,1092.14 796.43,1092.14 v1(806.38,1082.2) ; J4.9@1263,207.44 1263,160 1300.85,122.15 1334.15,122.15 1361.6,94.7 v1(1362.02,94.7)
  L05_SIG2 w4: v1(806.38,1082.2) 806.81,1082.2 1077.02,812 1183.15,812 1298.8,696.35 1298.8,617.18 1356,559.98 1356,508 1296.46,448.46 1296.46,386.67 1359.73,323.4 1359.73,235.51 1350.66,226.45 1350.66,128.86 1362.02,117.5 v1(1362.02,94.7)
  Bottom Layer w5.66: J1.33@1349.27,27.59 1349.27,81.95 v1(1362.02,94.7)
MCU_GPIO44: J3.88 U1.G14 | length 2120.6
  Top Layer w5.66: U1.G14@633.49,895.46 v1(649.23,911.2)
  L03_SIG1 w4.5: v1(891,1180) 922,1180 977,1235 977,1288.69 995.43,1307.11 1721.08,1307.11 1732.02,1318.06 1800.47,1318.06 1854.25,1264.27 2163.27,1264.27 2218.19,1319.19 2256.95,1319.19 2270.76,1333 v1(2272,1333)
  Bottom Layer w5: v1(649.23,911.2) 651.72,913.69 657.7,913.69 671.21,927.2 687.15,927.2 696.45,936.5 696.45,958.42
  Bottom Layer w5.66: 696.45,958.42 720.25,982.22 772.74,982.22 793.51,961.45 821.45,961.45 900.66,1040.66 900.66,1167.27 891,1176.93 v1(891,1180) ; J3.88@2178.19,1319.19 2256.95,1319.19 2270.76,1333 v1(2272,1333)
MCU_GPIO45: J3.91 U1.G15 | length 1767.5
  Top Layer w5.66: U1.G15@664.98,895.46 v1(680.73,911.2)
  L08_SIG3 w4.5: v1(680.73,911.2) 696.04,926.52 696.04,979.67 706.32,989.94 743.71,989.94 776.08,1022.32 848.58,1094.81 848.58,1182.06 824.23,1206.41 824.23,1380.38 851.65,1407.81 1210.4,1407.81 1241.12,1377.09 1241.12,1360.27 1248.39,1353 1811.79,1353 1817.35,1358.56 v1(1839.26,1358.56)
  Bottom Layer w5.66: v1(1839.26,1358.56) J3.91@1952.59,1358.56
MCU_GPIO46: J1.36 U1.D14 | length 1226.6
  Top Layer w5.66: U1.D14@633.49,989.94 v1(649.23,1005.69)
  L05_SIG2 w4: v1(649.23,1005.69) 664.6,1021.05 834.61,1021.05 1148.66,707 1189.17,707 1227,669.17 1227,647 1246.6,627.4 1246.6,479.6 1241.17,474.17 1241.17,441.83 1252.2,430.8 1252.2,372.8 1310.16,314.84 v1(1329.68,314.84)
  Bottom Layer w5.66: J1.36@1329.59,253.19 1329.59,314.75 v1(1329.68,314.84)
MCU_GPIO47: J1.38 U1.D15 | length 1236.3
  Top Layer w5.66: U1.D15@664.98,989.94 680.73,1005.69 v1(800.34,1005.69)
  L03_SIG1 w4.5: v1@800.38,1005.69 825,981.07 825,913.15 881.36,856.79 955.71,856.79 999.18,813.32 999.18,659.26 1093.44,565 1215.89,565 1230,550.89 1230,490.97 v1(1258,462.97)
  Bottom Layer w5.66: v1(1258,462.97) 1258,352.94 1276.94,334 1289.89,334 1290.06,333.83 1301.17,333.83 1309.9,325.1 J1.38@1309.9,253.19 J1.38@1310.95,252.14
MCU_GPIO48: J2.31 U1.N16 | length 1303.6
  Top Layer w5.66: U1.N16@696.48,706.48 v1(712.23,690.73)
  L03_SIG1 w4.5: v1(84.3,1350.2) 128.98,1394.87 210.27,1394.87 240.16,1364.98 240.16,1296.84 352.29,1184.71 457.06,1184.71 466.86,1174.91 501.38,1174.91 538.96,1137.32 538.96,999.25 548.31,989.91 563.99,989.91 570.53,983.37 570.53,747.22 579.73,738.01 624.18,738.01 633.45,728.74 633.45,715.79 642.33,706.91 696.05,706.91 v1(712.23,690.73)
  Bottom Layer w5.66: J2.31@12.41,1338.96 73.06,1338.96 v1(84.3,1350.2)
MCU_GPIO49: R86.2 R90.2 U1.M15 | length 205.4
  Top Layer w5.66: U1.M15@664.98,737.98 v1(680.73,722.23) ; v1@769.76,779.3 R86.2@805.01,779.3
  Bottom Layer w5: v1(680.73,722.23) 696.5,738 728.46,738
  Bottom Layer w5.66: 728.46,738 v1(769.57,779.1) 769.76,779.3 R90.2@805.01,779.3
MCU_GPIO50: R93.2 R95.2 U1.M14 | length 232.7
  Top Layer w5.66: U1.M14@633.49,737.98 v1(649.23,722.23) ; v1@769.76,738.3 R93.2@805.01,738.3
  Bottom Layer w5: v1(649.23,722.23) 664.96,706.5 733.04,706.5
  Bottom Layer w5.66: 733.04,706.5 762.29,735.74 767.21,735.74 v1(769.57,738.1) ; v1@769.76,738.3 R95.2@805.01,738.3
MCU_GPIO51: R52.2 R82.2 U1.M13 | length 286.4
  Top Layer w5.66: U1.M13@601.99,737.98 v1(617.74,722.23) ; v1@769.76,697.3 R52.2@805.01,697.3
  Bottom Layer w5: v1(617.74,722.23) 633.42,706.55 633.42,684.63 643.31,674.74 722.6,674.74 722.93,675.07
  Bottom Layer w5.66: 722.93,675.07 747.53,675.07 v1(769.57,697.1) ; v1@769.76,697.3 R82.2@805.01,697.3
MCU_GPIO52: J2.52 U1.L14 | length 1958
  Top Layer w5.66: U1.L14@633.49,769.47 v1(649.23,753.72)
  L03_SIG1 w4.5: v1(-152.55,1142.08) -309.59,1299.12 -309.59,1354.5 -286.07,1378.02 -204.26,1378.02 -111.03,1471.25 218.77,1471.25 306.37,1383.66 438.54,1383.66 478.76,1343.43 ; 478.76,1343.41 595,1227.17 595,1081.58 633.45,1043.13 633.45,999.18 624.25,989.98 609.66,989.98 602.03,982.34 602.03,778.71 611.3,769.44 633.52,769.44 v1(649.23,753.72)
  Bottom Layer w5.66: J2.52@-213.19,1142.11 v1@-152.58,1142.11
MCU_GPIO53: J1.57 U1.L15 | length 1773.6
  Top Layer w5.66: U1.L15@664.98,769.47 v1(680.73,753.72)
  L03_SIG1 w4.5: v1(680.73,753.72) 697.01,770 723,770 732.45,779.45 732.45,810.4 741.36,819.31 759.7,819.31 778.06,800.95 817.51,800.95 834.78,783.68 834.78,587.42 884.2,538 915,538 939,514 939,461 1010.35,389.65 1169,389.65 1206.16,352.49 1206.16,297.66 1168.5,260 1093.37,260 1084.02,269.35 1084.02,285.27 1094.02,295.28 1152.59,295.28 1162.35,305.04 1162.35,343.13 1143.29,362.19 1080.19,362.19 1059,341 1059,299.92 v1(1060.21,298.71)
  L05_SIG2 w4: v1(1060.21,298.71) 1036,274.51 1036,130 1064.53,101.47 v1(1113.05,101.47)
  Bottom Layer w5.66: J1.57@1113.05,27.59 v1(1113.05,101.47)
MCU_GPIO54: R31.2 R35.2 U1.L16 | length 1614.7
  Top Layer w5.66: U1.L16@696.48,769.47 v1(712.23,753.72)
  Top Layer w6.63: R31.2@1227.75,452.5 1231.69,452.5 1256.19,428 1256.19,398.77 v1(1238.1,380.68)
  Top Layer w6.66: v1@699.03,400.97 R35.2@699.03,429.69
  L03_SIG1 w4.5: v1(712.23,753.72) 792.28,753.72 819.55,726.45 819.55,582.2 877.75,524 911,524 926,509 926,455 1044,337 1044,321 1037,314 1037,269 1064.23,241.77 1243.13,241.77 1269.41,268.06 1269.41,349.37 v1(1238.1,380.68)
  L05_SIG2 w4: v1@699.03,400.97 699.03,514.62 686.35,527.3 686.35,600.32 664.66,622.01 664.66,726.66 677.22,739.22 697.73,739.22 v1(712.23,753.72)
  other v1: 699.03,397.97
MCU_GPIO55: J3.87 U1.K13 | length 1696.5
  Top Layer w5.66: U1.K13@601.99,800.97 v1(617.74,785.22)
  L08_SIG3 w4.5: v1(617.74,785.22) 602.43,800.53 602.43,823.06 611.4,832.03 722.48,832.03 751.24,860.79 779.91,860.79 787,867.88 787,880.92 856.08,950 856.19,950 935.7,1029.51 966.38,1029.51 1052.8,1115.94 1711.94,1115.94 1731.04,1135.04 v1(1731.04,1199.44)
  Bottom Layer w5.66: v1(1731.04,1199.44) 1801.29,1199.44 1849.74,1247.9 1849.74,1297.43 1871.51,1319.19 J3.87@1952.59,1319.19
MCU_GPIO56: J2.60 U1.K14 | length 2055
  Top Layer w5.66: U1.K14@633.49,800.97 v1(649.23,785.22)
  L03_SIG1 w4.5: v1(-157.84,1049.11) -157.84,1094.16 -326.91,1263.23 -326.91,1361.87 -290.77,1398.01 -212.73,1398.01 -125.48,1485.25 231.28,1485.25 314.45,1402.08 437.97,1402.08 608.51,1231.54 608.51,1099.59 664.96,1043.14 664.96,999.18 655.73,989.94 642.74,989.94 633.23,980.44 633.23,841.23 633.23,801.22 v1(649.23,785.22)
  Bottom Layer w5.66: J2.60@-213.19,1063.37 -172.1,1063.37 v1(-157.84,1049.11)
MCU_GPIO57: J2.58 U1.K15 | length 2100.5
  Top Layer w5.66: U1.K15@664.98,800.97 v1(680.73,785.22)
  L03_SIG1 w4.5: v1(-306.47,1083.05) -286.95,1083.05 -250,1120 -250,1163.29 -339.56,1252.84 -339.56,1373.44 -300,1413 -215.62,1413 -126.81,1501.81 247.19,1501.81 332,1417 440.93,1417 622.79,1235.14 622.79,1103.19 677.61,1048.37 677.61,992.73 665.42,980.54 665.42,854.13 696.04,823.51 696.04,800.53 v1(680.73,785.22)
  Bottom Layer w5.66: v1(-306.47,1083.05) J2.58@-213.19,1083.05
MCU_GPIO58: J1.45 J4.14 U1.K16 | length 1585.5
  Top Layer w5.66: U1.K16@696.48,800.97 v1(712.23,785.22) ; J4.14@1063,12.56 1063,-80.38 1081.71,-99.09 1162.91,-99.09 v1(1179,-83)
  L05_SIG2 w4: v1(712.23,785.22) 732.78,785.22 761,757 774,757 827.78,703.22 827.78,477.48 904,401.26 904,188.55 878,162.55 878,70.56 1041.9,-93.34 1168.66,-93.34 v1(1179,-83)
  Bottom Layer w5.66: v1(1179,-83) 1179.48,-82.52 1196.49,-82.52 1231.16,-47.85 J1.45@1231.16,27.59
MCU_GPIO59: J1.43 J4.15 U1.J16 | length 1979
  Top Layer w5.66: U1.J16@696.48,832.46 v1(712.23,816.72) ; J4.15@963,207.44 963,160.98 1011.18,112.8 1011.18,-65.59 1062.52,-116.92 1228.86,-116.92 v1@1250.64,-95.15
  L05_SIG2 w4: v1(712.23,816.72) 760.31,816.72 838.27,738.76 838.27,485.4 914.2,409.47 914.2,68.42 1065.56,-82.95 1137.12,-82.95 1159.06,-61 1186.83,-61 1212.98,-87.15 v1(1250.64,-87.15)
  Bottom Layer w5.66: v1(1250.64,-87.15) 1250.85,-86.94 J1.43@1250.85,27.59
MCU_GPIO60: J1.41 J4.13 U1.J15 | length 1580.5
  Top Layer w5.66: U1.J15@664.98,832.46 v1(680.73,816.72) ; J4.13@1063,207.44 1063,160 1103.7,119.3 1168.67,119.3 1186.51,101.46 v1(1257.74,101.46)
  L05_SIG2 w4: v1(680.73,816.72) 709.62,845.6 779.25,845.6 851.2,773.65 851.2,493.8 924.4,420.6 924.4,186.19 1026.22,84.37 1171.44,84.37 1188.54,101.46 v1(1257.74,101.46)
  Bottom Layer w5.66: v1(1257.74,101.46) 1270.53,88.68 J1.41@1270.53,27.59
MCU_GPIO61: J1.39 U1.J13 | length 1529.7
  Top Layer w5.66: U1.J13@601.99,832.46 v1(617.74,816.72)
  L05_SIG2 w4: v1(617.74,816.72) 632,802.45 632,521.46 679,474.46 679,208.21 992.31,-105.1 1276.24,-105.1 v1(1299.99,-81.35)
  Bottom Layer w5.66: J1.39@1290.22,27.59 1290.22,-68.23 1299.99,-78.01 v1(1299.99,-81.35)
MCU_GPIO62: J3.97 U1.H13 | length 1899.4
  Top Layer w5.66: U1.H13@601.99,863.96 v1(617.74,879.71)
  L08_SIG3 w4.5: v1(617.74,879.71) 633.03,895 653.18,895 654.89,896.7 655.24,896.7 664.73,906.2 664.73,980.62 ; 664.72,980.63 664.72,995.05 665.17,995.5 665.17,1004.4 772.41,1111.63 800.63,1111.63 809.3,1120.3 809.3,1225.7 757,1278 757,1305 785,1333 785,1370 833.31,1418.31 1242.69,1418.31 1273,1388 1735.8,1388 1767.98,1420.18 v1(1767.98,1442.17)
  Bottom Layer w5.66: v1(1767.98,1442.17) 1782,1428.15 1824.17,1428.15 1834.7,1417.62 J3.97@1952.59,1417.62
MCU_GPIO63: J3.78 U1.H14 | length 1991.1
  Top Layer w5.66: U1.H14@633.49,863.96 v1(649.23,879.71)
  L03_SIG1 w4.5: v1(954,1010) 1315,1010 1447.15,1142.15 1867.85,1142.15 1897.87,1112.13 1927.02,1112.13 1929.27,1112.13 ccw(c1929.27,1125.88) 1943.02,1125.88 1943.02,1128.38 cw(c1956.77,1128.38) 1970.52,1128.38 1970.52,1095.88 ccw(c1984.27,1095.88) 1998.02,1095.88 1998.02,1098.38 cw(c2011.77,1098.38) 2011.77,1112.13 2035,1112.13 2164.28,1112.13 2248.81,1196.66 v1(2251.5,1196.66)
  Bottom Layer w5: v1(649.23,879.71) 665.23,895.7 698.7,895.7 728.09,925.09 728.09,958.09
  Bottom Layer w5.66: 728.09,958.09 735,965 766.07,965 785.07,946 829,946 893,1010 v1(954,1010) ; J3.78@2178.19,1220.77 2240.13,1220.77 2249.14,1211.76 2249.14,1199.02 v1(2251.5,1196.66)
MCU_GPIO64: R25.2 R26.2 U1.H15 | length 307.3
  Top Layer w5.66: U1.H15@664.98,863.96 v1(680.73,879.71) ; v1(828.77,1006.95) 842.86,992.86 845.32,992.86 854.3,983.88 R26.2@854.3,979.94
  L08_SIG3 w4.5: v1(680.73,879.71) 696.73,863.71 718.85,863.71 740.17,885.02 740.17,918.22 785.91,963.97 807.24,963.97 828.77,985.5 v1(828.77,1006.95)
MCU_GPIO65: R29.2 R45.2 U1.H16 | length 338.7
  Top Layer w5.66: U1.H16@696.48,863.96 v1(712.23,879.71) ; R45.2@851.9,1087.58 851.9,1083.64 860.89,1074.66 863.34,1074.66 v1@877.43,1060.57
  L08_SIG3 w4.5: v1(712.23,879.71) 727.54,895.02 727.54,954.55 830.72,1057.73 v1(880.99,1057.73)
MCU_GPIO66: J3.84 U1.G13 | length 1997.2
  Top Layer w5.66: U1.G13@601.99,895.46 v1(617.74,911.2)
  L03_SIG1 w4.5: v1(875,1119) 904.88,1119 1052.46,1266.58 1138.38,1266.58 1140.63,1266.58 ccw(c1140.63,1280.33) 1154.38,1280.33 1154.38,1282.83 cw(c1168.13,1282.83) 1181.88,1282.83 1181.88,1280.33 ccw(c1195.63,1280.33) 1195.63,1266.58 1214,1266.58 1698,1266.58 1707.66,1266.58 1762.17,1212.07 1813.92,1212.07 1851.95,1250.11 2174.11,1250.11 2223,1299 2240.32,1299 v1(2240.63,1298.69)
  Bottom Layer w5: v1(617.74,911.2) 633.24,926.7 655.16,926.7 665.23,936.78 665.23,982.83 679.18,996.78
  Bottom Layer w5.66: 679.18,996.78 765.97,996.78 875,1105.81 v1(875,1119) ; J3.84@2178.19,1279.82 2229.82,1279.82 2238.27,1288.27 2238.27,1296.33 v1(2240.63,1298.69)
MCU_GPIO67: R27.2 U1.B16 | length 709.5
  Top Layer w5.66: U1.B16@696.75,1052.75 747.8,1103.8 823.66,1103.8 856.69,1136.83 882.39,1136.83 908.72,1110.49 940.62,1110.49 948.45,1102.66 972.86,1078.26 972.86,972.77 909.21,909.12 836.92,909.12 814.91,931.12 v1(774.73,931.12)
  Top Layer w10: v1@774.92,931.32 R27.2@810.17,931.32
MCU_GPIO68: R54.2 U1.B15 | length 411.4
  Top Layer w5.66: U1.B15@664.98,1052.94 680.73,1068.68 680.73,1091.9 705.34,1116.51 819.88,1116.51 827.72,1124.36 v1(827.72,1141.2)
  Top Layer w10: v1@757.13,1037.83 R54.2@797.58,1037.83
  L08_SIG3 w4.5: v1(757.13,1037.63) 757.13,1079.5 777.08,1099.45 803.3,1099.45 827.72,1123.87 v1(827.72,1141.2)
MCU_GPIO69: J3.76 U1.A15 | length 2098.4
  Top Layer w5.66: U1.A15@665.52,1084.6 666.54,1085.61 666.54,1094.2 700.51,1128.17 781.39,1128.17 809.3,1156.09 809.3,1193.31 826.25,1210.26 v1(867.78,1210.26)
  L03_SIG1 w4.5: v1(867.78,1210.26) 867.78,1156.09 855.17,1143.48 855.17,1097.72 878.65,1074.24 940.94,1074.24 1044.58,1177.88 1830.43,1177.88 1874.55,1222 2195,1222 2231.67,1258.67 2262.02,1258.67 2282.31,1238.39 2282.31,1186.86 2265.19,1169.75 v1(2247.8,1169.75)
  Bottom Layer w5.66: J3.76@2178.19,1201.08 2217.69,1201.08 2224.04,1194.73 2226.43,1194.73 2245.44,1175.72 2245.44,1172.11 v1(2247.8,1169.75)
MCU_GPIO70: J3.93 U1.C14 | length 1752.1
  Top Layer w5.66: U1.C14@633.49,1021.44 v1(649.23,1037.19)
  L08_SIG3 w4.5: v1(649.23,1037.19) 670.89,1037.19 757.96,1124.26 785.04,1124.26 796.68,1135.9 796.68,1211.32 782.56,1225.44 782.56,1227.6 772.46,1237.71 770.29,1237.71 739,1269 739,1318 762.92,1341.92 762.92,1400.32 773.56,1410.97 802.63,1410.97 820.47,1428.81 1259.19,1428.81 1280.83,1407.17 v1(1713.03,1407.17)
  Bottom Layer w5.66: v1(1713.03,1407.17) 1741.96,1378.25 1741.96,1372.05 1755.01,1359 1777.82,1359 1797.06,1378.25 J3.93@1952.59,1378.25
MCU_GPIO71: J3.95 U1.B14 | length 1742.9
  Top Layer w5.66: U1.B14@633.49,1052.94 649.43,1068.88 649.43,1093.58 695.68,1139.83 712.2,1139.83 712.37,1140 729.24,1140 743.92,1154.68 v1@743.92,1162.82
  L08_SIG3 w4.5: v1(746.42,1160.32) 746.42,1238.97 715,1270.39 715,1325.49 745.72,1356.21 745.72,1428.86 762.33,1445.47 802.63,1445.47 806.85,1441.25 1276.75,1441.25 1292.63,1425.37 1677.48,1425.37 1677.59,1425.49 1712.92,1425.49 1754,1466.57 1780.68,1466.57 1794.98,1452.27 1794.98,1442.31 v1(1839.26,1398.02)
  Bottom Layer w5.66: v1(1839.26,1398.02) 1839.35,1397.93 J3.95@1952.59,1397.93
MCU_GPIO72: J3.96 R42.2 U1.A14 | length 2403
  Top Layer w5.66: U1.A14@633.49,1084.43 635.04,1085.99 635.04,1095.56 639,1099.52 639,1100 690.49,1151.49 707.37,1151.49 758.51,1202.63 797.79,1202.63 837.72,1242.55 837.72,1259.39 852.43,1274.1 v1(852.43,1310.77) ; v1(2090.79,1410.51) 2094.13,1410.51 2100.7,1417.08 2266.02,1417.08 2275,1426.06 R42.2@2275,1430
  L03_SIG1 w4.5: v1(852.43,1310.77) 870,1328.34 870,1465 884.31,1479.31 973.16,1479.31 ccw(c973.16,1491.49) 985.34,1491.49 cw(c1000.15,1491.49) 1000.15,1506.3 cw(c1000.15,1491.49) 1014.96,1491.49 1014.96,1471.13 ccw(c1029.78,1471.13) 1029.78,1456.31 ccw(c1029.78,1471.13) 1044.59,1471.13 1044.59,1491.49 cw(c1059.4,1491.49) 1059.4,1506.3 cw(c1059.4,1491.49) 1074.22,1491.49 1074.22,1471.13 ccw(c1089.03,1471.13) 1089.03,1456.31 ccw(c1089.03,1471.13) 1103.84,1471.13 1103.84,1491.49 cw(c1118.66,1491.49) 1118.66,1506.3 cw(c1118.66,1491.49) 1133.47,1491.49 1133.47,1471.13 ccw(c1148.28,1471.13) 1148.28,1456.31 ccw(c1148.28,1471.13) 1163.09,1471.13 1163.09,1491.49 cw(c1177.91,1491.49) 1177.91,1506.3 cw(c1177.91,1491.49) 1192.72,1491.49 1192.72,1471.13 ccw(c1207.53,1471.13) 1207.53,1456.31 ccw(c1207.53,1471.13) 1222.35,1471.13 1222.35,1491.49 cw(c1237.16,1491.49) 1237.16,1506.3 cw(c1237.16,1491.49) 1251.97,1491.49 1251.97,1483.55 ccw(c1256.21,1483.55) 1256.21,1479.31 1298.69,1479.31 1325.76,1452.24 1544.69,1452.24 1564.89,1472.44 1765.56,1472.44 1779.64,1458.36 1829.25,1458.36 1877.1,1410.51 v1(2090.79,1410.51)
  Bottom Layer w5.66: v1(2090.79,1410.51) 2103.37,1397.93 J3.96@2178.19,1397.93
MCU_GPIO73: J3.94 U1.E13 | length 2118.6
  Top Layer w5.66: U1.E13@601.99,958.45 v1(617.74,974.2)
  L03_SIG1 w4.5: v1(871.55,1290.11) 896.33,1314.9 896.33,1409.42 914.17,1427.26 1720.89,1427.26 1731.81,1416.34 1846.85,1416.34 1865.16,1398.02 1871.73,1398.02 1871.87,1397.89 2077.52,1397.89 2087.4,1388 v1(2240,1388)
  Bottom Layer w5: v1@614.56,971.01 v1(617.74,974.2) 633.73,990.19 655.65,990.19 676.23,1010.77
  Bottom Layer w5.66: 676.23,1010.77 684.57,1019.11 771.81,1019.11 856.69,1103.99 856.69,1128.46 873.17,1144.95 873.17,1189.01 908.38,1224.22 908.38,1276.49 894.76,1290.11 v1(871.55,1290.11) ; J3.94@2178.19,1378.25 J3.94@2179.44,1379.49
  Bottom Layer w6.63: J3.94@2179.44,1379.49 2228.42,1379.49 2236.92,1388 v1(2240,1388)
MCU_GPIO74: J3.92 U1.D13 | length 2125.6
  Top Layer w5.66: U1.D13@601.99,989.94 v1(617.74,1005.69)
  L03_SIG1 w4.5: v1(886.46,1252.89) 887.73,1252.89 898.59,1263.76 ; 898.63,1263.76 922.68,1287.8 922.68,1381.67 940.82,1399.81 972.19,1399.81 980,1392 980,1379.51 986.49,1373.02 1004.51,1373.02 1010,1378.52 1010,1392 1017.81,1399.81 1693.79,1399.81 1721.08,1372.52 1802.51,1372.52 1833.13,1341.91 1921.74,1341.91 1958.65,1378.82 2056.73,1378.82 2077.55,1358 v1(2272,1358)
  Bottom Layer w5: v1(617.74,1005.69) 633.73,1021.69 657.21,1021.69 677.52,1042.01
  Bottom Layer w5.66: 677.52,1042.01 706.01,1042.01 770.92,1106.92 818.65,1106.92 849.95,1138.22 849.95,1217.65 885.2,1252.89 v1(886.46,1252.89) ; J3.92@2178.19,1358.56 2276.44,1358.56 v1@2277,1358
MCU_GPIO75: J3.90 U1.C13 | length 2121.1
  Top Layer w5.66: U1.C13@601.99,1021.44 v1(617.74,1037.19)
  L03_SIG1 w4.5: v1(855.55,1252) 881.55,1226 936,1226 953.16,1243.16 953.16,1327.69 973.67,1348.2 1036.28,1348.2 1039.6,1348.2 ccw(c1039.6,1363.02) 1054.41,1363.02 1054.41,1364.54 cw(c1069.22,1364.54) 1084.03,1364.54 1084.03,1363.02 ccw(c1098.85,1363.02) 1098.85,1348.2 1159.49,1348.2 1339.97,1348.2 1343.47,1348.2 ccw(c1343.47,1363.02) 1358.28,1362.83 1358.3,1364.07 cw(c1373.11,1363.89) 1373.29,1378.7 cw(c1373.11,1363.89) 1387.92,1363.7 1387.91,1363.2 ccw(c1402.73,1363.02) 1402.73,1348.2 1452.09,1348.2 1794.08,1348.2 1822.06,1320.22 1887.78,1320.22 1912.43,1295.57 1939.98,1295.57 1943.3,1295.57 ccw(c1943.3,1310.39) 1958.11,1310.39 1958.11,1322.03 cw(c1972.92,1322.03) 1987.74,1322.03 1987.74,1310.39 ccw(c2002.55,1310.39) 2002.55,1295.57 2051,1295.57 2128.09,1295.57 2137,1304.48 2137,1324.61 2151.18,1338.79 v1(2239.84,1338.79)
  Bottom Layer w5.66: v1(617.74,1037.19) 639.56,1059.01 697.69,1059.01 757.68,1119 780.77,1119 809.3,1147.54 809.3,1205.75 v1(855.55,1252) ; J3.90@2178.19,1338.88 2239.75,1338.88 v1(2239.84,1338.79)
MCU_GPIO76: R89.2 R92.2 U1.B13 | length 435.8
  Top Layer w5.66: U1.B13@601.99,1052.94 617.74,1068.68 617.74,1094.74 627.34,1104.35 627.34,1104.83 742.97,1220.46 v1(765.31,1220.46)
  Bottom Layer w5.66: R89.2@628.5,1162.79 677.49,1162.79 687.62,1152.65 691.56,1152.65 R92.2@700.54,1143.67 ; R92.2@700.54,1139.74 R92.2@700.54,1143.67 ; v1(765.31,1220.46) 762.95,1218.1 762.95,1206.08 R92.2@700.54,1143.67
MCU_GPIO77: J2.26 U1.A13 | length 1635.6
  Top Layer w5.66: U1.A13@601.99,1084.43 603.54,1085.99 603.54,1097.98 641.34,1135.77 673.97,1168.41 673.97,1175.89 712.7,1214.62 v1(712.7,1218.64)
  L03_SIG1 w4.5: v1(-297,1465) -242,1465 -163.67,1543.33 285.25,1543.33 317.58,1575.67 317.58,1603.47 335.13,1621.02 365.78,1621.02 409.2,1577.59 457.07,1577.59 472.07,1562.6 472.07,1498.71 712.7,1258.08 v1(712.7,1218.64)
  Bottom Layer w5.66: v1(-297,1465) -297,1420.25 -274.76,1398.01 J2.26@-213.19,1398.01
MCU_GPIO78: J2.56 U1.D12 | length 1693.1
  Top Layer w5.66: U1.D12@570.49,989.94 v1(586.24,1005.69)
  L03_SIG1 w4.5: v1(-146.07,1108.28) -132.19,1122.16 -132.19,1157.39 -294.36,1319.56 -294.36,1347.29 -277.5,1364.14 -194.2,1364.14 -162.3,1396.04 -102.7,1455.62 200.03,1455.62 271,1384.65 271,1309 351,1229 441,1229 468,1256 503.1,1256 574.63,1184.46 574.63,1082.59 601.97,1055.25 601.97,1021.42 v1(586.24,1005.69)
  Bottom Layer w5.66: J2.56@-213.19,1102.74 -154.95,1102.74 -149.41,1108.28 v1(-146.07,1108.28)
MCU_GPIO79: J3.111 U1.C12 | length 2034.9
  Top Layer w5.66: U1.C12@570.49,1021.44 v1(586.24,1037.19)
  L08_SIG3 w4.5: v1(586.24,1037.19) 554.75,1068.68 554.75,1344.16 863.34,1652.75 1307.79,1652.75 1397.75,1652.75 1415,1670 1415,1725 1435,1745 1528.65,1745 1554.66,1718.99 1554.66,1688.27 1589.74,1653.19 1645.81,1653.19 1654.11,1644.89 1774.49,1644.89 1813.3,1606.08 v1(1849.9,1606.08)
  Bottom Layer w5.66: v1(1849.9,1606.08) 1900.57,1555.41 J3.111@1952.59,1555.41
MCU_GPIO80: J3.102 U1.B12 | length 2491.4
  Top Layer w5.66: U1.B12@570.49,1052.94 586.24,1068.68 586.24,1096.95 591.88,1102.59 591.88,1102.81 662.31,1173.24 v1(662.31,1189.45)
  L08_SIG3 w4.5: v1(662.31,1189.45) 680.62,1207.76 680.62,1311.38 657,1335 657,1387.77 881.68,1612.45 1091.79,1612.45 1128.78,1575.46 1434.49,1575.46 1449.34,1590.31 1752.75,1590.31 1782.53,1560.53 1944.02,1560.53 1976.51,1528.05 2084.24,1528.05 2115,1497.29 2115,1337 2130,1322 2195,1322 2210,1337 2210,1456 2219.55,1465.55 v1(2242.01,1465.55)
  Bottom Layer w5.66: J3.102@2178.19,1456.99 2233.45,1456.99 v1(2242.01,1465.55)
MCU_GPIO81: R15.2 R79.2 U1.A12 | length 2821.9
  Top Layer w5.66: U1.A12@570.49,1084.43 572.05,1085.99 572.05,1099.46 644.48,1171.9 644.48,1210.38 v1(661.67,1227.57) 670.57,1236.47 745.45,1236.47 747.26,1238.29 812.01,1238.29 826.06,1252.33 826.06,1276.28 831.83,1282.05 831.83,1315.39 845.94,1329.5 855.72,1329.5 874.78,1348.56 874.78,1393.79 1050.81,1569.83 1259.1,1569.83 1269.93,1559 v1(1273,1559) ; v1(779.24,338.63) 779.24,272.01 R79.2@779.3,271.95
  L05_SIG2 w4: v1(661.67,1227.57) 540.65,1106.55 540.65,905.36 551.67,894.34 654.54,894.34 664.2,884.68 664.2,810.4 675.28,799.32 686.57,799.32 695.09,790.8 695.09,780.3 705.76,769.62 722.32,769.62 750,741.94 750,693.29 787.39,655.91 787.39,346.78 v1(779.24,338.63)
  Bottom Layer w5.66: v1(1273,1559) 1273,1408 1289.49,1391.51 1289.49,1372.66 1313.95,1348.2 1601.93,1348.2 1618.34,1364.62 1618.34,1398.66 1659.68,1440 R15.2@1663.62,1440
MCU_GPIO82: J3.106 U1.D10 | length 2418.4
  Top Layer w5.66: U1.D10@507.5,989.94 v1(523.25,1005.69)
  L03_SIG1 w4.5: v1(644.74,1663.92) 782.08,1663.92 828.02,1617.98 1808,1617.98 1880.08,1545.89 2072.54,1545.89 2091,1527.44 v1(2091,1496.23)
  L08_SIG3 w4.5: v1(523.25,1005.69) 507.54,1021.41 482.28,1021.41 460.96,1042.72 460.96,1135.77 460.96,1242.66 487.04,1268.73 487.04,1396.06 644.74,1553.76 v1(644.74,1663.92)
  Bottom Layer w5.66: v1@2091.06,1496.3 J3.106@2178.13,1496.3 ; J3.106@2178.19,1496.36 J3.106@2178.25,1496.3
MCU_GPIO83: J3.108 U1.A11 | length 2489.6
  Top Layer w5.66: U1.A11@539,1084.43 540.55,1085.99 540.55,1113.54 619.25,1192.24 619.25,1260.25 v1(628,1269)
  L08_SIG3 w4.5: v1(628,1269) 628,1376.53 879.82,1628.35 1098.5,1628.35 1136.17,1590.67 1425.83,1590.67 1443.78,1608.63 1763.63,1608.63 1799.1,1573.16 1954.89,1573.16 1987.38,1540.67 2116.57,1540.67 2132,1525.24 2132,1360 2138.7,1353.3 2138.7,1352.81 2141.33,1350.17 2188.17,1350.17 2195,1357 2195,1507 2204,1516 v1(2239.37,1516)
  Bottom Layer w5.66: J3.108@2178.19,1516.04 J3.108@2178.19,1516.04 v1(2239.37,1516)
MCU_GPIO84: J3.115 R43.1 U1.D11 | length 2146
  Top Layer w5.66: U1.D11@539,989.94 v1(554.75,1005.69) ; 1861.77,1634.57 1861.77,1633.67 1895.8,1599.64 R43.1@1899.74,1599.64
  Top Layer w6.63: v1(1810.72,1634.57) 1861.77,1634.57
  L08_SIG3 w4.5: 539.43,1067.4 539.43,1374.25 658.18,1493 681.36,1493 853.73,1665.37 1327.34,1665.37 1426.97,1765 1532.55,1765 1627.41,1670.13 1660.87,1670.13 1672.01,1659 1786.28,1659 v1(1810.72,1634.57) ; 539.92,1066.92 539.92,1020.52 v1(554.75,1005.69)
  Bottom Layer w5.66: v1(1810.72,1634.57) 1854.41,1634.57 1894.19,1594.78 J3.115@1952.59,1594.78
MCU_GPIO85: J3.112 U1.B11 | length 2802
  Top Layer w5.66: U1.B11@539,1052.94 554.75,1068.68 554.75,1103.61 632,1180.86 632,1234 v1(647.61,1249.61)
  L08_SIG3 w4.5: v1(647.61,1249.61) 635,1237 635,1180 651,1164 654.01,1160.99 654.01,1135.77 654.01,1100.85 625.15,1072 585,1072 573,1084 573,1168 597,1192 597,1225.18 582.1,1240.09 582.1,1349.76 872.46,1640.12 1109.14,1640.12 1143.26,1606 1415.34,1606 1430.59,1621.25 1768.86,1621.25 1802.34,1587.77 1960.99,1587.77 1988.68,1560.08 2071.08,1560.08 v1(2089.95,1578.95)
  Bottom Layer w5.66: v1(2089.95,1578.95) 2089.95,1643.95 2095.22,1649.22 2107.36,1649.22 2112.66,1643.91 2112.66,1572.66 2087,1547 2087,1530 2096,1521 2112,1521 2117,1526 2117,1545 2127.15,1555.15 2177.92,1555.15 J3.112@2178.19,1555.41
MCU_GPIO86: J2.28 U1.C11 | length 1086
  Top Layer w5.66: U1.C11@539,1021.44 v1(554.75,1037.19)
  L03_SIG1 w4.5: v1(-154.71,1377.71) -120.23,1412.2 41.49,1412.2 60.94,1392.75 100.52,1392.75 115.76,1407.99 219.73,1407.99 254.9,1372.82 254.9,1304.1 347.47,1211.53 505.14,1211.53 554.75,1161.92 v1(554.75,1037.19)
  Bottom Layer w5.66: J2.28@-213.19,1378.33 -212.88,1378.02 -155.01,1378.02 v1(-154.71,1377.71)
MCU_GPIO87: J3.114 U1.C10 | length 2802
  Top Layer w5.66: U1.C10@507.5,1021.44 v1(523.25,1037.19)
  L08_SIG3 w4.5: v1(523.25,1037.19) 507.94,1052.5 507.94,1095.62 510.31,1097.99 510.31,1369.21 667.49,1526.39 667.49,1676.45 689.03,1698 855.64,1698 ccw(c855.64,1712.81) 870.46,1712.81 870.46,1720.17 cw(c885.27,1720.17) 900.08,1720.17 900.08,1704.68 ccw(c914.89,1704.68) 929.71,1704.68 929.71,1720.17 cw(c944.52,1720.17) 959.33,1720.17 959.33,1704.68 ccw(c974.15,1704.68) 988.96,1704.68 988.96,1720.17 cw(c1003.77,1720.17) 1018.59,1720.17 1018.59,1704.68 ccw(c1033.4,1704.68) 1048.21,1704.68 1048.21,1720.17 cw(c1063.02,1720.17) 1077.84,1720.17 1077.84,1712.81 ccw(c1092.65,1712.81) 1092.65,1698 1295.48,1698 1379,1781.52 1570.67,1781.52 1662.97,1689.21 1796.68,1689.21 1871.43,1614.47 1962.64,1614.47 2002.1,1575 2032,1575 2057.57,1600.57 2109.43,1600.57 2156.87,1553.13 v1(2251.18,1553.13)
  Bottom Layer w5.66: J3.114@2178.19,1575.1 2229.25,1575.1 v1@2251.18,1553.17
MCU_GPIO88: J1.2 U1.C3 | length 3430.1
  Top Layer w5.66: v1(271.28,1037.19) U1.C3@287.03,1021.44
  L08_SIG3 w4.5: v1(1225.74,417.59) 1329.41,417.59 1385.73,361.27 1456.12,361.27 1514.13,303.26 1601.46,303.26 1634.68,336.48 1650.37,336.48 1678.26,308.59 v1(1678.26,307.43)
  Bottom Layer w5.66: v1(271.28,1037.19) 248.77,1059.7 206.01,1059.7 135.02,1130.69 135.02,1179.11 127.34,1186.79 127.34,1223.32 153.34,1249.33 204.58,1249.33 250.52,1295.27 250.52,1464.88 190.66,1524.74 190.66,1584.26 238.22,1631.83 651.09,1631.83 679.3,1603.62 924.4,1603.62 1019,1509.02 1019,1171 1045,1145 1045,1022 1060,1007 1060,606.64 1158.74,507.9 1158.74,471.11 1169.19,460.67 1182.67,460.67 v1(1225.74,417.59) ; J1.2@1664.23,253.19 1664.23,293.4 v1(1678.26,307.43)
MCU_GPIO89: J3.118 U1.D4 | length 2809.2
  Top Layer w5.66: v1(302.78,1005.69) U1.D4@318.53,989.94
  L08_SIG3 w4.5: v1(302.78,1005.69) 317.95,1020.86 317.95,1135.77 317.95,1437.95 382.5,1502.5 382.5,1582.5 550.68,1750.68 595.68,1750.68 637.62,1792.62 995.38,1792.62 1039.96,1837.2 1598.4,1837.2 1693.62,1741.97 1809.03,1741.97 1864.57,1686.43 2155.88,1686.43 2198.08,1644.24 2244.76,1644.24 v1(2270,1619)
  Bottom Layer w5.66: J3.118@2178.19,1614.47 2240.27,1614.47 2244.81,1619 v1(2270,1619)
MCU_GPIO90: J3.120 U1.D3 | length 2804.6
  Top Layer w5.66: v1(271.28,1005.69) U1.D3@287.03,989.94
  L08_SIG3 w4.5: v1(271.28,1005.69) 288.53,1022.94 288.53,1473.53 334.42,1519.42 334.42,1545.57 359.44,1570.59 359.44,1601.2 598.27,1840.04 1002.73,1840.04 1017.69,1855 1605.21,1855 1705.62,1754.6 1819.4,1754.6 1874.94,1699.06 2182.94,1699.06 v1(2216,1666)
  Bottom Layer w5.66: J3.120@2178.19,1634.15 2235.14,1634.15 2238.46,1637.47 2238.46,1662.12 2234.58,1666 v1(2216,1666)
MCU_GPIO91: J2.30 U1.D2 U2.35 | length 2563.4
  Top Layer w5.66: v1(239.79,1005.69) U1.D2@255.53,989.94 ; U2.35@1487.47,1433.38 1487.47,1482.31 v1(1507.15,1502)
  L03_SIG1 w4.5: v1(-147.87,1349.98) -169.85,1328 -169.85,1271.48 -140.17,1241.8 -83.58,1241.8 105.72,1052.5 216.94,1052.5 224.47,1044.97 224.47,1021.01 v1(239.79,1005.69)
  L08_SIG3 w4.5: v1@1506.43,1501.28 v1(1507.15,1502)
  L05_SIG2 w4: v1(239.79,1005.69) 225.69,1019.79 225.69,1148.21 276.48,1199.01 276.48,1387.48 381.01,1492.01 525.01,1492.01 592,1559 959.69,1559 977.79,1577.1 1213.72,1577.1 1317.92,1472.9 1373.4,1472.9 1393.4,1492.9 1498.05,1492.9 v1(1507.15,1502)
  Bottom Layer w5.66: J2.30@-213.19,1358.64 -213.02,1358.47 -159.7,1358.47 -151.21,1349.98 v1(-147.87,1349.98)
MCU_GPIO92: J2.32 U1.E2 U2.34 | length 2529.5
  Top Layer w5.66: v1(239.79,974.2) U1.E2@255.53,958.45 ; U2.34@1507.15,1433.38 v1(1507.15,1475.73) v1@1507.15,1476.73
  L03_SIG1 w4.5: v1(-274.84,1339.05) -162.23,1226.44 -89.86,1226.44 131.71,1004.87 185.65,1004.87 200.54,989.98 224,989.98 v1(239.79,974.2)
  L05_SIG2 w4: v1(239.79,974.2) 257.22,991.63 257.22,999.81 257.18,999.85 257.18,1011.53 ; v1(1507.15,1475.73) 1486.69,1455.26 1313.74,1455.26 1229.43,1539.56 593.57,1539.56 511,1457 395.73,1457 286.68,1347.95 286.68,1194.78 257.18,1165.28 257.18,1019.79 257.22,1019.75 257.22,1011.57 ; 257.18,1011.53 257.22,1011.57
  Bottom Layer w5.66: v1(-274.84,1339.05) -274.75,1338.96 J2.32@-213.19,1338.96
MCU_GPIO93: J2.34 U1.E3 U2.33 | length 2614
  Top Layer w5.66: v1(271.28,974.2) U1.E3@287.03,958.45 ; U2.33@1526.84,1433.38 1526.84,1482.31 v1(1546.52,1502)
  L03_SIG1 w4.5: v1(-151.54,1319.18) -151.54,1285.05 -123.87,1257.39 -78.03,1257.39 94.49,1084.87 248.94,1084.87 286.99,1046.82 286.99,989.91 v1(271.28,974.2)
  L05_SIG2 w4: v1(271.28,974.2) 271.28,977.07 287.01,992.79 287.01,1180.69 296.88,1190.56 296.88,1343.73 399.95,1446.8 519.8,1446.8 578.37,1505.36 676.39,1505.36 677.82,1503.93 689.42,1503.93 691.25,1503.93 692.68,1505.36 719.85,1505.36 729.48,1515 1236,1515 1310.77,1440.23 1536.23,1440.23 1563.62,1467.62 1563.62,1484.9 v1(1546.52,1502)
  Bottom Layer w5.66: J2.34@-213.19,1319.27 -151.63,1319.27 v1(-151.54,1319.18)
MCU_GPIO94: J2.36 U1.E4 | length 737.1
  Top Layer w5.66: v1(302.78,974.2) U1.E4@318.53,958.45
  L03_SIG1 w4.5: v1(-126.82,1299.21) -104.31,1276.7 -73.75,1276.7 82.73,1120.22 159.9,1120.22 253.26,1120.22 318.51,1054.97 318.51,989.93 v1(302.78,974.2)
  Bottom Layer w5.66: J2.36@-207.45,1300.28 -206.38,1299.21 v1(-126.82,1299.21)
MCU_GPIO95: J1.70 U1.E5 | length 4444.1
  Top Layer w5.66: v1(334.27,974.2) U1.E5@350.02,958.45
  L08_SIG3 w4.5: v1(797.7,310.32) 797.7,290.6 932.99,155.31 1321.34,155.31 1321.66,155 1336,155 1355,136 1434,136 1450.39,152.39 1450.39,165.61 1434.6,181.4 1416.29,181.4 1416.16,181.28 1406.28,181.28 v1(1405,180)
  L05_SIG2 w4: v1(334.27,974.2) 351.67,991.59 351.67,1354.09 410.16,1412.59 786.94,1412.59 788.4,1411.12 1164.07,1411.12 1195.1,1380.08 1195.1,1242.1 1050,1097 1050,1021 1062,1009 1096,1009 1104,1017 1104,1035 1224,1155 1462,1155 1512,1105 1512,1073 1532,1053 1595,1053 1595.1,1053.1 1607.9,1053.1 1616,1045 1616,1013 1522,919 1522,554.44 1425.56,458 1386.14,458 1361,432.86 1361,381 1385,357 1475,357 1504,328 1504,248 1439.29,183.29 v1@1405.29,183.29
  Bottom Layer w5.66: J1.70@798.03,254.38 v1@798.03,310.32
MCU_GPIO96: J2.46 U1.F3 | length 613.8
  Top Layer w5.66: v1(271.28,942.7) U1.F3@287.03,926.95
  L03_SIG1 w4.5: v1(-148.3,1200.53) -88.78,1200.53 153.75,958 226,958 255.98,958 v1(271.28,942.7)
  Bottom Layer w5.66: J2.46@-213.19,1201.16 -212.56,1200.53 v1(-148.3,1200.53)
MCU_GPIO97: J1.46 U1.F4 | length 2908.8
  Top Layer w5.66: v1(302.78,942.7) U1.F4@318.53,926.95
  L08_SIG3 w4.5: v1(1203,663) 1252.45,613.55 1252.45,499.55 1283,469 1283,452 1275.5,444.5 1220.53,444.5 1188.59,412.56 1188.59,371.91 1228.83,331.67 v1(1230.38,331.67)
  L05_SIG2 w4: v1(302.78,942.7) 303.82,943.74 303.82,954.82 318.59,969.59 318.59,1336.59 404.77,1422.77 405.92,1422.77 ; 405.94,1422.79 535.72,1422.79 558.25,1445.32 900.5,1445.32 900.92,1444.9 1195.19,1444.9 1239.66,1400.42 1239.66,1235 1229.15,1224.49 1221.71,1224.49 1077,1079.78 v1(1077,1030)
  Bottom Layer w5.66: v1(1077,1030) 1076.51,1029.51 1076.51,653.78 1100.29,630 1170,630 v1(1203,663) ; v1(1230.38,331.67) 1231.16,330.89 J1.46@1231.16,253.19
MCU_GPIO98: J1.44 U1.F5 | length 2448.9
  Top Layer w5.66: v1(334.27,942.7) U1.F5@350.02,926.95
  L08_SIG3 w4.5: v1(1163.53,662.47) 1238.75,587.25 1238.75,483.13 1169,413.39 1169,352 1207.65,313.35 1249.45,313.35 v1(1250.94,314.84)
  L05_SIG2 w4: v1(334.27,942.7) 348.37,928.6 403.11,928.6 412.88,938.37 412.88,1126.1 422.55,1135.77 428.76,1141.98 428.76,1258.02 514.34,1343.59 720.44,1343.59 746.42,1317.61 818.39,1317.61 861,1275 946,1275 1024.05,1196.95 1024.05,1023.54 1052.34,995.25 1111.92,995.25 1127.78,1011.11 v1(1127.78,1030.78)
  Bottom Layer w5.66: v1(1127.78,1030.78) 1094.64,997.64 1088.66,991.66 1088.66,777.19 1088.17,776.7 1088.17,658.61 1099.1,647.69 1099.41,647.69 1148.75,647.69 v1(1163.53,662.47) ; J1.44@1250.85,253.19 1250.85,314.75 v1(1250.94,314.84)
MCU_GPIO99: R4.1 R71.1 U1.G5 | length 2074.2
  Top Layer w5.66: v1(334.27,911.2) U1.G5@350.02,895.46
  L05_SIG2 w4: v1(334.27,911.2) 318.67,926.8 318.67,949.16 327.99,958.48 370,958.48 381.55,970.04 381.55,1200.92 362.34,1220.13 362.34,1350.34 399.25,1387.25 702.16,1387.25 716.41,1373 v1(1178,1373)
  Bottom Layer w5.66: v1@1180.48,1373 1180.48,1491.7 1265.61,1576.83 1294.17,1576.83 1309.27,1561.73 1309.27,1538.1 1344.56,1502.81 1360.16,1502.81 1385.19,1527.83 1416.4,1527.83 1442.47,1501.76 1467.96,1501.76 1488.78,1480.94 1488.78,1459.97 1511.98,1436.77 R71.1@1515.92,1436.77 1517.86,1436.77 1526.84,1445.75 1526.84,1511.93 1540.91,1526 1540.91,1541.72 R4.1@1541,1541.81
MCU_GPIO100: J1.12 U1.B4 | length 3008
  Top Layer w5.66: U1.B4@318.53,1052.94 303.81,1067.66 303.81,1130.21 282.2,1151.81 282.2,1536.42 v1(343.15,1597.36)
  L03_SIG1 w4.5: v1(343.15,1597.36) 355.21,1597.36 390.88,1561.69 390.88,1520.58 365.6,1495.3 365.6,1459.74 378.38,1446.96 477.97,1446.96 680.62,1244.31 680.62,1224.87 664.88,1209.12 660.33,1209.12 635.42,1184.21 635.42,1108.42 696.04,1047.79 696.04,858.69 706.63,848.11 795.1,848.11 847.41,795.8 847.41,618.59 865,601 901,601 913,589 913,564.65 952,525.65 952,465.86 1015.58,402.28 1282.72,402.28 1336.19,348.81 1462.02,348.81 1522.81,288.02 v1(1522.81,191.83)
  Bottom Layer w5.66: v1(1522.81,191.83) 1557.57,191.83 1565.81,200.07 J1.12@1565.81,253.19
MCU_GPIO101: J2.48 U1.B5 | length 1690.5
  Top Layer w5.66: U1.B5@350.02,1052.94 334.27,1068.68 334.27,1149.44 306.26,1177.46 306.26,1491.17 v1(368.25,1553.17)
  L03_SIG1 w4.5: v1(-318.87,1174) -318.87,1178.45 -370.82,1230.39 -370.82,1378.86 -309.11,1440.57 -239.78,1440.57 -149.64,1530.7 345.79,1530.7 v1(368.25,1553.17)
  Bottom Layer w5.66: v1(-318.87,1174) -316.83,1174 -309.35,1181.48 J2.48@-213.19,1181.48
MCU_GPIO103: J1.59 U1.D16 | length 1770
  Top Layer w5.66: U1.D16@696.48,989.94 790.23,989.94 v1(800.9,979.28)
  L03_SIG1 w4.5: v1(800.9,979.28) 800.9,893.02 880.92,813 971.7,813 981.66,803.04 981.66,649.76 1083.79,547.63 1201.21,547.63 v1(1207.08,541.76)
  L05_SIG2 w4: v1(1100.48,-65.83) 1100.48,59.74 1114.9,74.17 1264.63,74.17 1277.26,86.8 1277.26,124.7 1271.14,130.82 1271.14,169.43 1171.34,269.24 1171.34,322.66 1159.47,334.53 1159.47,488.65 1207.08,536.27 v1(1207.08,541.76)
  Bottom Layer w5.66: J1.59@1093.37,27.59 1093.37,-42.38 1100.48,-49.5 v1(1100.48,-65.83)
MCU_GPIO105: J1.55 U1.J14 | length 1747.8
  Top Layer w5.66: U1.J14@633.49,832.46 v1(649.23,816.72) ; v1(1012.81,268.06) 1026,254.87 1026,137.1 1055.42,107.68 1081.63,107.68 1117.7,71.6 v1(1117.7,-33.7)
  L03_SIG1 w4.5: v1(649.23,816.72) 665.08,800.87 665.08,747.45 674.31,738.22 730.56,738.22 730.84,737.94 747.11,721.68 770.73,721.68 806.93,685.49 806.93,554.3 871.22,490 901,490 912,479 912,451 994,369 994,297 956,259 956,198.18 966.18,188 1163.62,188 1176.52,200.89 1176.52,211.13 1163.08,224.57 1018.43,224.57 1012.81,230.19 v1(1012.81,268.06)
  Bottom Layer w5.66: v1(1117.7,-33.7) 1118.62,-32.78 1129.51,-32.78 1132.74,-29.56 J1.55@1132.74,27.59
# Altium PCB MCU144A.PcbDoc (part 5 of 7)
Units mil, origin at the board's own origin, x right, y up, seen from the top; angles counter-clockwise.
Board outline 2755.9 x 2276.49 mil, 10 copper layers (Top Layer, L02_GND1, L03_SIG1, L04_GND2, L05_SIG2, L06_PWR, L07_GND3, L08_SIG3, L09_GND4, Bottom Layer), stack 60.4 mil thick; 253 components, 312 nets, 1289 pads, 832 vias.

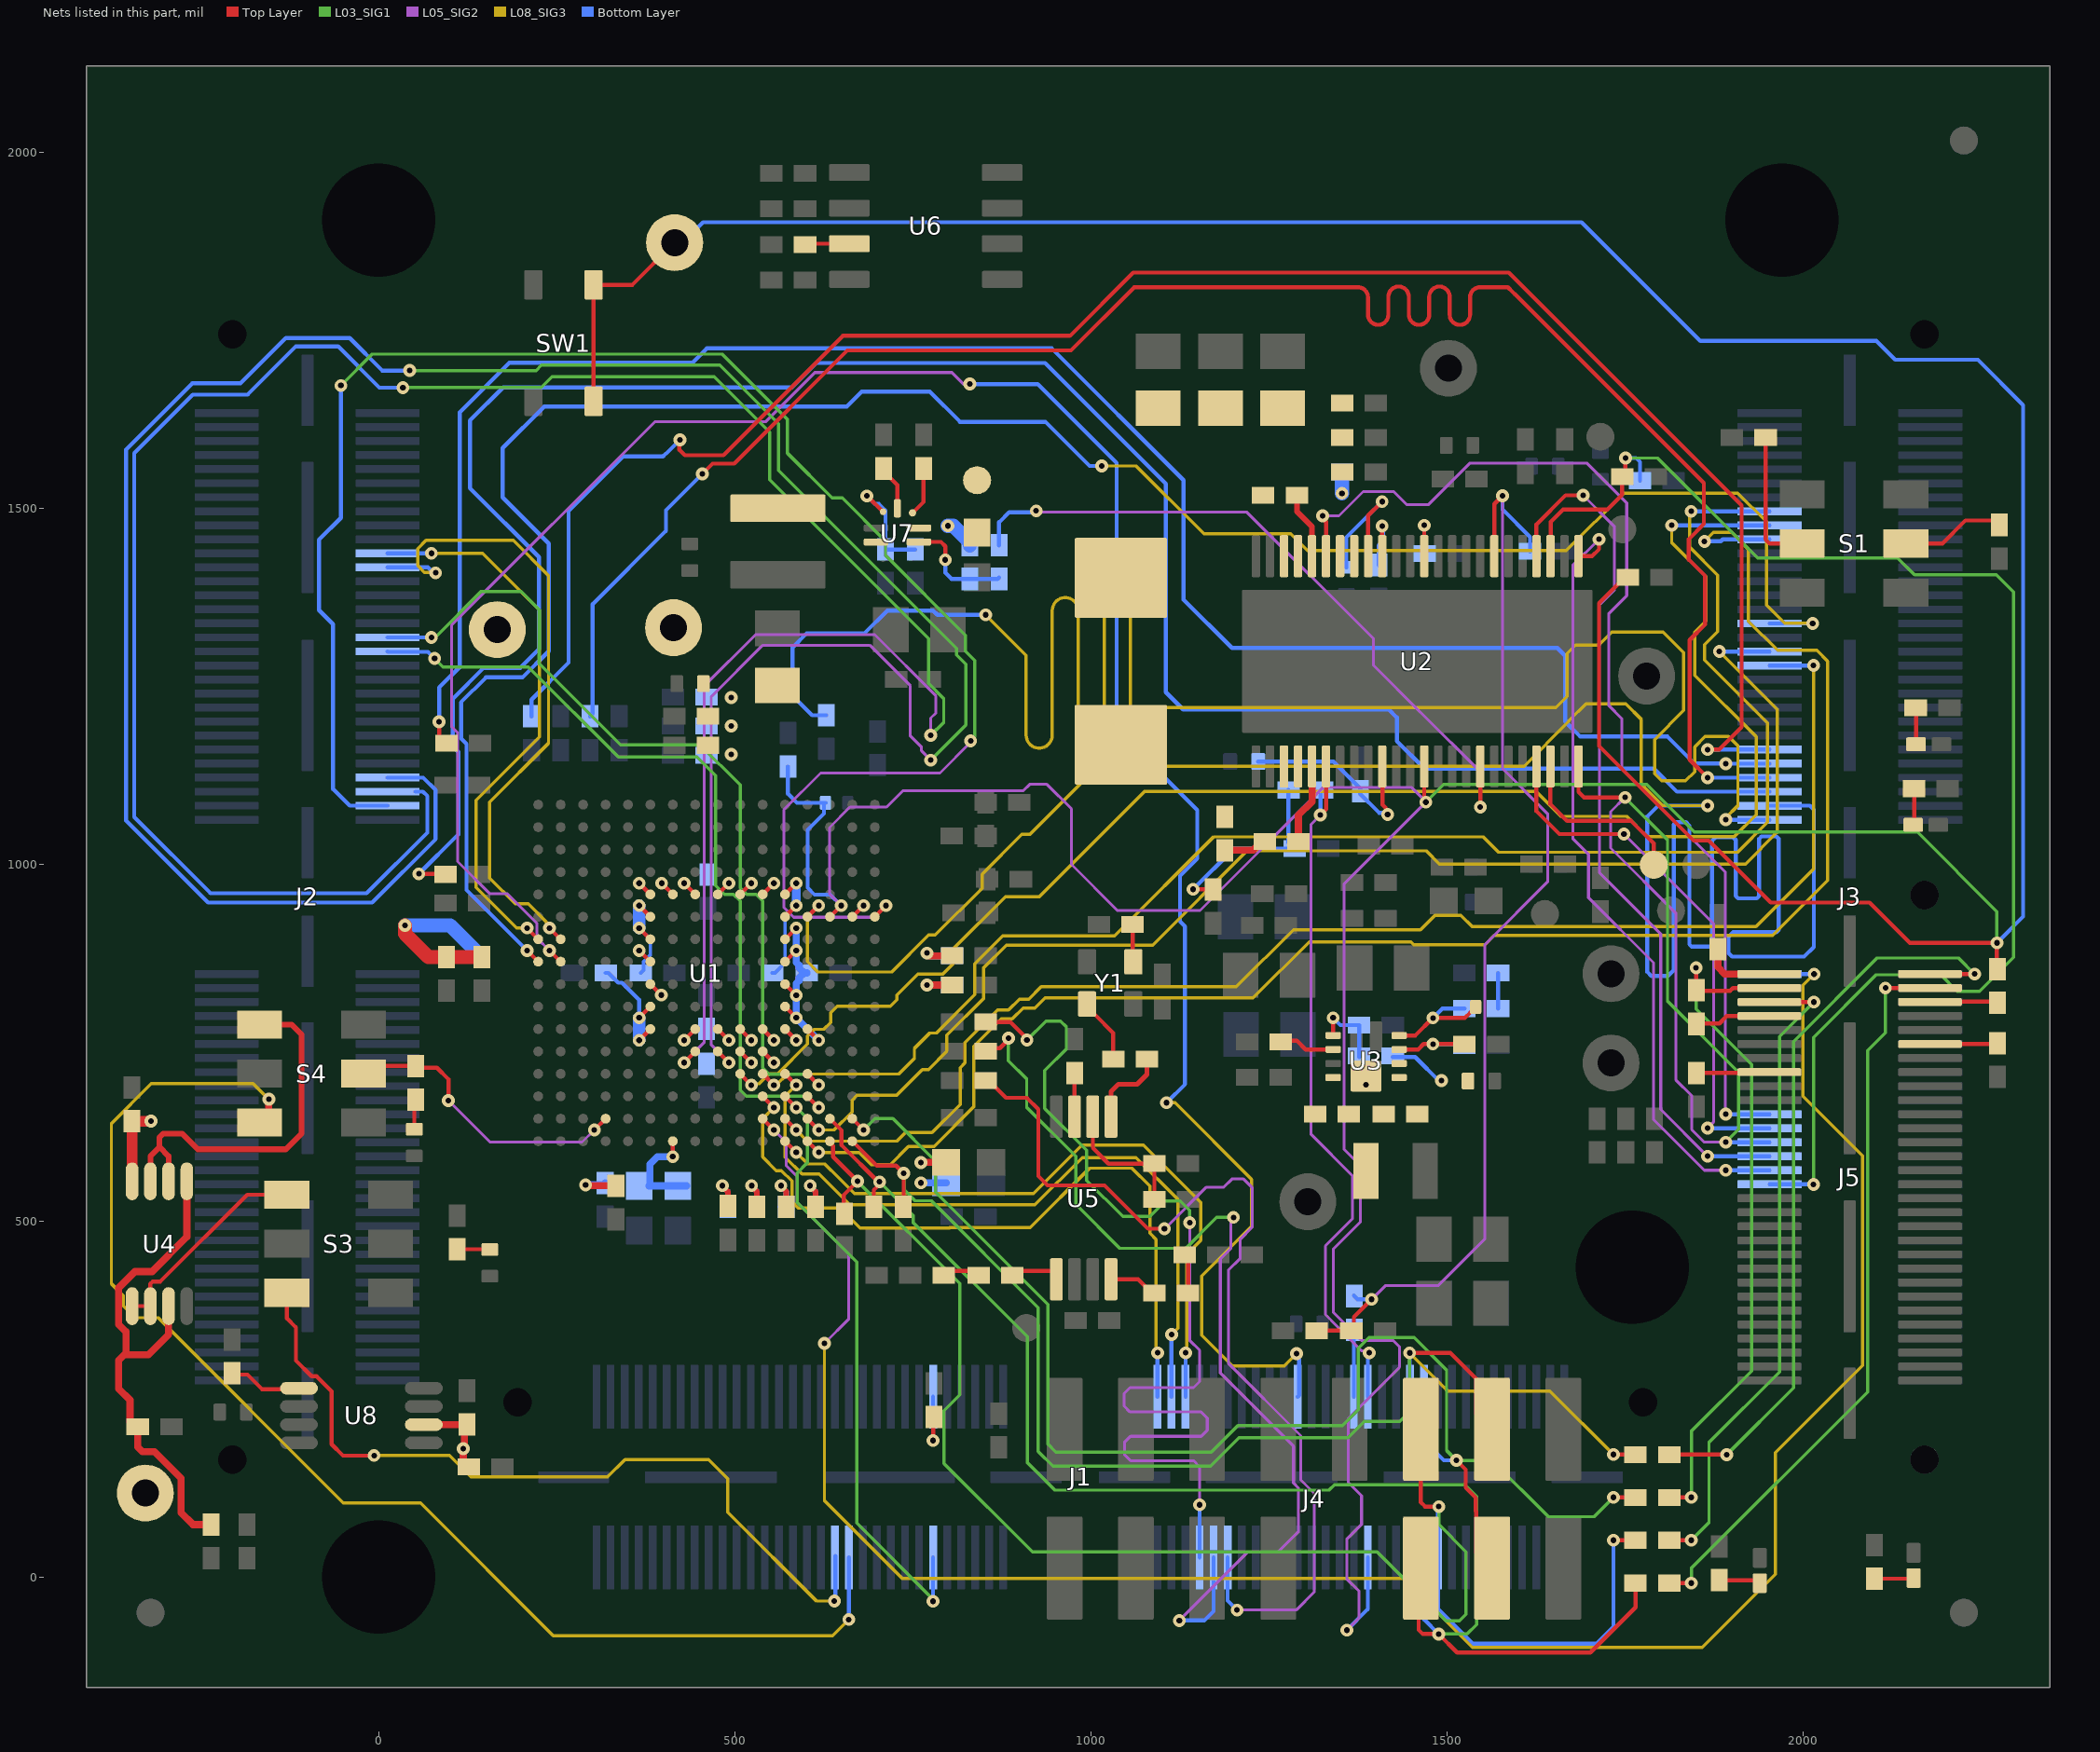
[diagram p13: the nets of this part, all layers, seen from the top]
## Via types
v1: diameter 18, hole 8, Top Layer to Bottom Layer, tented both sides, 776 vias
v2: diameter 19.68, hole 7.87, Top Layer to Bottom Layer, tented top, 54 vias
v3: diameter 18/18/18/18/18/18/18/18/18/18 (per signal layer), hole 8, Top Layer to Bottom Layer, tented both sides, 2 vias

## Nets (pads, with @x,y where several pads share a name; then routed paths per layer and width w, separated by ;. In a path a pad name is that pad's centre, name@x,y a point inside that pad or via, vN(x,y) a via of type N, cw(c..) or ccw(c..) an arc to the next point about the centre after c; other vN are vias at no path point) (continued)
MCU_GPIO127: J3.63 U1.F13 | length 3454.5
  Top Layer w5.66: U1.F13@601.99,926.95 v1(617.74,942.7)
  L08_SIG3 w4.5: v1(617.74,942.7) 601.74,926.7 601.74,864.28 616.49,849.53 720.29,849.53 772.07,901.3 781.2,901.3 847.03,967.14 847.03,986.91 903.12,1043 914.34,1043 1009.85,1138.51 1607.87,1138.51 1671.15,1201.79 1671.15,1202.46 1694.77,1226.09 1750.59,1226.09 1772.6,1204.08 1772.6,1113.05 1802.55,1083.1 v1@1862.32,1083.1
  Bottom Layer w5.66: v1(1865.4,1083.1) 1796.1,1083.1 1781,1068 1781,849.54 1786.54,844 1810,844 1818,852 1818,1056.68 1821.32,1060 1835,1060 1840,1055 1840,888.32 1843.32,885 1868.58,885 1871.9,888.32 1871.9,1033.85 1877.05,1039 1901,1039 1905,1035 1905,956.32 1908.32,953 1934.68,953 1938,956.32 1938,1036.68 1941.32,1040 1961.94,1040 1965.25,1036.68 1965.25,908.73 1961.94,905.41 1901.41,905.41 1895,899 1895,876 1900,871 2000.96,871 2014.61,884.65 2014.61,1077.39 2009.03,1082.97 J3.63@1952.59,1082.97
MCU_GPIO221: J2.57 U1.F16 | length 2546.4
  Top Layer w5.66: U1.F16@696.48,926.95 v1(712.23,942.7)
  L03_SIG1 w4.5: v1(-53,1673) -9,1717 482.24,1717 574.06,1625.18 574.06,1577.64 636.7,1515 651.06,1515 711.5,1454.57 711.5,1434.7 823.73,1322.47 823.73,1300.12 836.85,1287 836.85,1179.85 v1(831,1174)
  L05_SIG2 w4: v1(712.23,942.7) 695.9,926.37 582.63,926.37 568.85,940.16 568.85,1077.4 620.44,1129 788,1129 831,1172 v1(831,1174)
  Bottom Layer w5.66: v1(-53,1673) -53,1487.17 -83.67,1456.5 -83.67,1357.59 -64,1337.92 -64,1106.51 -40.54,1083.05 J2.57@12.41,1083.05
MCU_GPIO222: J1.19 J4.5 R39.1 R63.1 U1.T14 | length 2290.4
  Top Layer w5.66: U1.T14@633.49,611.99 633.49,609.79 637.9,605.38 637.9,590.08 667.32,560.65 v1(672.25,555.72) 652.74,536.2 652.74,511.3 R39.1@654.16,509.88 ; J4.5@1463,207.44 1463,104.93 1468.97,98.96 v1(1488.24,98.96) ; v1(1733.37,51.69) R63.1@1764.41,51.69
  L03_SIG1 w4.5: v1(672.25,555.72) 816,411.98 816,255.65 793.68,233.32 793.68,159.32 917.74,35.26 1401.74,35.26 1498.51,-61.51 1517.23,-61.51 1526.44,-52.31 1526.44,35.48 1488.24,73.68 v1(1488.24,98.96)
  Bottom Layer w5.66: v1(1488.24,98.96) 1487.07,97.79 J1.19@1487.07,27.59 1487.07,-44.74 1536.01,-93.68 1709.19,-93.68 1733.37,-69.5 v1(1733.37,51.69)
MCU_GPIO223: J1.21 J4.6 R40.1 R62.1 U1.R14 | length 2114.7
  Top Layer w5.66: U1.R14@633.49,643.49 649.87,627.1 649.87,606.28 701.26,554.89 v1(703.22,554.89) 703.22,551.55 695.16,543.49 R40.1@695.16,519.88 ; J4.6@1463,12.56 1460,9.56 1460,-74.25 1465.75,-80 v1(1488,-80) 1513.95,-105.95 1701.02,-105.95 1764.41,-42.56 R62.1@1764.41,-8.46
  L03_SIG1 w4.5: v1(703.22,554.89) 750.59,507.53 750.59,497.5 910.67,337.42 910.67,196.54 910.99,196.22 910.99,160.21 949.15,122.05 1334.25,122.05 1341.83,129.63 1524.86,129.63 1541.47,113.02 1541.47,-66.53 1528,-80 v1(1488,-80)
  Bottom Layer w5.66: J1.21@1467.38,27.59 1467.38,-59.38 v1(1488,-80)
MCU_GPIO232: J1.40 U1.H2 | length 3284.8
  Top Layer w5.66: v1(239.79,879.71) U1.H2@255.53,863.96
  L08_SIG3 w4.5: v1(1106,666) 1117.87,666 1225.47,558.41 1225.47,492.47 1155.58,422.58 1155.58,339.42 1198.47,296.53 1271.34,296.53 v1(1288.46,313.64)
  L05_SIG2 w4: v1(239.79,879.71) 222.39,897.1 222.39,917.61 180.3,959.7 155.9,959.7 111,1004.6 111,1185.51 102.25,1194.25 102.25,1336.53 387.73,1622 543,1622 612.2,1691.2 804.8,1691.2 821,1675 v1(830,1675)
  Bottom Layer w5.66: v1(830,1675) 925.22,1675 1035.91,1564.3 1035.91,1190.09 1149.14,1076.86 1149.14,1008.69 1125,984.55 1125,920.4 1132,913.4 1132,692 v1(1106,666) ; v1(1288.46,313.64) 1288.68,313.64 1292,310.32 1292,254.97 J1.40@1290.22,253.19
MCU_GPIO233: J3.89 U1.H1 | length 3076.5
  Top Layer w5.66: v1(208.29,879.71) U1.H1@224.04,863.96
  L08_SIG3 w4.5: v1(1015,1560) 1063.07,1560 1158.5,1464.57 1280.43,1464.57 1304,1441 1667,1441 1748,1522 1908,1522 1948.32,1481.68 1948.32,1364.68 1974,1339 v1(2013,1339)
  Bottom Layer w5.66: v1(208.29,879.71) 123.36,964.64 123.36,1169.81 115.67,1177.5 115.67,1228.15 150.66,1263.14 201.9,1263.14 238.8,1300.04 238.8,1451.03 174.05,1515.78 174.05,1585.11 232.44,1643.49 657.31,1643.49 678.14,1664.33 773.67,1664.33 816,1622 936,1622 998,1560 v1(1015,1560) ; J3.89@1952.59,1338.88 J3.89@1952.59,1338.88 2012.94,1338.94 v1(2013,1339)
MCU_GPIO234: J2.23 U1.G2 | length 1049.8
  Top Layer w5.66: v1(239.79,911.2) U1.G2@255.53,895.46
  L08_SIG3 w4.5: v1(80,1410) 79.25,1410.75 64.25,1410.75 55,1420 55,1444.13 66.48,1455.6 188.96,1455.6 238.48,1406.08 ; 138.58,1455.69 188.87,1455.69 238.48,1406.08 ; v1(239.79,911.2) 239.79,914.28 235.67,918.4 235.67,919.53 209.84,945.35 191.99,945.35 155.96,981.38 155.96,1088.19 238.48,1170.71 238.48,1406.08
  Bottom Layer w5.66: J2.23@12.41,1417.7 68.96,1417.7 76.66,1410 v1(80,1410)
MCU_GPIO235: J2.21 U1.G1 | length 790.2
  Top Layer w5.66: v1(208.29,911.2) U1.G1@224.04,895.46
  L08_SIG3 w4.5: v1(74.06,1437.29) 74.15,1437.38 146.16,1437.38 225.86,1357.69 225.86,1179.53 136.74,1090.41 136.74,968.23 193.77,911.2 v1(208.29,911.2)
  Bottom Layer w5.66: J2.21@12.41,1437.38 v1@73.97,1437.38
MCU_GPIO236: J2.55 U1.M8 | length 3635.2
  Top Layer w5.66: v1(428.76,722.23) U1.M8@444.51,737.98
  L03_SIG1 w4.5: v1(34,1670) 228.22,1670 243.28,1685.06 471.19,1685.06 548.81,1607.44 548.81,1540.6 772,1317.41 772,1254.71 793.25,1233.46 793.25,1200.07 v1(775,1181.82)
  L05_SIG2 w4: v1(428.76,722.23) 456.8,750.27 456.8,1250.87 529.12,1323.19 696.32,1323.19 782.41,1237.1 782.41,1213.38 775,1205.96 v1(775,1181.82)
  Bottom Layer w5.66: v1(34,1670) 1,1670 -57,1728 -116,1728 -184,1660 -261,1660 -343,1578 -343,1067 -236,960 -16.9,960 68.34,1045.24 68.34,1096.66 62.26,1102.74 J2.55@51.91,1102.74
MCU_GPIO237: J2.53 U1.M9 | length 3818
  Top Layer w5.66: U1.M9@476.01,737.98 v1(491.75,722.23)
  L03_SIG1 w4.5: v1(43.41,1694) 221,1694 228.63,1701.63 479.01,1701.63 561.43,1619.2 561.43,1553.57 811.11,1303.89 811.11,1294.89 824.23,1281.77 824.23,1196.23 v1(775,1147)
  L05_SIG2 w4: v1(491.75,722.23) 467,746.98 467,1236.15 539.24,1308.38 689.52,1308.38 746.42,1251.48 746.42,1180.9 762,1165.32 762,1160 v1(775,1147)
  Bottom Layer w5.66: J2.53@12.41,1122.42 62.58,1122.42 80,1105 80,1036.12 -9.12,947 -239.49,947 -354.66,1062.17 -354.66,1582.83 -261.49,1676 -194,1676 -130.34,1739.66 -40.66,1739.66 5,1694 v1(43.41,1694)
MCU_GPIO238: J1.58 U1.N12 | length 1041.7
  Top Layer w5.66: U1.N12@570.49,706.48 v1(586.24,690.73)
  L08_SIG3 w4.5: v1(586.24,690.73) 570.53,675.02 570.53,589.73 594.37,565.89 618.33,565.89 623.57,560.65 661.67,522.55 921.3,522.55 987.74,588.99 1063.27,588.99 1122,530.26 1122,349.2 v1(1113.18,340.38)
  Bottom Layer w5.66: J1.58@1113.05,253.19 1113.05,340.25 v1(1113.18,340.38)
MCU_GPIO239: J1.71 U1.P12 | length 868.8
  Top Layer w5.66: U1.P12@570.49,674.98 v1(586.24,659.24)
  L03_SIG1 w4.5: v1(586.24,659.24) 601.96,643.52 601.96,581.9 587.42,567.37 587.42,526.02 671.09,442.35 671.09,75.91 778.2,-31.2 v1(778.2,-34.06)
  Bottom Layer w5.66: v1(778.2,-34.06) 778.29,-33.97 J1.71@778.29,27.59
MCU_GPIO240: J3.103 U1.N10 | length 2279.1
  Top Layer w5.66: U1.N10@507.5,706.48 v1(523.25,690.73)
  L08_SIG3 w4.5: v1(523.25,690.73) 525.04,692.52 533.9,692.52 548.29,706.91 560.5,706.91 601.83,748.25 601.83,759.47 611.45,769.09 624.98,769.09 634.69,778.8 634.69,792.33 643.76,801.4 718.57,801.4 727.54,810.37 727.54,816.9 757.05,846.42 792.01,846.42 807,861.4 807,882.46 879.95,955.41 927.44,955.41 1075.34,1103.31 1624.65,1103.31 1659.96,1068 1752,1068 1780.4,1039.6 1902.8,1039.6 1933.76,1070.56 1933.76,1179.91 1847.64,1266.03 1847.64,1327.02 1863.21,1342.59 1863.21,1404.38 1815.19,1452.4 v1(1815.19,1476.67)
  Bottom Layer w5.66: v1(1815.19,1476.67) J3.103@1952.59,1476.67
MCU_GPIO241: J3.105 U1.N11 | length 2233
  Top Layer w5.66: U1.N11@539,706.48 v1(554.75,690.73)
  L08_SIG3 w4.5: v1@556.92,692.91 v1(554.75,690.73) 558.08,690.73 573.61,706.27 730.27,706.27 752.02,728.02 752.02,742.21 773.6,763.79 782.94,763.79 836.86,817.71 836.86,860.77 859.76,883.68 876.13,900.04 1032.86,900.04 1172.08,1039.27 1550.59,1039.27 1572.16,1017.69 1907.67,1017.69 1949.82,1059.84 1949.82,1199.09 1861.33,1287.58 1861.33,1309.02 1879.79,1327.48 1879.79,1406.69 1840.28,1446.19 1840.28,1494.24 v1(1842.4,1496.36)
  Bottom Layer w5.66: v1(1842.4,1496.36) J3.105@1952.59,1496.36
MCU_GPIO242: J1.56 U1.T12 | length 957.1
  Top Layer w5.66: U1.T12@570.49,611.99 v1(586.24,596.24)
  L08_SIG3 w4.5: v1(586.24,596.24) 602.47,580.02 626.3,580.02 645.67,560.65 668.14,538.18 919.08,538.18 987.28,606.39 1073.61,606.39 1153.83,526.17 1153.83,472.69 1134.63,453.48 1134.63,316.64 v1(1132.83,314.84)
  Bottom Layer w5.66: J1.56@1132.74,253.19 1132.74,314.75 v1(1132.83,314.84)
MCU_GPIO243: J3.83 U1.R12 | length 2022.3
  Top Layer w5.66: U1.R12@570.49,643.49 v1(586.24,627.74)
  L08_SIG3 w4.5: v1(586.24,627.74) 602.01,611.97 ; 602.01,612.03 727.36,612.03 739.59,624.26 776.9,624.26 816.27,663.63 816.27,715.27 822.99,722 822.99,750.28 868.96,796.25 884.25,796.25 899.42,811.42 912.42,811.42 930,829 1204,829 1284,909 1462.56,909 1482.78,929.22 1519.36,929.22 1535.11,913.47 1933.59,913.47 2014.24,994.12 v1(2014.24,1279.91)
  Bottom Layer w5.66: J3.83@1952.59,1279.82 v1@2014.15,1279.82
MCU_GPIO244: J3.85 U1.R13 | length 1962.4
  Top Layer w5.66: U1.R13@601.99,643.49 v1(617.74,627.74)
  L08_SIG3 w4.5: v1(617.74,627.74) 639.39,627.74 664.55,652.89 664.55,669.25 671.53,676.23 727.04,676.23 727.24,676.43 763.22,712.42 771.84,712.42 797.74,738.32 797.74,760.74 849.49,812.48 849.49,855.54 881.36,887.42 1086.84,887.42 1219.02,1019.59 1470.46,1019.59 1489.02,1001.04 1918.69,1001.04 1963.59,1045.93 1963.59,1218.07 v1(1882.15,1299.51)
  Bottom Layer w5.66: v1(1882.15,1299.51) J3.85@1952.59,1299.51
MCU_GPIO245: J3.101 U1.T13 | length 2376.6
  Top Layer w5.66: U1.T13@601.99,611.99 v1(617.74,596.24)
  L08_SIG3 w4.5: v1(617.74,596.24) 674.48,596.24 691.62,579.11 718.12,579.11 743.53,604.52 779.72,604.52 835.62,660.41 835.62,745.05 874.19,783.62 889.48,783.62 904.65,798.8 921.33,798.8 935.53,813 1227.6,813 1306.47,891.87 1449.32,891.87 1453.14,888.05 1553.05,888.05 1565.84,900.84 1956.99,900.84 2034.2,978.05 2034.2,1285.85 2019.05,1301 1964,1301 1923,1342 1923,1442.92 1899.02,1466.89 1873.91,1466.89 v1(1861.2,1454.19)
  Bottom Layer w5.66: v1(1861.2,1454.19) 1884.07,1454.19 1886.87,1456.99 J3.101@1952.59,1456.99
MCU_GPIO246: J1.60 U1.P11 | length 1045.4
  Top Layer w5.66: U1.P11@539,674.98 v1(554.75,659.24)
  L08_SIG3 w4.5: v1(554.75,659.24) 538.96,643.45 538.96,589.8 558.27,570.5 565.38,570.5 580.05,555.83 580.05,526.95 589,518 648.36,518 676.08,490.28 801.44,490.28 801.64,490.48 914.43,490.48 998.05,574.1 1057.32,574.1 1082.75,548.67 1082.75,482.8 1091.54,474.01 1091.54,316.75 v1(1093.46,314.84)
  Bottom Layer w5.66: J1.60@1093.37,253.19 1093.37,314.75 v1(1093.46,314.84)
MCU_GPIO247: J3.59 U1.R11 | length 3059.9
  Top Layer w5.66: U1.R11@539,643.49 v1(554.75,627.74)
  L08_SIG3 w4.5: v1(625.8,328.2) 625.8,107.2 735,-2 1439,-2 1535.55,-98.55 1857.86,-98.55 1960.49,4.09 1960.49,174.49 2083,297 2083,591.46 1999.42,675.03 1999.42,830.98 v1(2015.08,846.63)
  L05_SIG2 w4: v1(554.75,627.74) 572.14,610.34 572.14,577.69 587.42,562.41 587.42,526.02 660,453.44 660,362.39 v1(625.8,328.2)
  Bottom Layer w5.66: J3.59@1952.59,846.63 v1(2015.08,846.63)
MCU_GPIO248: J2.35 U1.P13 | length 1138.8
  Top Layer w5.66: U1.P13@601.99,674.98 v1(617.74,659.24)
  L03_SIG1 w4.5: v1(78.53,1289.7) 90.25,1277.98 210.02,1277.98 336.64,1151.36 446.94,1151.36 472.86,1125.44 472.86,970.87 485.25,958.48 498.19,958.48 507.5,949.17 507.5,683.85 516.33,675.02 554.77,675.02 601.96,675.02 602.03,674.95 v1(617.74,659.24)
  Bottom Layer w5.66: J2.35@12.41,1299.59 13.01,1298.99 69.24,1298.99 v1(78.53,1289.7)
MCU_GPIO249: J2.33 U1.N13 | length 1207.1
  Top Layer w5.66: U1.N13@601.99,706.48 v1(617.74,690.73)
  L03_SIG1 w4.5: v1(74.06,1319.18) 79.18,1319.18 143.58,1383.58 199.97,1383.58 225,1358.55 225,1283 339.31,1168.69 450.84,1168.69 507.54,1111.99 507.54,967.69 516.74,958.48 526.97,958.48 527.04,958.41 529.76,958.41 538.96,949.21 538.96,715.29 548.21,706.04 602.43,706.04 v1(617.74,690.73)
  Bottom Layer w5.66: J2.33@12.41,1319.27 12.46,1319.23 74.02,1319.23 v1(74.06,1319.18)
MCU_TCK: J1.22 J4.4 R61.1 U1.R15 | length 2036.5
  Top Layer w5.66: U1.R15@664.98,643.49 v1(680.73,627.74) ; v1(1513.05,163.8) 1525.98,150.86 1525.98,125.51 1540.24,111.25 1540.24,92.42 1540.83,91.83 1540.83,34.73 J4.4@1563,12.56 ; v1(1733.37,111.85) R61.1@1764.41,111.85
  L03_SIG1 w4.5: v1(680.73,627.74) 696.73,643.74 721.79,643.74 722.08,643.45 781.67,583.85 781.67,540.21 939.25,382.64 939.25,186.75 950.82,175.18 1168.76,175.18 1206.13,212.56 1353.07,212.56 1375.37,234.87 1375.37,321.14 1390.42,336.18 1453.69,336.18 1499.18,290.69 1499.18,177.66 v1(1513.05,163.8) 1562.89,163.8 1641.96,84.73 1706.25,84.73 v1(1733.37,111.85)
  Bottom Layer w5.66: J1.22@1467.38,253.19 1467.38,191.66 1495.25,163.8 v1(1513.05,163.8)
MCU_TMS: J1.24 J4.3 R41.1 R60.1 U1.T15 | length 1894.4
  Top Layer w5.66: U1.T15@664.98,611.99 699.2,577.77 726.34,577.77 v1(737.09,567.02) 737.09,528.04 R41.1@728.93,519.88 ; v1(1447.24,314.71) 1504.42,314.71 1540.83,278.3 1540.83,229.61 J4.3@1563,207.44 ; v1(1733.37,172.01) R60.1@1764.41,172.01
  L03_SIG1 w4.5: v1(737.09,567.02) 737.09,544.47 753.23,528.33 775.7,528.33 925.8,378.23 925.8,176.34 946.69,155.45 1167.69,155.45 1207.84,195.61 1360.86,195.61 1383.55,218.29 1433.51,218.29 1447.24,232.03 v1(1447.24,314.71)
  L08_SIG3 w4.5: v1(1447.24,314.71) 1500.64,261.32 1644.06,261.32 v1(1733.37,172.01)
  Bottom Layer w5.66: v1(1447.24,314.71) 1447.47,314.48 1447.47,253.41 J1.24@1447.7,253.19
MCU_XRSn: C97.2 J1.29 R16.1 R46.1 R64.1 SW1.3 SW1.4 TP15.1 U1.F14 U2.13 | length 7988.2
  Top Layer w5.66: SW1.3@301.81,1650.94 SW1.4@301.81,1814.33 356.21,1814.33 TP15.1@415.49,1873.61 ; U1.F14@633.49,926.95 v1(649.23,942.7) ; U2.13@1467.78,1138.1 1467.78,1093.29 1470,1091.07 v1(1470,1088) ; R16.1@1753.45,1403.68 1749.51,1403.68 1713.21,1367.38 1713.21,1166.79 1846,1034 1867.15,1034 1954.16,946.99 2093.01,946.99 2149.53,890.47 v1(2271.66,890.47) 2271.66,854.3 R64.1@2272.29,853.67
  L03_SIG1 w4.5: v1(1470,1088) 1494.92,1112.92 1780.08,1112.92 1847,1046 2160,1046 2271.66,934.34 v1(2271.66,890.47)
  L05_SIG2 w4: v1(649.23,942.7) 633,958.94 633,1052.45 661.55,1081 712.99,1081 736.26,1104.27 905.27,1104.27 914,1113 938.12,1113 972.41,1078.7 972.41,1000.59 1037,936 1152.99,936 1325.39,1108.4 1450.34,1108.4 1470,1088.74 v1(1470,1088) 1355,973 1355,601 1377.88,578.12 1377.88,498.1 1340,460.22 1340,372 1380.11,331.89 1424.54,331.89 1433.14,323.29 1433.14,294.5 1360.86,222.22 1360.86,133.08 1379.8,114.15 1379.8,73.8 1359,53 1359,-2.52 1376.1,-19.62 1376.1,-57.49 v1(1359.05,-74.53)
  Bottom Layer w5: 602.24,1049.08 602.24,967.78 611.81,958.2 633.73,958.2 v1(649.23,942.7)
  Bottom Layer w5.66: TP15.1@415.49,1873.61 426.81,1873.61 455.44,1902.23 1688.68,1902.23 1855.21,1735.71 2102.29,1735.71 2128.9,1709.1 2244.9,1709.1 2308.52,1645.48 2308.52,927.33 v1(2271.66,890.47) ; R46.1@574.63,1138.09 574.63,1099.68 587.27,1087.04 C97.2@627.28,1087.04 625.18,1084.94 625.18,1072.03 602.24,1049.08 ; v1(1359.05,-74.53) 1388.64,-44.95 J1.29@1388.64,27.59
NetC38_1: C38.1 L4.2 U2.45 U2.46
NetC38_2: C38.2 U2.44 | length 94.5
  Top Layer w8: C38.2@1288.94,1519 1288.94,1496.06 1310.3,1474.7 U2.44@1310.3,1433.38
NetC39_1: C39.1 R7.1 | length 60.9
  Top Layer w10: R7.1@1188,1020.38 1227.64,1020.38 1239.9,1032.64 C39.1@1243.84,1032.64
NetC39_2: C39.2 U2.5 | length 113.4
  Top Layer w10: C39.2@1291.08,1032.64 1291.08,1069.43 1310.3,1088.65 U2.5@1310.3,1138.1
NetC40_1: C40.1 U3.10
NetC40_2: C40.2 L5.2 R12.2 U3.11
  other v2: 1386.22,691.5
NetC41_2: C41.2 U2.39 | length 100.9
  Top Layer w5.66: U2.39@1408.73,1433.38 v1(1408.73,1475.73) v1@1408.73,1476.73
  Bottom Layer w5.66: C41.2@1404,1421 1404,1448.51 1409.77,1454.29 1409.77,1474.68 v1(1408.73,1475.73)
NetC42_1: C42.1 U2.40 | length 198.1
  Top Layer w5.66: U2.40@1389.04,1433.38 1389.04,1490.31 v1(1408.73,1510)
  Bottom Layer w5.66: C42.1@1358.5,1417.46 1358.5,1459.77 v1(1408.73,1510)
NetC46_2: C46.2 R67.2 U3.2 | length 80.9
  Bottom Layer w5.66: R67.2@1423.62,730 1455,730 v1@1490,695
  other v1: 1492,697
NetC47_2: C47.2 R13.2 U3.4 | length 175
  Top Layer w5.66: U3.4@1432.48,760.39 1455.39,760.39 v1(1480,785) 1524.69,785 1533.04,793.35 1535.01,793.35 1540.05,798.39 C47.2@1540.05,800.36
  Bottom Layer w5.66: v1(1480,785) 1493.19,798.19 R13.2@1524.25,798.19
NetC51_1: C51.1 R13.1 | length 49.7
  Bottom Layer w5.66: R13.1@1571.5,798.19 C51.1@1571.5,847.93
NetC78_1: C78.1 R53.1 U4.3 U4.5 | length 739.4
  Top Layer w10: U4.3@-294.82,380.4 -294.82,340.18 -323,312 -357,312 ; U4.5@-269.23,555.6 -269.23,477.64 -318.04,428.83 -341.96,428.83 -364.86,405.93 -364.86,354.87 -354.36,344.38 -354.36,314.64 -357,312 ; R53.1@-235,73.62 -260.62,73.62 -277.51,90.51 -277.51,138.66 -314.94,176.09 -331.66,176.09 -338.24,182.67 C78.1@-338.24,211 -342.18,211 -348.99,217.81 -348.99,248.54 -365,264.55 -365,304 -357,312
NetC80_2: C80.2 R56.1 | length 38.8
  Top Layer w5.66: R56.1@109.99,460.35 109.91,460.27 148,460.27 C80.2@148.43,459.84
NetC82_2: C82.2 R58.1 | length 42.5
  Top Layer w5.66: C82.2@50,628.7 50,668.38 R58.1@52,670.38
NetC87_1: C87.1 U8.5 | length 104.1
  Top Layer w5.66: C87.1@-206,286.38 -203.81,284.19 -184.19,284.19 -163.87,263.87 -113.15,263.87 U8.5@-111.81,265.2
NetC96_1: C96.1 R70.2 U1.T7 | length 141.4
  Top Layer w5.66: v1(412.84,590.25) 412.84,611.82 U1.T7@413.01,611.99
  Bottom Layer w10: C96.1@379.51,549.31 R70.2@432.23,549.31 ; C96.1@380.77,549.31 380.77,579.74 391.27,590.25 v1(412.84,590.25)
NetC98_2: C98.2 U7.8 | length 63.9
  Top Layer w5.66: C98.2@708.91,1556.38 708.91,1552.44 728.21,1533.14 U7.8@728.21,1500.51
NetJ1_32: J1.32 R74.1 | length 95.8
  Bottom Layer w5.66: R74.1@1368.76,348.9 1368.76,347.31 1368.96,347.11 J1.32@1368.96,253.19
NetJ1_72: J1.72 R79.1 | length 95
  Top Layer w5.66: v1(778.36,191.64) 778.36,223.76 R79.1@779.3,224.7
  Bottom Layer w5.66: J1.72@778.29,253.19 J1.72@778.29,253.19 778.33,191.68 v1(778.36,191.64)
NetL4_1: L4.1 R7.2 U2.3 U2.4
NetL7_1: L7.1 U7.2
NetLED1_1: LED1.1 R19.1 | length 58.7
  Top Layer w5.66: R19.1@1881.81,-4.5 1934.78,-4.5 LED1.1@1938.84,-8.55
NetLED2_1: LED2.1 R20.1 | length 55.4
  Top Layer w5.66: R20.1@2099.84,-2.34 2153.94,-2.34 LED2.1@2154.84,-1.43
NetLED3_1: LED3.1 R47.1 | length 56.6
  Top Layer w5.66: R47.1@2155.21,1106.99 2155.84,1106.36 LED3.1@2155.84,1050.61
NetLED4_1: LED4.1 R48.1 | length 56.6
  Top Layer w5.66: R48.1@2157.62,1220.57 2158.25,1219.94 LED4.1@2158.25,1164.19
NetR5_1: R5.1 R8.2 U2.10 | length 284.3
  Top Layer w5.66: U2.10@1409.09,1135 1409.09,1084.34 1414.02,1079.41 1414.02,1073.15 v1(1416.38,1070.79)
  Bottom Layer w5.66: R5.1@1234.68,1145 1340.36,1145 1377.92,1107.44 R8.2@1377.92,1103.5 1377.92,1099.56 1404.33,1073.15 1414.02,1073.15 v1(1416.38,1070.79)
NetR6_1: R6.1 R9.2 R66.2 | length 279.8
  Top Layer w5.66: v1(1143.39,965.62) R9.2@1171.09,965.62
  Bottom Layer w5.66: v1(1143.39,965.62) 1200.42,1022.65 R6.1@1285.94,1022.65 1277.2,1031.39 R66.2@1277.2,1105
NetR12_1: R12.1 U3.1
NetR14_1: R14.1 R18.2 U3.3 | length 139.2
  Top Layer w5.66: U3.3@1432.48,740.71 1459.24,740.71 1466.86,748.33 v1(1480,748.33) R14.1@1524.3,748.33
  Bottom Layer w5.66: v1(1480,748.33) R18.2@1524.25,748.33
NetR17_2: R17.2 U3.8 | length 79.4
  Top Layer w5.66: R17.2@1266.26,751.53 1267.73,753 1289,753 1301.29,740.71 U3.8@1339.96,740.71
NetR21_1: R21.1 R22.2 U7.5 | length 156.8
  Top Layer w5.66: U7.5@758.23,1453.27 789.41,1453.27 795.49,1447.19 v1@795.49,1427.33
  Bottom Layer w5.66: v1@795.49,1427.33 795.49,1410.11 804.22,1401.38 R21.1@830,1401.38 869.03,1401.38 R22.2@871,1403.35
  other v1: 795.49,1428.22
NetR28_2: R28.2 U7.7 | length 68.7
  Top Layer w5.66: U7.7@749.37,1494.11 765,1509.74 R28.2@765,1556.38
NetR30_1: R30.1 R33.2 U5.2 | length 189.5
  Top Layer w5.66: U5.2@1002.56,646.36 1002.56,602.44 1024.62,580.38 R30.1@1089.02,580.38 R33.2@1089.02,530.38
NetR34_1: R34.1 U5.3 | length 58.4
  Top Layer w5.66: U5.3@976.97,646.36 R34.1@976.97,704.79
NetR36_1: R36.1 Y1.3 | length 85.6
  Top Layer w5.66: Y1.3@1002.52,800.47 1002.52,791.75 1005.02,789.25 1005.75,789.25 1031.15,763.85 R36.1@1031.15,727.19
NetR36_2: R36.2 U5.1 | length 117
  Top Layer w6.66: U5.1@1028.15,646.36 1028.15,681.59 1038.34,691.78 1064.64,691.78 1078.39,705.54 R36.2@1078.39,727.19
NetR37_2: R37.2 Y1.1 | length 56.4
  Top Layer w5.66: R37.2@1058.39,912.19 1058.39,868.62 Y1.1@1067.48,859.53
NetR38_1: R38.1 U5.8 | length 68.7
  Top Layer w5.66: U5.8@1028.15,418.02 1066.08,418.02 1085.08,399.02 R38.1@1089.02,399.02
NetR42_1: R42.1 S1.2 | length 146.9
  Top Layer w5.66: S1.2@2144,1451.1 2195.19,1451.1 2227.47,1483.38 2268.86,1483.38 R42.1@2275,1477.24
NetR43_2: R43.2 S1.5 | length 196.5
  Top Layer w5.66: R43.2@1946.98,1599.64 1946.98,1456.83 1952.71,1451.1 S1.5@1998.33,1451.1
NetR58_2: R58.2 S4.2 U1.R4 | length 418.2
  Top Layer w5.66: S4.2@-21.33,706.9 -10.61,717.62 R58.2@52,717.62 ; R58.2@52.55,715.11 81.89,715.11 98,699 v1(98,669) ; v1(302.78,627.74) U1.R4@318.53,643.49
  L05_SIG2 w4: v1(98,669) 156.36,610.64 285.68,610.64 v1(302.78,627.74)
NetR67_1: R67.1 R68.2 U3.7 | length 138
  Top Layer w5.66: v1@1338.89,786.18 v1(1339.91,785.16) ; v1(1339.91,785.16) 1339.91,760.44 v1(1339.91,785.16)
  Bottom Layer w5.66: v1@1338.89,786.18 1350.07,775 R68.2@1376.38,775 R67.1@1376.38,730
NetR69_1: R69.1 U6.7 | length 62.1
  Top Layer w5.66: R69.1@598.62,1872 U6.7@660.72,1872
NetR71_2: R71.2 U2.36 | length 71.5
  Top Layer w5.66: U2.36@1467.78,1433.38 v1(1467.78,1476.73)
  Bottom Layer w5.66: 1467.78,1448.58 1467.78,1462.91 v1(1467.78,1476.73)
NetR73_1: R73.1 R76.2 U7.9 | length 162.9
  Top Layer w5.66: v1(685.45,1517.93) 685.69,1517.93 707.91,1495.71 U7.9@708.15,1495.71
  Bottom Layer w5.66: v1(685.45,1517.93) 696.9,1506.48 702.41,1506.48 711.5,1497.39 R73.1@711.5,1442.73 R76.2@753.23,1442.73
NetR80_1: R80.1 U5.5 | length 70
  Top Layer w5.66: R80.1@889.52,429.69 945.35,429.69 951.38,423.66 U5.5@951.38,418.02
NetS3_6: S3.6 U4.1 U4.2 | length 300.3
  Top Layer w5.66: U4.1@-346,380.4 U4.2@-320.41,380.4 -320.41,411.68 -317.09,415 -306.47,415 -184.57,536.9 S3.6@-128.83,536.9
NetS4_6: S4.6 U4.6 U4.7 | length 543.5
  Top Layer w8: U4.7@-320.41,555.6 -320.41,590.81 -307.61,603.61 ; U4.6@-294.82,555.6 -294.82,590.81 -307.61,603.61 ; S4.6@-167,775.8 -122.23,775.8 -108.46,762.03 -108.46,622.46 -130.32,600.6 -253.8,600.6 -275.53,622.34 -302.66,622.34 -307.61,617.39 -307.61,603.61
nRESET: J5.6 R64.2 | length 84.9
  Top Layer w5.66: J5.6@2177.8,807.36 2178.43,808 R64.2@2262.43,808
PHY0_25MHZ_CLK: R32.2 R38.2 | length 60
  Top Layer w5.66: R38.2@1136.26,399.02 R32.2@1136.26,459.02
PHY1_25MHZ_CLK: R80.2 R97.2 | length 48.8
  Top Layer w5.66: R97.2@793.52,429.69 R80.2@842.28,429.69
PMIC_COMP1_IN+: J3.37 U2.21 | length 754.6
  Top Layer w5.66: U2.21@1625.26,1138.1 1625.26,1075.33 1657.48,1043.12 v1(1748.11,1043.12)
  L05_SIG2 w4: v1(1748.11,1043.12) 1873.77,917.46 1873.77,638.59 v1(1865.4,630.22)
  Bottom Layer w5.66: v1(1865.4,630.22) 1865.52,630.1 J3.37@1952.59,630.1
PMIC_COMP1_IN-: J3.35 U2.24 | length 1300.5
  Top Layer w5.66: U2.24@1684.32,1138.1 1684.32,1102.49 1692.2,1094.61 v1(1749.61,1094.61)
  L03_SIG1 w4.5: v1(1749.61,1094.61) 1809.3,1034.91 1809.3,808.46 1909.25,708.51 1909.25,628.82 v1(1890.94,610.5)
  L05_SIG2 w4: v1(1749.61,1094.61) 1729.56,1074.56 1729.56,1023.48 1820.78,932.27 1820.78,698.13 1843.26,675.65 1843.26,628.18 1860.94,610.5 v1(1890.94,610.5)
  Bottom Layer w5.66: v1(1890.94,610.5) 1891.03,610.41 J3.35@1952.59,610.41
PMIC_COMP2_IN+: J3.33 U2.28 | length 1234.9
  Top Layer w5.66: U2.28@1625.63,1430.28 1625.26,1430.64 U2.28@1625.26,1433.38 1625.26,1477.84 1666.14,1518.72 v1(1690.78,1518.72)
  L05_SIG2 w4: v1(1690.78,1518.72) 1734.85,1474.67 1734.85,1385.91 1713.94,1365 1713.94,988.74 1799.78,902.91 1799.78,656.47 v1(1865.4,590.85)
  Bottom Layer w5.66: v1(1865.4,590.85) 1865.52,590.73 J3.33@1952.59,590.73
PMIC_COMP2_IN-: J3.31 U2.25 | length 1116.2
  Top Layer w5.66: U2.25@1684.32,1433.38 1703.38,1433.38 1713.03,1443.03 v1(1713.03,1457.12)
  L05_SIG2 w4: v1(1713.03,1457.12) 1676.22,1420.31 1676.22,1036.78 1698.39,1014.61 1698.39,953.85 1789.58,862.66 1789.58,642.49 1860.94,571.13 v1(1890.94,571.13)
  Bottom Layer w5.66: v1(1890.94,571.13) 1891.03,571.04 J3.31@1952.59,571.04
PMIC_EN_OUT: R22.1 U2.17 | length 993.2
  Top Layer w5.66: v1(1546.52,1080.96) U2.17@1546.52,1138.1
  L05_SIG2 w4: v1@923,1495 1218.94,1495 1396.66,1317.28 1396.66,1279.93 1462.16,1214.42 1462.5,1214.42 1546.52,1130.39 v1(1546.52,1080.96)
  Bottom Layer w5.66: R22.1@871,1448.62 871,1481 885,1495 v1@923,1495
  other v1: 923,1497
PMIC_GPIO_1: TP7.1 U2.22 | length 250.9
  Top Layer w5.66: U2.22@1644.95,1138.1 1644.95,1085.05 1668.34,1061.66 1758.34,1061.66 1790,1030 TP7.1@1790,1000
PMIC_SAFE_OUT1: R1.1 R2.2 R15.1 R74.2 U2.31 | length 1615.6
  Top Layer w5.66: R2.2@1316.62,346 R1.1@1365.38,346 1369,349.62 1369,365 v1(1394,390) ; U2.31@1566.21,1433.38 1566.21,1506.76 v1(1577.62,1518.17)
  L05_SIG2 w4: v1(1394,390) 1413.1,409.1 1487.1,409.1 1553,475 1553,888 1641,976 1641,1071.71 1577.62,1135.09 v1(1577.62,1518.17)
  Bottom Layer w5.66: R74.2@1369,395.28 R74.2@1369.72,394.56 1374.28,390 v1(1394,390) ; v1(1577.62,1518.17) 1577.62,1499.09 1616.38,1460.34 R15.1@1616.38,1440
PMIC_SAFE_OUT2: J3.29 R10.1 R11.2 U2.27 | length 2020
  Top Layer w5.66: U2.27@1645.32,1430.28 1645.32,1481.4 1662.83,1498.92 1724.86,1498.92 1745.68,1519.73 R11.2@1745.68,1545 1750.26,1549.58 v1(1750.26,1571.15)
  L03_SIG1 w4.5: v1(1750.26,1571.15) 1795.24,1571.15 1935.77,1430.62 2132.41,1430.62 2156.03,1407 2271.04,1407 2294.99,1383.05 2294.99,869.99 2247.55,822.55 2215.92,822.55 2192.87,845.6 2102.14,845.6 2014.24,757.7 v1(2014.24,551.27)
  Bottom Layer w5.66: v1(1750.26,1571.15) 1765.3,1571.15 1770.74,1565.71 R10.1@1770.74,1539.37 ; J3.29@1952.59,551.36 2014.15,551.36 v1(2014.24,551.27)
PMIC_WAKE1: J1.30 R66.1 U2.6 | length 999.5
  Top Layer w5.66: v1(1322,1070) 1329.99,1077.99 U2.6@1329.99,1138.1
  L05_SIG2 w4: v1(1322,1070) 1309,1057 1309,621.4 1367,563.4 1367,503 1329,465 1329,368.55 1344.87,352.68 ; 1344.89,352.68 1380.16,317.42 1388.06,317.42 v1(1390.69,314.79)
  Bottom Layer w5.66: v1(1322,1070) 1322,1102.55 R66.1@1324.45,1105 ; J1.30@1388.64,253.19 v1@1388.64,314.75
PMIC_WAKE2: J3.39 U2.43 | length 1553.1
  Top Layer w5.66: v1(1325,1490) 1325,1486.66 1329.99,1481.67 U2.43@1329.99,1433.38
  L05_SIG2 w4: v1(1325,1490) 1348,1490 1382.1,1524.1 1425.06,1524.1 1443.67,1505.49 1473.49,1505.49 1532.1,1564.1 1695.9,1564.1 1752,1508 1752,1378 1727,1353 1727,1223.43 1745.14,1205.29 1745.14,1134.86 1890.56,989.44 1890.56,650.25 v1(1890.94,649.87)
  Bottom Layer w5.66: v1(1890.94,649.87) 1891.03,649.78 J3.39@1952.59,649.78
RTCK/EXTC: J5.7 R65.2 | length 107.3
  Top Layer w5.66: R65.2@1849.55,776.57 1850.35,777.36 1882.16,777.36 1892.47,787.68 J5.7@1952.2,787.68
SOM_GPIO6: J3.67 R88.1 | length 2819.1
  Top Layer w5.66: v1(454.33,1548.93) 468.74,1563.34 499.12,1563.34 657.94,1722.16 971.85,1722.16 1060.69,1811 1342.99,1811 1374.48,1811 cw(c1374.48,1796.67) 1388.81,1796.67 1388.81,1772.54 ccw(c1403.14,1772.54) 1417.47,1772.54 1417.47,1797.53 cw(c1431.8,1797.53) 1446.13,1797.53 1446.13,1772.51 ccw(c1460.46,1772.51) 1474.79,1772.51 1474.79,1797.51 cw(c1489.12,1797.51) 1503.45,1797.51 1503.45,1772.49 ccw(c1517.78,1772.49) 1532.11,1772.49 1532.11,1796.67 cw(c1546.44,1796.67) 1546.44,1811 1585.27,1811 1592.17,1804.1 1595,1801.27 1860.23,1536.04 1860.23,1478.44 1839.2,1457.4 1839.2,1428.39 1862.15,1405.43 1862.15,1337.6 1840.33,1315.78 1840.33,1147.53 v1(1865.4,1122.47)
  Bottom Layer w5.66: R88.1@296.63,1208.44 300.47,1212.29 300.47,1366.14 403.27,1468.94 403.27,1497.88 v1(454.33,1548.93) ; v1(1865.4,1122.47) 1865.52,1122.34 J3.67@1952.59,1122.34
SOM_GPIO7: J3.69 R94.1 | length 2747.3
  Top Layer w5.66: v1(84.89,1200.85) 84.89,1179.49 93.87,1170.51 R94.1@95.02,1170.51
  Bottom Layer w5.66: v1@84.89,1204.85 84.89,1248.94 113.79,1277.85 113.79,1635.28 183.52,1705 440.53,1705 460.53,1725 945,1725 1130,1540 1130,1372.22 1197.81,1304.41 1654.65,1304.41 1665.59,1293.47 1665.59,1201.29 1686.79,1180.09 1809.29,1180.09 1847.26,1142.12 v1(1890.94,1142.12) 1891.03,1142.03 J3.69@1952.59,1142.03
SOM_GPIO8: J3.71 R55.1 | length 2715.8
  Top Layer w5.66: v1@420.86,1594.8 422.19,1593.48 422.19,1582.71 429.89,1575 484.08,1575 651.74,1742.66 970.42,1742.66 1059.21,1831.45 1586.59,1831.45 1913.35,1504.69 1913.35,1193.35 1881.84,1161.84 v1(1865.4,1161.84)
  Bottom Layer w5.66: R55.1@214.63,1208.45 214.63,1231.84 266.71,1283.92 266.71,1496.99 343.15,1573.43 399.08,1573.43 402.76,1577.11 403.18,1577.11 v1(422.86,1596.8) ; v1(1865.4,1161.84) 1865.52,1161.71 J3.71@1952.59,1161.71
SOM_GPIO16: J3.65 R81.1 | length 3118.3
  Top Layer w5.66: v1(56.41,987.32) 93.05,987.32 R81.1@93.75,986.62
  Bottom Layer w5.66: v1(56.41,987.32) 111.7,1042.6 111.7,1158.6 104.02,1166.28 104.02,1232.98 147.59,1276.55 198.82,1276.55 225,1302.73 225,1432 128.27,1528.73 128.27,1624 174.58,1670.3 580.06,1670.3 614.26,1704.49 935.51,1704.49 1105,1535 1105,1242.5 1129.22,1218.28 1417.95,1218.28 1429.37,1206.86 1429.37,1173.73 1468.1,1135 1790.23,1135 1822.48,1102.75 1890.94,1102.75 1891.03,1102.66 J3.65@1952.59,1102.66
SOM_GPIO49: J1.53 R86.1 | length 1469.4
  Top Layer w5.66: R86.1@852.26,779.3 886.71,779.3 910,756.01 v1(910,754)
  L03_SIG1 w4.5: v1(910,754) 936.77,780.77 956.97,780.77 965.31,772.42 965.31,741.31 935.17,711.17 935.17,657.84 993.97,599.03 993.97,557.03 1044.56,506.44 1082.98,506.44 1104.44,527.91 1125.36,527.91 1138.52,514.74 v1(1138.52,497.65)
  L05_SIG2 w4: v1(1138.52,497.65) 1138.52,332.37 1152.42,318.47 1152.42,310.86 1152.42,274.56 1143.87,266.01 1054.75,266.01 1046.2,257.46 1046.2,240.36 1054.75,231.81 1154.68,231.81 1163.23,223.26 1163.23,206.16 1154.68,197.61 1055.41,197.61 1046.86,189.06 1046.86,171.96 1055.41,163.41 1143.87,163.41 1152.42,154.86 1152.42,136.75 v1(1152.42,101.47)
  Bottom Layer w5.66: J1.53@1152.42,27.59 v1(1152.42,101.47)
SOM_GPIO50: J1.51 R93.1 | length 1421.1
  Top Layer w5.66: R93.1@852.26,738.3 856.6,742.64 872,742.64 v1@886.08,756.72
  L03_SIG1 w4.5: v1(884.08,756.72) 884.08,724.9 909.73,699.25 909.73,659.69 978.76,590.66 978.76,523.29 1040.51,461.54 1132.99,461.54 1176.45,505 v1(1200,505)
  L05_SIG2 w4: v1(1124,-61) 1220.26,35.26 1262.86,35.26 1291,63.4 1291,125.39 1284.28,132.11 1284.28,183.73 1181.54,286.47 1181.54,446.54 1196,461 1196,501 v1(1200,505)
  Bottom Layer w5.66: v1(1124,-61) 1159.06,-61 1172.11,-47.95 J1.51@1172.11,27.59
SOM_GPIO51: J1.49 R52.1 | length 1379
  Top Layer w5.66: R52.1@852.26,697.3 856.19,697.3 865.17,688.32 880.61,672.86 909.9,672.86 926,656.76 926,563 939,550 1019,550 1080,489 v1(1103,489)
  L05_SIG2 w4: v1(1103,489) 1103.62,489 1162.1,547.48 1186.48,547.48 1197.86,558.86 1214.17,558.86 1226.2,546.82 1226.2,491.07 1209.5,474.37 1209.5,447.49 1192.8,430.79 1192.8,300.2 1294.48,198.52 1294.48,136.34 1313.46,117.36 1313.46,-20.95 1288.06,-46.35 v1(1205.03,-46.35)
  Bottom Layer w5.66: J1.49@1191.79,27.59 1191.79,-33.11 v1(1205.03,-46.35)
SOM_GPIO76: J3.61 R89.1 | length 2996.6
  L08_SIG3 w4.5: v1(852,1351) 908.95,1294.05 908.95,1182.11 ccw(c927.27,1182.11) 945.58,1182.11 945.58,1356.87 cw(c963.89,1356.87) 982.2,1356.87 982.2,1182.11 ccw(c1000.52,1182.11) 1018.83,1182.11 1018.83,1356.87 cw(c1037.14,1356.87) 1055.46,1356.87 1055.46,1182.11 ccw(c1073.77,1182.11) 1092.08,1182.11 1092.08,1211.3 1101.56,1220.78 1652.6,1220.78 1668.4,1236.58 1668.4,1296.54 1680.3,1308.45 1712.64,1308.45 1731.19,1327 1803,1327 1832,1298 1832,1216.73 1791.19,1175.91 1791.19,1127.81 1801.09,1117.91 1834.59,1117.91 1847.4,1130.71 1847.4,1165.5 1861.9,1180 1895,1180 1908.04,1166.96 1908.04,1083.04 1890.94,1065.94 v1(1890.94,1063.38)
  Bottom Layer w5.66: R89.1@628.5,1210.04 608.51,1210.04 581,1237.55 581,1305 601,1325 682,1325 714,1357 778.33,1357 784.33,1351 v1(852,1351) ; v1(1890.94,1063.38) 1890.98,1063.33 1952.54,1063.33 J3.61@1952.59,1063.29
TCK: J5.3 R61.2 R65.1 | length 978.2
  Top Layer w5.66: R61.2@1811.65,111.85 v1(1842.69,111.85) ; v1(1849.38,855.38) 1849.38,823.98 R65.1@1849.55,823.81 1850.41,822.95 1897.12,822.95 1901.22,827.05 J5.3@1952.2,827.05
  L03_SIG1 w4.5: v1(1842.69,111.85) 1842.69,204.53 1927.28,289.12 1927.28,719.72 1849.38,797.62 v1(1849.38,855.38)
TDI: J5.5 R63.2 | length 920.5
  Top Layer w5.66: R63.2@1811.65,51.69 v1(1842.69,51.69) ; J5.5@1952.2,807.36 v1(2014.74,807.36)
  L03_SIG1 w4.5: v1(1842.69,51.69) 1867.48,76.48 1867.48,188.94 1966.42,287.89 1966.42,759.05 v1(2014.74,807.36)
TDO: J5.4 R62.2 | length 1042
  Top Layer w5.66: R62.2@1811.65,-8.46 v1(1842.69,-8.46) ; v1(2115.26,827.05) J5.4@2177.8,827.05
  L03_SIG1 w4.5: v1(1842.69,-8.46) 1842.69,12.3 2090.21,259.82 2090.21,739.05 2115.26,764.11 v1(2115.26,827.05)
TGT_PD: J5.15 R87.2 | length 103.1
  Top Layer w5.66: R87.2@1849.55,707.81 1951.08,707.81 J5.15@1952.2,708.94
TMS: J5.2 R60.2 | length 1074
  Top Layer w5.66: R60.2@1811.65,172.01 v1@1892.13,172.01 ; J5.2@2177.8,846.73 v1(2240.33,846.73)
  L03_SIG1 w4.5: v1(1892.4,171.74) 1986.15,265.48 1986.15,751.83 2103.43,869.12 2217.94,869.12 v1(2240.33,846.73)
VCC_6V0: C54.1 C55.1 C56.1 C57.1 C58.1 C59.1 C60.1 C66.1 R21.2 TP11.1 U2.41 U2.42 U7.6 | length 74.3
  Bottom Layer w20: v1(799,1476) 806.56,1476 830,1452.56 R21.2@830,1448.62 ; v1(1352.36,1521.64) C60.1@1352.36,1551.34
VDD_1V25: C2.2 C6.1 C7.1 C8.1 C9.1 C10.1 C11.1 C12.1 C15.1 L1.2 TP1.1 U1.E8 U1.E9 U1.E12 U1.F6 U1.F12 U1.G6 U1.L11 U1.L12 | length 427.1
  Top Layer w5.66: v1(365.77,911.2) U1.G6@381.52,895.46 ; v1(365.77,942.7) U1.F6@381.52,926.95 ; v1(428.76,974.2) U1.E8@444.51,958.45 ; U1.E9@476.01,958.45 v1(491.75,974.2) ; U1.L11@539,769.47 v1(554.75,753.72) ; U1.L12@570.49,769.47 v1(586.24,753.72) ; U1.F12@570.49,926.95 v1(586.24,942.7) ; U1.E12@570.49,958.45 v1(586.24,974.2)
  Bottom Layer w5: v1(365.77,911.2) 381.56,895.42 381.56,873.57 371.93,863.95 371.93,852.01 C10.1@368.14,848.21 ; C11.1@552.38,848.21 556.32,848.21 570.49,862.39 570.49,926.95 v1(586.24,942.7)
  Bottom Layer w12: v1(586.24,942.7) v1(586.24,974.2)
  Bottom Layer w18: v1(365.77,911.2) v1(365.77,942.7)
  other v1: 495,1155 495,1195 495,1235
VDDA_3V3: C3.1 C13.1 C14.1 C83.1 C84.1 C85.1 L2.2 TP14.1 U1.K6 U1.L6 U4.8 U8.2 | length 508.4
  Top Layer w5.66: v1(365.77,753.72) U1.L6@381.52,769.47 ; v1(365.77,785.22) U1.K6@381.52,800.97
  Top Layer w10: U8.2@63.39,214.02 123.84,214.02 C85.1@124.28,214.47 120.35,210.54 120.35,181.83 v1(118.82,180.3) C84.1@118.82,151.58 ; v1(290.53,550.61) 291.65,549.5 C3.1@333,549.5
  Top Layer w15: U4.8@-346,555.6 -346,639.6 C83.1@-346.41,640.01 v1(-319.6,640.01)
  Bottom Layer w5.66: C13.1@318.75,848.21 322.69,848.21 336.36,834.55 341.66,834.55 365.77,810.44 v1(365.77,785.22)
  Bottom Layer w10: v1(290.53,550.61) 315.2,550.61 C14.1@318,553.41 ; v1@761.42,553.68 L2.2@796.67,553.68
  Bottom Layer w18: v1(365.77,753.72) v1(365.77,785.22)
  other v1: 761.22,553.49
VDDIO_3V3: C16.1 C17.1 C18.1 C19.1 C20.1 C21.1 C22.1 C23.1 C24.1 C25.1 C26.1 C27.1 C76.1 C81.1 C88.1 C91.1 C92.2 C93.2 L3.2 TP2.1 U1.E6 U1.E7 U1.E10 U1.E11 U1.F15 U1.G12 U1.H6 U1.H12 U1.J6 U1.J12 U1.K12 U1.L8 U1.L9 U1.L10 U1.L13 U1.M10 U1.M11 | length 1260.5
  Top Layer w5.66: v1(365.77,879.71) U1.H6@381.52,863.96 ; v1(365.77,974.2) U1.E6@381.52,958.45 ; U1.J6@381.08,832.9 U1.J6@381.52,832.46 v1(396.83,817.15) ; v1(397.27,974.2) U1.E7@413.01,958.45 ; v1(428.76,753.72) U1.L8@444.51,769.47 ; U1.L9@476.01,769.47 v1(491.75,753.72) ; U1.M10@507.5,737.98 v1(523.25,722.23) ; U1.L10@507.5,769.47 v1(523.25,753.72) ; U1.E10@507.5,958.45 v1(523.25,974.2) ; U1.M11@539,737.98 v1(554.75,722.23) ; U1.E11@539,958.45 v1(554.75,974.2) ; U1.K12@570.49,800.97 v1(586.24,785.22) ; U1.J12@570.49,832.46 v1(586.24,816.72) ; U1.H12@570.49,863.96 v1(586.24,879.71) ; U1.G12@570.49,895.46 v1(586.24,911.2) ; U1.L13@601.99,769.47 v1(617.74,753.72) ; U1.F15@664.98,926.95 v1(680.73,942.7)
  Top Layer w8: v1(482.54,549.49) 482.54,548.97 490.16,541.36 C92.2@490.16,519.85 ; v1(523.54,549.49) 523.54,548.97 531.16,541.36 C24.1@531.16,519.85 ; v1(564.74,549.49) 564.74,548.97 572.35,541.36 C25.1@572.35,519.85 ; v1(605.74,549.49) 605.74,548.97 613.35,541.36 C76.1@613.35,519.85
  Top Layer w10: v1@761.42,582.23 L3.2@796.67,582.23 ; v1@769.76,831.3 C18.1@805.01,831.3 ; v1@769.76,872.3 C16.1@805.01,872.3
  Top Layer w20: v1(37,915) 37,903.21 69.67,870.54 C19.1@95.1,870.54 C21.1@144.93,870.53
  Bottom Layer w8: v1(482.54,549.49) 482.54,548.97 490.16,541.36 C22.1@490.16,519.85 ; v1(523.54,549.49) 523.54,548.97 531.16,541.36 C23.1@531.16,519.85 ; v1@564.54,549.49 564.54,548.97 572.16,541.36 C20.1@572.16,519.85 ; v1@605.54,549.52 605.54,549 613.16,541.38 C27.1@613.16,519.88
  Bottom Layer w10: C20.1@564.83,519.95 C20.1@564.93,519.85 ; v1(586.24,911.2) v1(586.24,879.71) 586.24,863.11 590.39,858.96 590.39,855.02 C88.1@597.2,848.21 ; C88.1@601.14,848.21 C88.1@597.2,848.21 ; v1(617.74,753.72) v1(586.24,785.22) v1(586.24,816.72) 586.24,833.32 590.39,837.46 590.39,841.4 C88.1@597.2,848.21 ; v1@769.76,831.3 C17.1@805.01,831.3 ; v1@769.76,872.3 C26.1@805.01,872.3
  Bottom Layer w20: v1(37,915) 100.47,915 C93.2@144.93,870.53
  other v1: 761.22,582.03 769.57,831.1 769.57,876.1
VREF_DEBUG: J5.1 R59.2 | length 101.6
  Top Layer w10: R59.2@1880.05,881.79 1880.05,856.32 1889.64,846.73 J5.1@1952.2,846.73
VREF_TRACE: J5.12 R85.2 | length 85.8
  Top Layer w5.66: J5.12@2177.8,748.31 2262.91,748.31 R85.2@2263.43,748.82
VREFHIAB: J1.85 S3.4 | length 1151.3
  Top Layer w5.66: S3.4@-128.83,399.1 -128.83,363.31 -116,350.47 -116,303.8 -94.09,281.89 -87.18,281.89 -66,260.71 -66,186.42 -50.05,170.48 -6.52,170.48 v1(-6.37,170.63)
  L08_SIG3 w4.5: v1(-6.37,170.63) 99.37,170.63 129.32,140.68 321.47,140.68 345.79,165 463,165 490,138 490,91 614.65,-33.65 v1(639.73,-33.65)
  Bottom Layer w5.66: v1(639.73,-33.65) 641.37,-32.02 J1.85@641.37,29.55
VREFHICDE: J1.83 S4.4 | length 1861.4
  Top Layer w10: S4.4@-167,638 -154.19,650.81 v1(-154.19,670.91)
  L08_SIG3 w4.5: v1(-154.19,670.91) -176.28,693 -319,693 -375.16,636.84 -375.16,411.87 -358.52,395.23 -358.52,380.75 -341.88,364.11 -309.59,364.11 -49.48,104 58.92,104 245.08,-82.16 637.49,-82.16 v1(659.99,-59.66)
  Bottom Layer w5.66: v1(659.99,-59.66) 660.11,-59.54 J1.83@660.11,27.53
pads on no net: FID1.1 FID2.1 FID3.1 FID4.1 FID5.1 FID6.1 J1.26 J1.27 J1.47 J1.79 J1.80 J1.81 J1.82 J1.84 J1.86 J1.87 J1.88 J1.MH1 J1.MH2 J2.1 J2.2 J2.3 J2.4 J2.5 J2.6 J2.7 J2.8 J2.9 J2.10 J2.11 J2.12 J2.13 J2.14 J2.15 J2.16 J2.17 J2.18 J2.19 J2.20 J2.22 J2.24 J2.37 J2.38 J2.39 J2.40 J2.41 J2.42 J2.43 J2.44 J2.45 J2.47 J2.49 J2.51 J2.61 J2.62 J2.63 J2.64 J2.65 J2.66 J2.67 J2.68 J2.69 J2.70 J2.71 J2.72 J2.73 J2.74 J2.75 J2.76 J2.77 J2.78 J2.79 J2.80 J2.81 J2.82 J2.83 J2.84 J2.85 J2.86 J2.87 J2.88 J2.89 J2.90 J2.91 J2.92 J2.93 J2.94 J2.95 J2.96 J2.101 J2.102 J2.MH1 J2.MH2 J3.1 J3.2 J3.3 J3.4 J3.5 J3.6 J3.7 J3.8 J3.9 J3.10 J3.11 J3.12 J3.13 J3.14 J3.15 J3.16 J3.17 J3.18 J3.19 J3.20 J3.21 J3.22 J3.23 J3.24 J3.25 J3.26 J3.28 J3.30 J3.32 J3.34 J3.36 J3.38 J3.40 J3.41 J3.42 J3.43 J3.44 J3.45 J3.46 J3.47 J3.48 J3.49 J3.50 J3.51 J3.52 J3.53 J3.54 J3.55 J3.56 J3.57 J3.58 J3.60 J3.62 J3.64 J3.66 J3.68 J3.70 J3.72 J3.73 J3.74 J3.75 J3.77 J3.79 J3.81 J3.86 J3.98 J3.110 J3.MH1 J3.MH2 J5. J5.8 J5.9 J5.10 J5.11 J5.13 J5.14 J5.17 J5.18 J5.19 J5.20 J5.21 J5.22 J5.23 J5.24 J5.25 J5.26 J5.27 J5.28 J5.29 J5.30 J5.31 J5.32 J5.33 J5.34 J5.35 J5.36 J5.37 J5.39 J5.41 J5.43 J5.45 J5.47 J5.48 J5.49 J5.50 J5.51 J5.53 J5.55 J5.59 J5.60 MH1.1 MH2.1 MH3.1 MH4.1 U1.M12 U2.19 U3.0 U5.7 U7.1 U8.1 U8.3 U8.7 U8.8
copper on no net:
  other v1: -281.11,661.36 -271.81,908.81

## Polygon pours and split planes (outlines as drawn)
GND on L06_PWR "NONET_L-01_P-001" (solid, remove dead copper, pour order 94): -410,2121.49 -410,-155 2345.9,-155 2345.9,2121.49
3V3_OUT on L06_PWR "3V3_OUT_L06_P093" (solid, remove dead copper, pour order 93): 206.85,2066 567,2066 652,1981 652,1864 712,1804 1737,1804 1916.32,1624.68 2240.45,1624.68 2283,1582.13 2283,112 2169,-2 1669.79,-2 1599.68,68.11 1599.68,193.8 1510.1,283.38 1293.36,283.38 1275.49,300.45 1275.49,496.5 1274.66,497.33 1277.81,570.19 1256.42,591.58 1199.28,591.58 1178.7,571 1123.51,571 1032.53,480.02 1032.53,366.27 1012.3,346.05 1012.3,321.6 1001.32,310.62 916.64,310.62 863.23,364.03 863.23,1286.77 560,1590 331.46,1590 148.22,1773.24 148.22,2007.37
VDDA_3V3 on L06_PWR "VDDA_3V3_L06_P059" (solid, remove dead copper, pour order 59): 161.83,114.82 -150.17,114.82 -195.47,69.53 -358.53,69.53 -379,90 -379,197 -335,241 -335,588 -335,756 -284.27,806.73 404.83,806.73 418.36,793.2 418.36,558.03 451,525.39 704.04,525.39 722.62,543.98 722.62,568 727.18,572.56 801.16,572.56 823.61,550.11 823.61,424.27 789.34,390 333,390 286,343 286,239
VDD_1V25 on L06_PWR "VDD_1V25_L06_P037" (solid, remove dead copper, pour order 37): 574.89,674.25 576.9,672.24 703.2,672.24 708.97,678.01 708.97,901.51 686.61,923.87 671.13,923.87 658.44,936.56 658.44,1296.56 581.72,1373.28 364.19,1373.28 349.78,1357.26 315.78,1323.26 315.78,1207.24 418.51,1104.51 418.51,954.67 416.08,952.23 361.7,952.23 356.14,946.68 356.14,904.15 359.19,901.11 500.03,901.11 503.37,904.45 503.37,989.16 511.24,997.03 562.82,997.03 576.47,983.37 576.47,939.69 586.04,930.12 601.28,930.12 607.16,924.24 607.16,807.08 645.84,768.41 645.84,750.33 627.01,731.5 608.47,731.5 595.71,744.26 595.71,762.17 591.49,766.39 549.5,766.39 543.39,760.28 543.39,747.17 549.5,741.06 564.14,741.06 574.89,730.31
VDDIO_3V3 on L06_PWR "VDDIO_3V3_L06_P038" (solid, remove dead copper, pour order 38): 69,1310.67 69,1008 23,962 23,913.88 95.74,841.14 144.41,841.14 178.81,806.73 404.83,806.73 418.36,793.2 418.36,555.8 448.74,526.62 705.27,526.62 718.07,539.42 718.07,563.45 727.18,572.56 764.85,572.56 830,637.7 830,976.9 809.13,997.77 672.81,997.77 665,989.96 665,945.32 724.1,886.22 724.1,678.01 718,671.9 577.23,671.9 574.89,674.25 574.89,730.31 564.14,741.06 549.5,741.06 543.39,747.17 543.39,760.28 550.92,767.81 590.07,767.81 599.35,758.52 599.35,740.61 608.47,731.5 627.01,731.5 645.84,750.33 645.84,767.26 637.57,775.54 603.01,775.54 596.82,781.73 596.82,919.34 576.47,939.69 576.47,983.37 562.82,997.03 511.24,997.03 503.37,989.16 503.37,904.45 488.92,890 349.05,890 345.42,893.32 345.42,960.33 350.04,964.94 410.44,964.94 418.51,973.01 418.51,1104.51 297.02,1226.01 297.02,1356.05 276.45,1376.62 134.94,1376.62
5V0_OUT_CAN on L06_PWR "TOP_LAYER_NONET_P-001" (solid, remove dead copper, pour order 29): 1302.4,385.47 1318.87,369 1435,369 1570,504 1570,590 1626,646 1626,708 1701,783 1769.68,783 1799.78,813.1 1799.78,889.08 1791.66,897.21 1645.64,897.21 1557.76,809.33 1557.76,661.76 1328,432 1302.4,406.4
GND on Top Layer "NONET_L-01_P-001" (solid, remove dead copper, pour order 95): -398.96,2142.63 -398.96,-133.86 2356.94,-133.86 2356.94,2142.63
5V0_OUT_CAN on Top Layer "TOP_LAYER_NONET_P-001" (solid, remove dead copper, pour order 92): 1577.75,965.84 1575.65,967.93 1540.44,967.93 1538.38,965.87 1538.38,921.99 1553.78,906.58 1566.72,906.58 1672.44,800.86 1759.86,800.86 1772,813 1772,866 1748.21,889.79 1631.21,889.79 1577.75,943.25
GND on Top Layer "TOP_LAYER_NONET_P-001" (solid, remove dead copper, pour order 86): 1095,1773 1208,1773 1234.88,1746.12 1300.53,1746.12 1309.38,1737.27 1309.38,1704.97 1300.53,1696.12 1063.93,1696.12 1055.04,1705 1055.04,1738.52 1089.52,1773
GND on Top Layer "TOP_LAYER_NONET_P-001" (solid, remove dead copper, pour order 84): 1383.86,1660.16 1383.86,1539.52 1415.36,1539.52 1421.38,1545.55 1421,1545.94 1421,1600.29 1436.28,1615.56 1511.01,1615.56 1525.25,1600.83 1525.25,1530 1530.25,1525 1551.75,1525 1557,1530.25 1557,1578 1560.5,1581.5 1676.81,1581.5 1679,1583.69 1679,1620 1652,1647 1476,1647 1443,1680 1403.7,1680
GND on Bottom Layer "NONET_L-01_P-001" (solid, remove dead copper, pour order 96): -410,2121.49 -410,-155 2345.9,-155 2345.9,2121.49
GND on Bottom Layer "TOP_LAYER_NONET_P-001" (solid, remove dead copper, pour order 82): 1383.86,1539.52 1415.36,1539.52 1427.41,1551.58 1427.41,1583.08 1445.15,1600.81 1627.81,1600.81 1647.01,1581.61 1647.01,1544.81 1652,1539.82 1661.82,1539.82 1664.73,1542.73 1664.73,1566.73 1668.41,1570.41 1725.43,1570.41 1726.81,1571.79 1726.81,1598.8 1713.61,1612 1678.63,1612 1637.63,1653 1470,1653 1433,1690 1401,1690 1381,1670 1381,1542.38
GND on Bottom Layer "TOP_LAYER_NONET_P-001" (solid, remove dead copper, pour order 80): 1536.92,352.87 1608.87,352.87 1619,363 1619,524 1609,534 1588,534 1576.45,522.45 1576.45,442.87 1559.95,426.37 1547.29,426.37 1529.54,408.19 1529.54,360.26
GND on L02_GND1 "NONET_L-01_P-001" (solid, remove dead copper, pour order 60): -410,2121.49 -410,-155 2345.9,-155 2345.9,2121.49
GND on L04_GND2 "NONET_L-01_P-001" (solid, remove dead copper, pour order 68): -410,2121.49 -410,-155 2345.9,-155 2345.9,2121.49
GND on L09_GND4 "NONET_L-01_P-001" (solid, remove dead copper, pour order 70): -410,2121.49 -410,-155 2345.9,-155 2345.9,2121.49
GND on L07_GND3 "GND_L07_P074" (solid, remove dead copper, pour order 74): -410,2121.49 -410,-155 2345.9,-155 2345.9,2121.49
GND on L03_SIG1 "NONET_L-01_P-001" (solid, remove dead copper, pour order 64): -428.64,2160.2 -428.64,-180 2327.26,-180 2327.26,2160.2
GND on L08_SIG3 "NONET_L-01_P-001" (solid, remove dead copper, pour order 66): -410,2121.49 -410,-155 2345.9,-155 2345.9,2121.49
GND on L05_SIG2 "NONET_L-01_P-001" (solid, remove dead copper, pour order 65): -410,2121.49 -410,-155 2345.9,-155 2345.9,2121.49

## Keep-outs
Keep-Out Layer:
  circle w10: c-205.12,165.04 r40
  circle w10: c-205.12,1744.96 r40
  circle w10: c2170.12,957.56 r40
  circle w10: c2170.12,1744.96 r40
  circle w10: c2170.12,165.04 r40
  circle w10: c1774.96,245.12 r40
  circle w10: c195.04,245.12 r40
  circle w10: c0,0 r150
  circle w10: c0,1905 r150
  circle w10: c1970,1905 r150
  circle w10: c1760,435 r128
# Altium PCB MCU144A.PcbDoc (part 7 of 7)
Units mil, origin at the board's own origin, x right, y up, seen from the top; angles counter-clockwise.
Board outline 2755.9 x 2276.49 mil, 10 copper layers (Top Layer, L02_GND1, L03_SIG1, L04_GND2, L05_SIG2, L06_PWR, L07_GND3, L08_SIG3, L09_GND4, Bottom Layer), stack 60.4 mil thick; 253 components, 312 nets, 1289 pads, 832 vias.

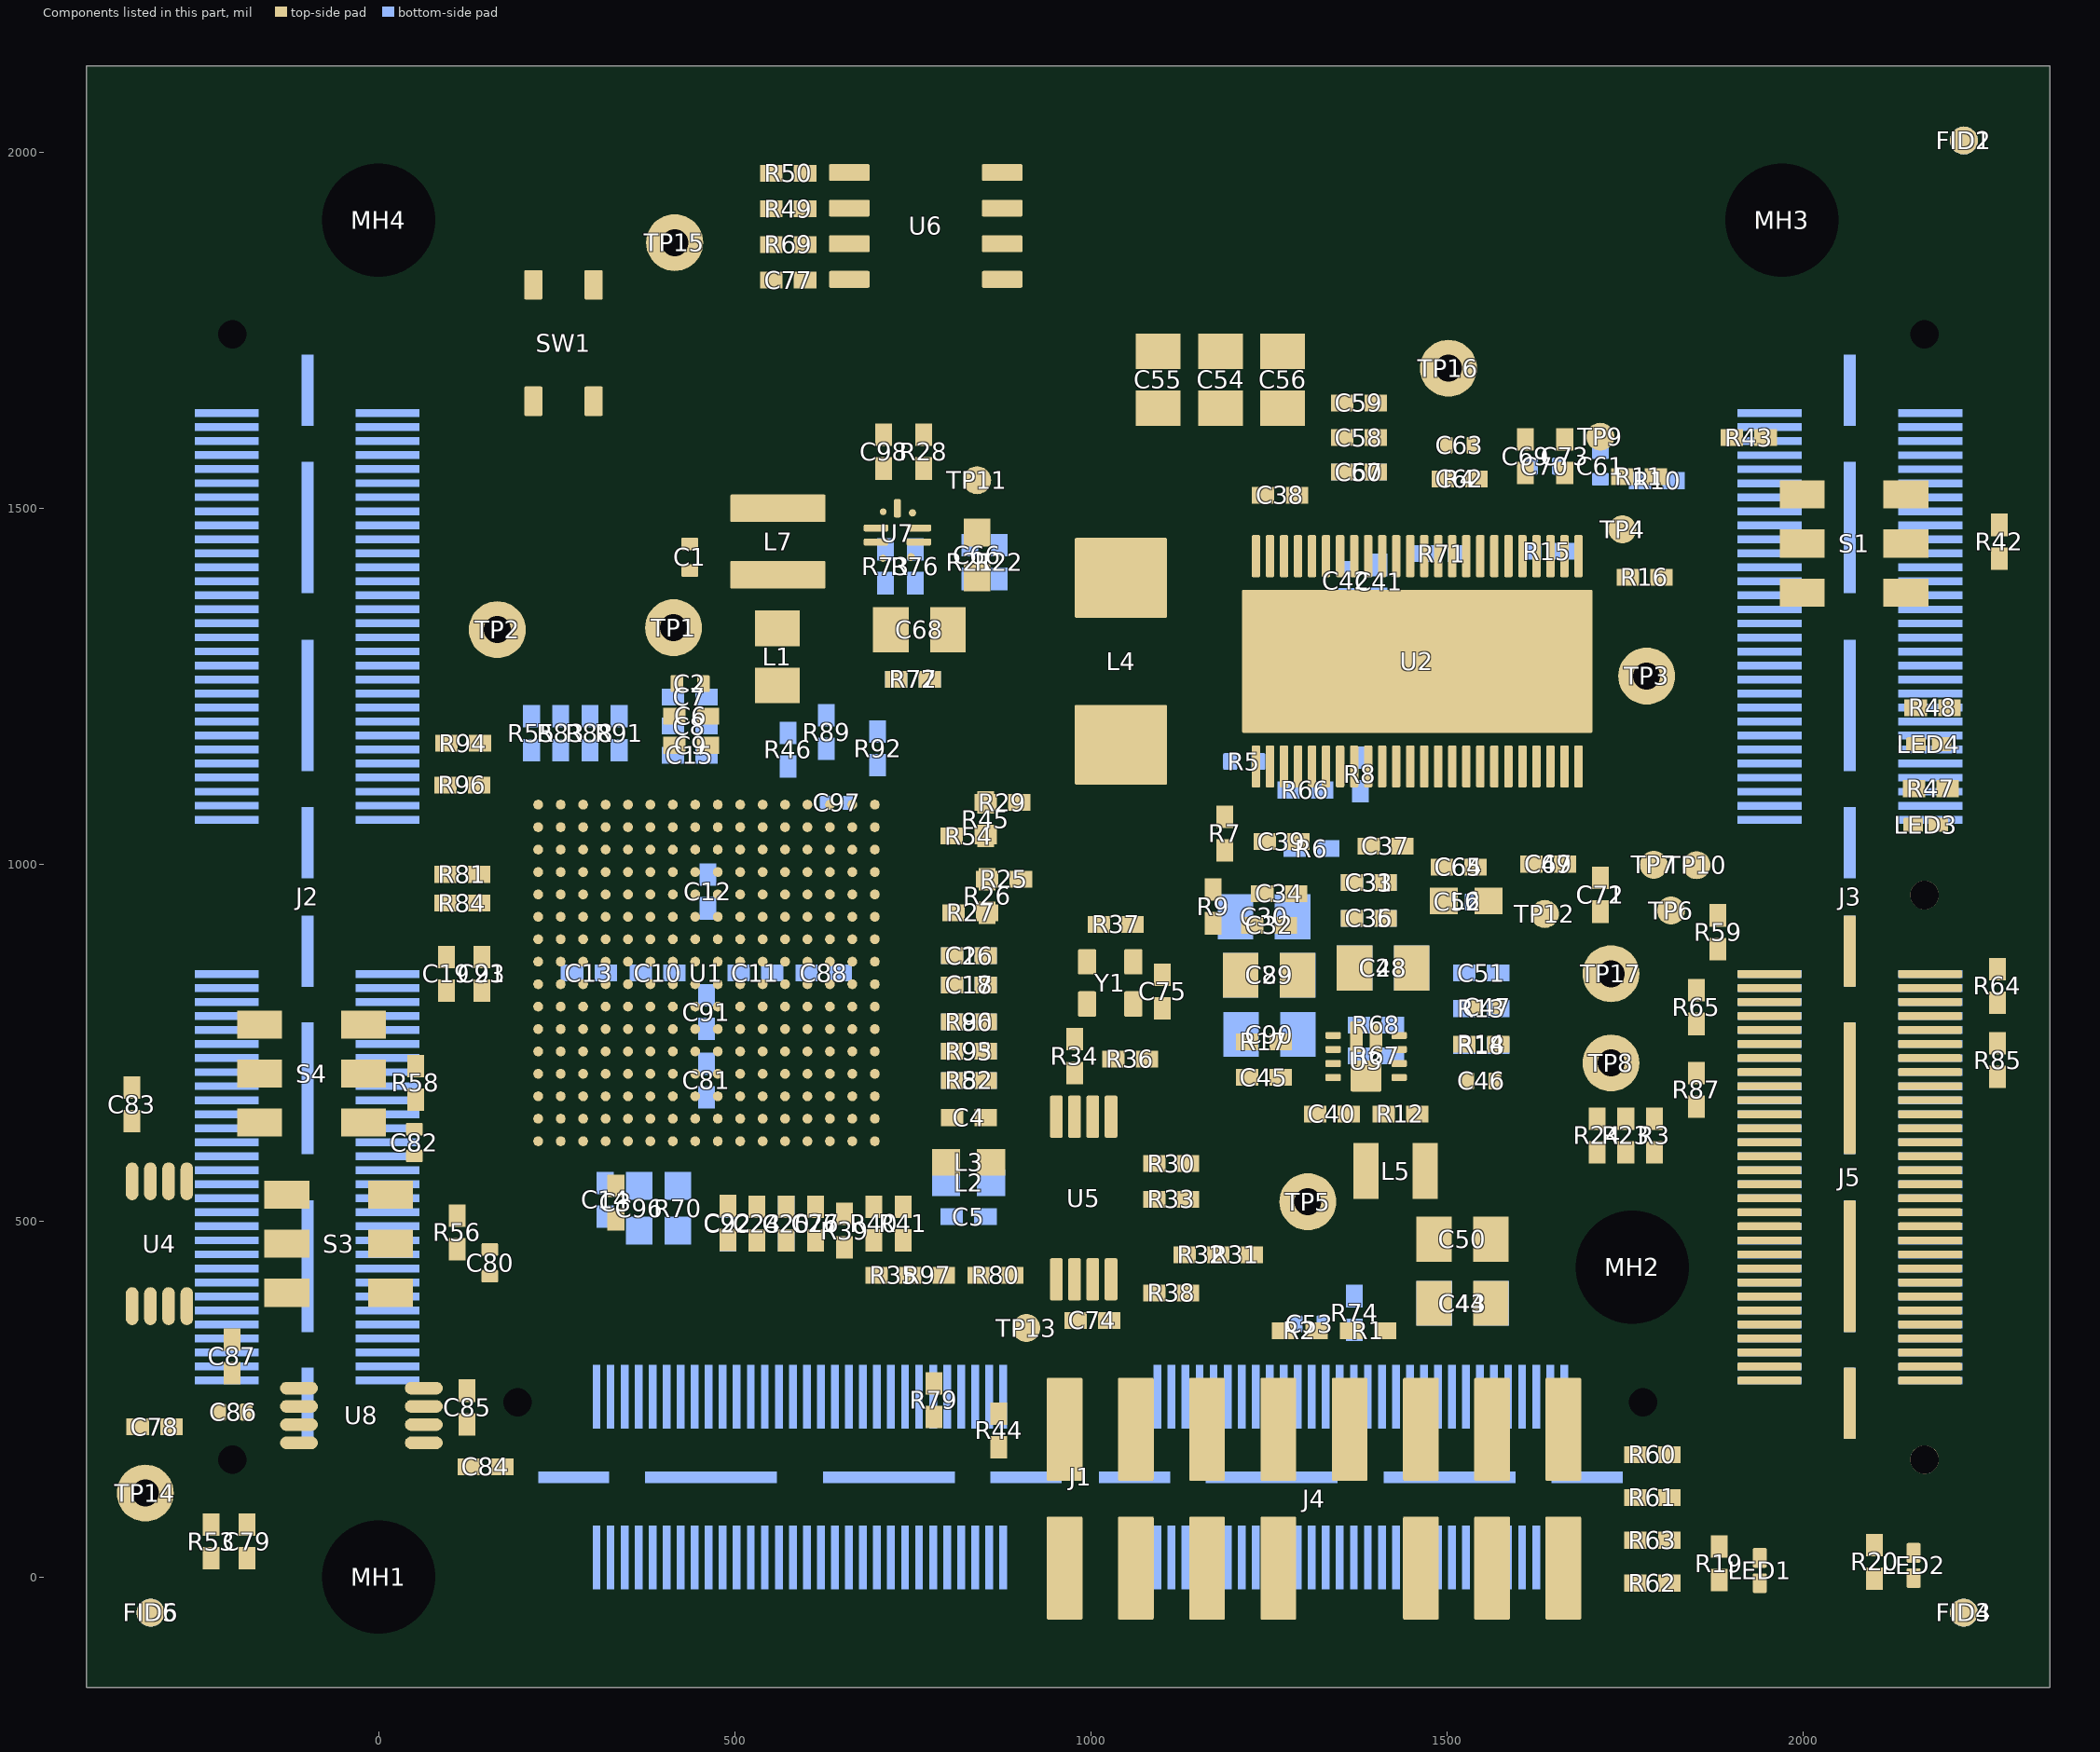
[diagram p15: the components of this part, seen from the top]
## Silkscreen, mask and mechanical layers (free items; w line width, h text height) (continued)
Drill Drawing:
  circle w10: c-527.92,5825.38 r22.1
  circle w10: c-527.92,5825.38 r36.84
  circle w10: c-527.92,5328.1 r36.84
  lines w10: -564.75,4830.82 -527.92,4793.99 -491.08,4830.82 -527.92,4867.66 -564.75,4830.82 ; -564.75,4959.75 -491.08,4959.75 -491.08,5033.42 -564.75,5033.42 -564.75,4959.75 ; -564.75,5125.51 -527.92,5143.93 -491.08,5125.51 -509.5,5162.34 -491.08,5199.18 -527.92,5180.76 -564.75,5199.18 -546.34,5162.34 -564.75,5125.51 ; -564.75,5457.03 -491.08,5457.03 -491.08,5530.7 -564.75,5530.7 -564.75,5457.03 ; -564.75,5641.21 -546.34,5641.21 -527.92,5622.79 -509.5,5641.21 -491.08,5641.21 -509.5,5659.62 -491.08,5678.04 -509.5,5678.04 -527.92,5696.46 -546.34,5678.04 -564.75,5678.04 -546.34,5659.62 -564.75,5641.21 ; -550.02,4974.48 -505.82,4974.48 -505.82,5018.68 -550.02,5018.68 -550.02,4974.48
  lines w15: -630.5,4744.26 3575.25,4744.26 ; -630.5,5904.58 3575.25,5904.58 ; -180.02,4578.5 -180.02,6070.34 ; 221.95,4578.5 221.95,6070.34 ; 1008.5,4578.5 1008.5,6070.34 ; 1354.02,4578.5 1354.02,6070.34 ; 1854.23,4578.5 1854.23,6070.34 ; 2820,4578.5 2820,6070.34 ; -630.5,4578.5 3575.25,4578.5 3575.25,6070.34 -630.5,6070.34 -630.5,4578.5
  text "Symbol" at -531.04,5954.31 h96
  text "Count" at -130.29,5954.31 h96
  text "Hole Size" at 271.68,5954.31 h96
  text "Plated" at 1058.22,5954.31 h96
  text "Hole Type" at 1403.75,5954.31 h96
  text "Drill Layer Pair" at 1903.96,5954.31 h96
  text "Hole Tolerance" at 2869.73,5954.31 h96
  text "54" at -130.29,5788.55 h80
  text "7.87mil (0.200mm)" at 271.68,5788.55 h80
  text "PTH" at 1058.22,5788.55 h80
  text "Round" at 1403.75,5788.55 h80
  text "Top Layer - Bottom Layer" at 1903.96,5788.55 h80
  text "+/-3.00mil" at 2869.73,5788.55 h80
  text "778" at -130.29,5622.79 h80
  text "8.00mil (0.203mm)" at 271.68,5622.79 h80
  text "PTH" at 1058.22,5622.79 h80
  text "Round" at 1403.75,5622.79 h80
  text "Top Layer - Bottom Layer" at 1903.96,5622.79 h80
  text "+/-3.00mil" at 2869.73,5622.79 h80
  text "4" at -130.29,5457.03 h80
  text "37.99mil (0.965mm)" at 271.68,5457.03 h80
  text "PTH" at 1058.22,5457.03 h80
  text "Round" at 1403.75,5457.03 h80
  text "Top Layer - Bottom Layer" at 1903.96,5457.03 h80
  text "5" at -130.29,5291.27 h80
  text "37.99mil (0.965mm)" at 271.68,5291.27 h80
  text "PTH" at 1058.22,5291.27 h80
  text "Round" at 1403.75,5291.27 h80
  text "Top Layer - Bottom Layer" at 1903.96,5291.27 h80
  text "+/-3.00mil" at 2869.73,5291.27 h80
  text "5" at -130.29,5125.51 h80
  text "40.00mil (1.016mm)" at 271.68,5125.51 h80
  text "NPTH" at 1058.22,5125.51 h80
  text "Round" at 1403.75,5125.51 h80
  text "Top Layer - Bottom Layer" at 1903.96,5125.51 h80
  text "+/-3.00mil" at 2869.73,5125.51 h80
  text "2" at -130.29,4959.75 h80
  text "40.16mil (1.020mm)" at 271.68,4959.75 h80
  text "NPTH" at 1058.22,4959.75 h80
  text "Round" at 1403.75,4959.75 h80
  text "Top Layer - Bottom Layer" at 1903.96,4959.75 h80
  text "+/-3.00mil" at 2869.73,4959.75 h80
  text "4" at -130.29,4793.99 h80
  text "159.00mil (4.039mm)" at 271.68,4793.99 h80
  text "NPTH" at 1058.22,4793.99 h80
  text "Round" at 1403.75,4793.99 h80
  text "Top Layer - Bottom Layer" at 1903.96,4793.99 h80
  text "+/-3.00mil" at 2869.73,4793.99 h80
  text "852 Total" at -130.29,4628.23 h80
  text ".Layer_Name" at -323.89,-2500.75 h60
M17 Embedded Cavity:
  text ".Layer_Name" at -335.67,-2480.71 h60
M18 Embedded Assembly:
  text ".Layer_Name" at -335.67,-2480.71 h60
M19 Embedded Keepout:
  text ".Layer_Name" at -335.67,-2480.71 h60
Sheet:
  drawing of 56 lines, arcs and shapes, not listed
  text "1" at -161.06,6394.24 h70
  text "2" at 2334.61,6394.24 h70
  text "3" at 4823.95,6394.24 h70
  text "4" at 7330.62,6394.24 h70
  text "5" at 9829.61,6394.24 h70
  text "6" at 12334.61,6394.24 h70
  text "A" at -1317.39,5251.24 h70
  text "A" at 13482.61,5251.24 h70
  text "B" at -1317.39,2871.24 h70
  text "B" at 13482.61,2871.24 h70
  text "C" at -1317.39,496.24 h70
  text "C" at 13482.61,496.24 h70
  text "PROJECT TITLE:" at 10442.61,-1364.76 h45
  text ".PRJ_Title" at 10492.61,-1498.08 h70
  text "DESIGNED FOR:" at 10442.61,-1665.76 h45
  text ".PRJ_Customer" at 10492.61,-1805.76 h70
  text "D" at -1317.39,-1873.76 h70
  text "D" at 13482.61,-1873.76 h70
  text "FILE NAME:" at 10442.61,-1965.76 h45
  text ".PCB_File_Name_No_Path" at 10492.61,-2085.76 h70
  text "Texas Instruments (TI) and/or its licensors do not warrant the accuracy or completeness of this specification" at 5473.11,-2247.6 h45
  text "ENGINEER:" at 10442.61,-2255.76 h45
  text "LAYOUT BY:" at 11947.61,-2255.76 h45
  text "or any information contained therein. TI and/or its licensors do not warrant that this design will meet" at 5428.12,-2360.26 h45
  text ".PRJ_Engineer" at 10492.61,-2410.75 h70
  text ".PCB_Layout" at 11998.11,-2410.75 h70
  text "the specifications, will be suitable for your application or fit for any particular purpose, or will operate in" at 5428.12,-2472.93 h45
  text ".Layer_Name" at -323.89,-2500.75 h60
  text "ALTIUM DESIGNER VERSION:" at 11947.61,-2565.76 h45
  text "an implementation. TI and/or its licensors do not warrant that the design is production worthy. You should" at 5428.12,-2585.59 h45
  text "completely validate and test your design implementation to confirm the system functionality for your application." at 5473.11,-2698.26 h45
  text ".print_Scale" at 10492.61,-2699.08 h70
  text ".Application_BuildNumber" at 11998.11,-2699.08 h70
  text "1" at -161.06,-2905.76 h70
  text "2" at 2334.61,-2905.76 h70
  text "3" at 4823.95,-2905.76 h70
  text "4" at 7330.62,-2905.76 h70
  text "5" at 9829.61,-2905.76 h70
  text "6" at 12334.61,-2905.76 h70

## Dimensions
-410,2121.49 to 2345.9,2121.49 on M2 Board Dimensions
-410,-155 to -410,2121.49 on M2 Board Dimensions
